VERSION 5.8 ;
BUSBITCHARS "[]" ;
DIVIDERCHAR "/" ;
UNITS
    DATABASE MICRONS 1000 ;
END UNITS

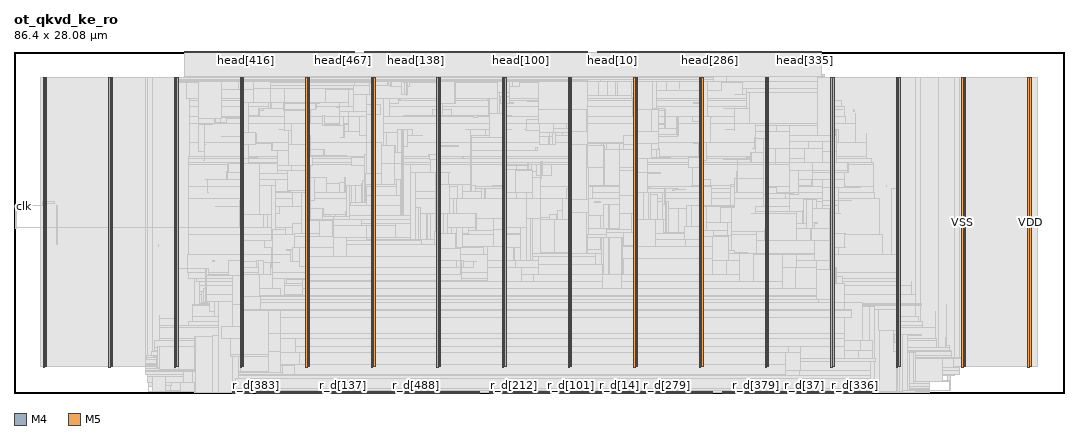
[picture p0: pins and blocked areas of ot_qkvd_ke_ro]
MACRO ot_qkvd_ke_ro
  FOREIGN ot_qkvd_ke_ro 0 0 ;
  CLASS BLOCK ;
  SIZE 86.4 BY 28.08 ;
  PIN clk
    DIRECTION INPUT ;
    USE SIGNAL ;
    PORT
      LAYER M4 ;
        RECT  0 15.312 0.084 15.336 ;
    END
  END clk
  PIN crq
    DIRECTION OUTPUT ;
    USE SIGNAL ;
    PORT
      LAYER M5 ;
        RECT  48.048 27.996 48.072 28.08 ;
    END
  END crq
  PIN en_i
    DIRECTION INPUT ;
    USE SIGNAL ;
    PORT
      LAYER M5 ;
        RECT  48.144 27.996 48.168 28.08 ;
    END
  END en_i
  PIN head[0]
    DIRECTION INPUT ;
    USE SIGNAL ;
    PORT
      LAYER M5 ;
        RECT  48.24 27.996 48.264 28.08 ;
    END
  END head[0]
  PIN head[100]
    DIRECTION INPUT ;
    USE SIGNAL ;
    PORT
      LAYER M5 ;
        RECT  41.712 27.996 41.736 28.08 ;
    END
  END head[100]
  PIN head[101]
    DIRECTION INPUT ;
    USE SIGNAL ;
    PORT
      LAYER M5 ;
        RECT  41.808 27.996 41.832 28.08 ;
    END
  END head[101]
  PIN head[102]
    DIRECTION INPUT ;
    USE SIGNAL ;
    PORT
      LAYER M5 ;
        RECT  41.904 27.996 41.928 28.08 ;
    END
  END head[102]
  PIN head[103]
    DIRECTION INPUT ;
    USE SIGNAL ;
    PORT
      LAYER M5 ;
        RECT  42 27.996 42.024 28.08 ;
    END
  END head[103]
  PIN head[104]
    DIRECTION INPUT ;
    USE SIGNAL ;
    PORT
      LAYER M5 ;
        RECT  42.096 27.996 42.12 28.08 ;
    END
  END head[104]
  PIN head[105]
    DIRECTION INPUT ;
    USE SIGNAL ;
    PORT
      LAYER M5 ;
        RECT  42.192 27.996 42.216 28.08 ;
    END
  END head[105]
  PIN head[106]
    DIRECTION INPUT ;
    USE SIGNAL ;
    PORT
      LAYER M5 ;
        RECT  42.288 27.996 42.312 28.08 ;
    END
  END head[106]
  PIN head[107]
    DIRECTION INPUT ;
    USE SIGNAL ;
    PORT
      LAYER M5 ;
        RECT  42.384 27.996 42.408 28.08 ;
    END
  END head[107]
  PIN head[108]
    DIRECTION INPUT ;
    USE SIGNAL ;
    PORT
      LAYER M5 ;
        RECT  42.48 27.996 42.504 28.08 ;
    END
  END head[108]
  PIN head[109]
    DIRECTION INPUT ;
    USE SIGNAL ;
    PORT
      LAYER M5 ;
        RECT  42.576 27.996 42.6 28.08 ;
    END
  END head[109]
  PIN head[10]
    DIRECTION INPUT ;
    USE SIGNAL ;
    PORT
      LAYER M5 ;
        RECT  49.2 27.996 49.224 28.08 ;
    END
  END head[10]
  PIN head[110]
    DIRECTION INPUT ;
    USE SIGNAL ;
    PORT
      LAYER M5 ;
        RECT  42.672 27.996 42.696 28.08 ;
    END
  END head[110]
  PIN head[111]
    DIRECTION INPUT ;
    USE SIGNAL ;
    PORT
      LAYER M5 ;
        RECT  42.768 27.996 42.792 28.08 ;
    END
  END head[111]
  PIN head[112]
    DIRECTION INPUT ;
    USE SIGNAL ;
    PORT
      LAYER M5 ;
        RECT  42.864 27.996 42.888 28.08 ;
    END
  END head[112]
  PIN head[113]
    DIRECTION INPUT ;
    USE SIGNAL ;
    PORT
      LAYER M5 ;
        RECT  42.96 27.996 42.984 28.08 ;
    END
  END head[113]
  PIN head[114]
    DIRECTION INPUT ;
    USE SIGNAL ;
    PORT
      LAYER M5 ;
        RECT  43.056 27.996 43.08 28.08 ;
    END
  END head[114]
  PIN head[115]
    DIRECTION INPUT ;
    USE SIGNAL ;
    PORT
      LAYER M5 ;
        RECT  43.152 27.996 43.176 28.08 ;
    END
  END head[115]
  PIN head[116]
    DIRECTION INPUT ;
    USE SIGNAL ;
    PORT
      LAYER M5 ;
        RECT  43.248 27.996 43.272 28.08 ;
    END
  END head[116]
  PIN head[117]
    DIRECTION INPUT ;
    USE SIGNAL ;
    PORT
      LAYER M5 ;
        RECT  43.344 27.996 43.368 28.08 ;
    END
  END head[117]
  PIN head[118]
    DIRECTION INPUT ;
    USE SIGNAL ;
    PORT
      LAYER M5 ;
        RECT  43.44 27.996 43.464 28.08 ;
    END
  END head[118]
  PIN head[119]
    DIRECTION INPUT ;
    USE SIGNAL ;
    PORT
      LAYER M5 ;
        RECT  43.536 27.996 43.56 28.08 ;
    END
  END head[119]
  PIN head[11]
    DIRECTION INPUT ;
    USE SIGNAL ;
    PORT
      LAYER M5 ;
        RECT  49.296 27.996 49.32 28.08 ;
    END
  END head[11]
  PIN head[120]
    DIRECTION INPUT ;
    USE SIGNAL ;
    PORT
      LAYER M5 ;
        RECT  43.632 27.996 43.656 28.08 ;
    END
  END head[120]
  PIN head[121]
    DIRECTION INPUT ;
    USE SIGNAL ;
    PORT
      LAYER M5 ;
        RECT  43.728 27.996 43.752 28.08 ;
    END
  END head[121]
  PIN head[122]
    DIRECTION INPUT ;
    USE SIGNAL ;
    PORT
      LAYER M5 ;
        RECT  43.824 27.996 43.848 28.08 ;
    END
  END head[122]
  PIN head[123]
    DIRECTION INPUT ;
    USE SIGNAL ;
    PORT
      LAYER M5 ;
        RECT  43.92 27.996 43.944 28.08 ;
    END
  END head[123]
  PIN head[124]
    DIRECTION INPUT ;
    USE SIGNAL ;
    PORT
      LAYER M5 ;
        RECT  44.016 27.996 44.04 28.08 ;
    END
  END head[124]
  PIN head[125]
    DIRECTION INPUT ;
    USE SIGNAL ;
    PORT
      LAYER M5 ;
        RECT  44.112 27.996 44.136 28.08 ;
    END
  END head[125]
  PIN head[126]
    DIRECTION INPUT ;
    USE SIGNAL ;
    PORT
      LAYER M5 ;
        RECT  31.92 27.996 31.944 28.08 ;
    END
  END head[126]
  PIN head[127]
    DIRECTION INPUT ;
    USE SIGNAL ;
    PORT
      LAYER M5 ;
        RECT  32.016 27.996 32.04 28.08 ;
    END
  END head[127]
  PIN head[128]
    DIRECTION INPUT ;
    USE SIGNAL ;
    PORT
      LAYER M5 ;
        RECT  32.112 27.996 32.136 28.08 ;
    END
  END head[128]
  PIN head[129]
    DIRECTION INPUT ;
    USE SIGNAL ;
    PORT
      LAYER M5 ;
        RECT  32.208 27.996 32.232 28.08 ;
    END
  END head[129]
  PIN head[12]
    DIRECTION INPUT ;
    USE SIGNAL ;
    PORT
      LAYER M5 ;
        RECT  49.392 27.996 49.416 28.08 ;
    END
  END head[12]
  PIN head[130]
    DIRECTION INPUT ;
    USE SIGNAL ;
    PORT
      LAYER M5 ;
        RECT  32.304 27.996 32.328 28.08 ;
    END
  END head[130]
  PIN head[131]
    DIRECTION INPUT ;
    USE SIGNAL ;
    PORT
      LAYER M5 ;
        RECT  32.4 27.996 32.424 28.08 ;
    END
  END head[131]
  PIN head[132]
    DIRECTION INPUT ;
    USE SIGNAL ;
    PORT
      LAYER M5 ;
        RECT  32.496 27.996 32.52 28.08 ;
    END
  END head[132]
  PIN head[133]
    DIRECTION INPUT ;
    USE SIGNAL ;
    PORT
      LAYER M5 ;
        RECT  32.592 27.996 32.616 28.08 ;
    END
  END head[133]
  PIN head[134]
    DIRECTION INPUT ;
    USE SIGNAL ;
    PORT
      LAYER M5 ;
        RECT  32.688 27.996 32.712 28.08 ;
    END
  END head[134]
  PIN head[135]
    DIRECTION INPUT ;
    USE SIGNAL ;
    PORT
      LAYER M5 ;
        RECT  32.784 27.996 32.808 28.08 ;
    END
  END head[135]
  PIN head[136]
    DIRECTION INPUT ;
    USE SIGNAL ;
    PORT
      LAYER M5 ;
        RECT  32.88 27.996 32.904 28.08 ;
    END
  END head[136]
  PIN head[137]
    DIRECTION INPUT ;
    USE SIGNAL ;
    PORT
      LAYER M5 ;
        RECT  32.976 27.996 33 28.08 ;
    END
  END head[137]
  PIN head[138]
    DIRECTION INPUT ;
    USE SIGNAL ;
    PORT
      LAYER M5 ;
        RECT  33.072 27.996 33.096 28.08 ;
    END
  END head[138]
  PIN head[139]
    DIRECTION INPUT ;
    USE SIGNAL ;
    PORT
      LAYER M5 ;
        RECT  33.168 27.996 33.192 28.08 ;
    END
  END head[139]
  PIN head[13]
    DIRECTION INPUT ;
    USE SIGNAL ;
    PORT
      LAYER M5 ;
        RECT  49.488 27.996 49.512 28.08 ;
    END
  END head[13]
  PIN head[140]
    DIRECTION INPUT ;
    USE SIGNAL ;
    PORT
      LAYER M5 ;
        RECT  33.264 27.996 33.288 28.08 ;
    END
  END head[140]
  PIN head[141]
    DIRECTION INPUT ;
    USE SIGNAL ;
    PORT
      LAYER M5 ;
        RECT  33.36 27.996 33.384 28.08 ;
    END
  END head[141]
  PIN head[142]
    DIRECTION INPUT ;
    USE SIGNAL ;
    PORT
      LAYER M5 ;
        RECT  33.456 27.996 33.48 28.08 ;
    END
  END head[142]
  PIN head[143]
    DIRECTION INPUT ;
    USE SIGNAL ;
    PORT
      LAYER M5 ;
        RECT  33.552 27.996 33.576 28.08 ;
    END
  END head[143]
  PIN head[144]
    DIRECTION INPUT ;
    USE SIGNAL ;
    PORT
      LAYER M5 ;
        RECT  33.648 27.996 33.672 28.08 ;
    END
  END head[144]
  PIN head[145]
    DIRECTION INPUT ;
    USE SIGNAL ;
    PORT
      LAYER M5 ;
        RECT  33.744 27.996 33.768 28.08 ;
    END
  END head[145]
  PIN head[146]
    DIRECTION INPUT ;
    USE SIGNAL ;
    PORT
      LAYER M5 ;
        RECT  33.84 27.996 33.864 28.08 ;
    END
  END head[146]
  PIN head[147]
    DIRECTION INPUT ;
    USE SIGNAL ;
    PORT
      LAYER M5 ;
        RECT  33.936 27.996 33.96 28.08 ;
    END
  END head[147]
  PIN head[148]
    DIRECTION INPUT ;
    USE SIGNAL ;
    PORT
      LAYER M5 ;
        RECT  34.032 27.996 34.056 28.08 ;
    END
  END head[148]
  PIN head[149]
    DIRECTION INPUT ;
    USE SIGNAL ;
    PORT
      LAYER M5 ;
        RECT  34.128 27.996 34.152 28.08 ;
    END
  END head[149]
  PIN head[14]
    DIRECTION INPUT ;
    USE SIGNAL ;
    PORT
      LAYER M5 ;
        RECT  49.584 27.996 49.608 28.08 ;
    END
  END head[14]
  PIN head[150]
    DIRECTION INPUT ;
    USE SIGNAL ;
    PORT
      LAYER M5 ;
        RECT  34.224 27.996 34.248 28.08 ;
    END
  END head[150]
  PIN head[151]
    DIRECTION INPUT ;
    USE SIGNAL ;
    PORT
      LAYER M5 ;
        RECT  34.32 27.996 34.344 28.08 ;
    END
  END head[151]
  PIN head[152]
    DIRECTION INPUT ;
    USE SIGNAL ;
    PORT
      LAYER M5 ;
        RECT  34.416 27.996 34.44 28.08 ;
    END
  END head[152]
  PIN head[153]
    DIRECTION INPUT ;
    USE SIGNAL ;
    PORT
      LAYER M5 ;
        RECT  34.512 27.996 34.536 28.08 ;
    END
  END head[153]
  PIN head[154]
    DIRECTION INPUT ;
    USE SIGNAL ;
    PORT
      LAYER M5 ;
        RECT  34.608 27.996 34.632 28.08 ;
    END
  END head[154]
  PIN head[155]
    DIRECTION INPUT ;
    USE SIGNAL ;
    PORT
      LAYER M5 ;
        RECT  34.704 27.996 34.728 28.08 ;
    END
  END head[155]
  PIN head[156]
    DIRECTION INPUT ;
    USE SIGNAL ;
    PORT
      LAYER M5 ;
        RECT  34.8 27.996 34.824 28.08 ;
    END
  END head[156]
  PIN head[157]
    DIRECTION INPUT ;
    USE SIGNAL ;
    PORT
      LAYER M5 ;
        RECT  34.896 27.996 34.92 28.08 ;
    END
  END head[157]
  PIN head[158]
    DIRECTION INPUT ;
    USE SIGNAL ;
    PORT
      LAYER M5 ;
        RECT  38.064 27.996 38.088 28.08 ;
    END
  END head[158]
  PIN head[159]
    DIRECTION INPUT ;
    USE SIGNAL ;
    PORT
      LAYER M5 ;
        RECT  38.16 27.996 38.184 28.08 ;
    END
  END head[159]
  PIN head[15]
    DIRECTION INPUT ;
    USE SIGNAL ;
    PORT
      LAYER M5 ;
        RECT  49.68 27.996 49.704 28.08 ;
    END
  END head[15]
  PIN head[160]
    DIRECTION INPUT ;
    USE SIGNAL ;
    PORT
      LAYER M5 ;
        RECT  38.256 27.996 38.28 28.08 ;
    END
  END head[160]
  PIN head[161]
    DIRECTION INPUT ;
    USE SIGNAL ;
    PORT
      LAYER M5 ;
        RECT  38.352 27.996 38.376 28.08 ;
    END
  END head[161]
  PIN head[162]
    DIRECTION INPUT ;
    USE SIGNAL ;
    PORT
      LAYER M5 ;
        RECT  38.448 27.996 38.472 28.08 ;
    END
  END head[162]
  PIN head[163]
    DIRECTION INPUT ;
    USE SIGNAL ;
    PORT
      LAYER M5 ;
        RECT  38.544 27.996 38.568 28.08 ;
    END
  END head[163]
  PIN head[164]
    DIRECTION INPUT ;
    USE SIGNAL ;
    PORT
      LAYER M5 ;
        RECT  38.64 27.996 38.664 28.08 ;
    END
  END head[164]
  PIN head[165]
    DIRECTION INPUT ;
    USE SIGNAL ;
    PORT
      LAYER M5 ;
        RECT  38.736 27.996 38.76 28.08 ;
    END
  END head[165]
  PIN head[166]
    DIRECTION INPUT ;
    USE SIGNAL ;
    PORT
      LAYER M5 ;
        RECT  38.832 27.996 38.856 28.08 ;
    END
  END head[166]
  PIN head[167]
    DIRECTION INPUT ;
    USE SIGNAL ;
    PORT
      LAYER M5 ;
        RECT  38.928 27.996 38.952 28.08 ;
    END
  END head[167]
  PIN head[168]
    DIRECTION INPUT ;
    USE SIGNAL ;
    PORT
      LAYER M5 ;
        RECT  39.024 27.996 39.048 28.08 ;
    END
  END head[168]
  PIN head[169]
    DIRECTION INPUT ;
    USE SIGNAL ;
    PORT
      LAYER M5 ;
        RECT  39.12 27.996 39.144 28.08 ;
    END
  END head[169]
  PIN head[16]
    DIRECTION INPUT ;
    USE SIGNAL ;
    PORT
      LAYER M5 ;
        RECT  49.776 27.996 49.8 28.08 ;
    END
  END head[16]
  PIN head[170]
    DIRECTION INPUT ;
    USE SIGNAL ;
    PORT
      LAYER M5 ;
        RECT  39.216 27.996 39.24 28.08 ;
    END
  END head[170]
  PIN head[171]
    DIRECTION INPUT ;
    USE SIGNAL ;
    PORT
      LAYER M5 ;
        RECT  39.312 27.996 39.336 28.08 ;
    END
  END head[171]
  PIN head[172]
    DIRECTION INPUT ;
    USE SIGNAL ;
    PORT
      LAYER M5 ;
        RECT  39.408 27.996 39.432 28.08 ;
    END
  END head[172]
  PIN head[173]
    DIRECTION INPUT ;
    USE SIGNAL ;
    PORT
      LAYER M5 ;
        RECT  39.504 27.996 39.528 28.08 ;
    END
  END head[173]
  PIN head[174]
    DIRECTION INPUT ;
    USE SIGNAL ;
    PORT
      LAYER M5 ;
        RECT  39.6 27.996 39.624 28.08 ;
    END
  END head[174]
  PIN head[175]
    DIRECTION INPUT ;
    USE SIGNAL ;
    PORT
      LAYER M5 ;
        RECT  39.696 27.996 39.72 28.08 ;
    END
  END head[175]
  PIN head[176]
    DIRECTION INPUT ;
    USE SIGNAL ;
    PORT
      LAYER M5 ;
        RECT  39.792 27.996 39.816 28.08 ;
    END
  END head[176]
  PIN head[177]
    DIRECTION INPUT ;
    USE SIGNAL ;
    PORT
      LAYER M5 ;
        RECT  39.888 27.996 39.912 28.08 ;
    END
  END head[177]
  PIN head[178]
    DIRECTION INPUT ;
    USE SIGNAL ;
    PORT
      LAYER M5 ;
        RECT  39.984 27.996 40.008 28.08 ;
    END
  END head[178]
  PIN head[179]
    DIRECTION INPUT ;
    USE SIGNAL ;
    PORT
      LAYER M5 ;
        RECT  40.08 27.996 40.104 28.08 ;
    END
  END head[179]
  PIN head[17]
    DIRECTION INPUT ;
    USE SIGNAL ;
    PORT
      LAYER M5 ;
        RECT  49.872 27.996 49.896 28.08 ;
    END
  END head[17]
  PIN head[180]
    DIRECTION INPUT ;
    USE SIGNAL ;
    PORT
      LAYER M5 ;
        RECT  40.176 27.996 40.2 28.08 ;
    END
  END head[180]
  PIN head[181]
    DIRECTION INPUT ;
    USE SIGNAL ;
    PORT
      LAYER M5 ;
        RECT  40.272 27.996 40.296 28.08 ;
    END
  END head[181]
  PIN head[182]
    DIRECTION INPUT ;
    USE SIGNAL ;
    PORT
      LAYER M5 ;
        RECT  40.368 27.996 40.392 28.08 ;
    END
  END head[182]
  PIN head[183]
    DIRECTION INPUT ;
    USE SIGNAL ;
    PORT
      LAYER M5 ;
        RECT  40.464 27.996 40.488 28.08 ;
    END
  END head[183]
  PIN head[184]
    DIRECTION INPUT ;
    USE SIGNAL ;
    PORT
      LAYER M5 ;
        RECT  40.56 27.996 40.584 28.08 ;
    END
  END head[184]
  PIN head[185]
    DIRECTION INPUT ;
    USE SIGNAL ;
    PORT
      LAYER M5 ;
        RECT  40.656 27.996 40.68 28.08 ;
    END
  END head[185]
  PIN head[186]
    DIRECTION INPUT ;
    USE SIGNAL ;
    PORT
      LAYER M5 ;
        RECT  40.752 27.996 40.776 28.08 ;
    END
  END head[186]
  PIN head[187]
    DIRECTION INPUT ;
    USE SIGNAL ;
    PORT
      LAYER M5 ;
        RECT  40.848 27.996 40.872 28.08 ;
    END
  END head[187]
  PIN head[188]
    DIRECTION INPUT ;
    USE SIGNAL ;
    PORT
      LAYER M5 ;
        RECT  40.944 27.996 40.968 28.08 ;
    END
  END head[188]
  PIN head[189]
    DIRECTION INPUT ;
    USE SIGNAL ;
    PORT
      LAYER M5 ;
        RECT  41.04 27.996 41.064 28.08 ;
    END
  END head[189]
  PIN head[18]
    DIRECTION INPUT ;
    USE SIGNAL ;
    PORT
      LAYER M5 ;
        RECT  49.968 27.996 49.992 28.08 ;
    END
  END head[18]
  PIN head[190]
    DIRECTION INPUT ;
    USE SIGNAL ;
    PORT
      LAYER M5 ;
        RECT  34.992 27.996 35.016 28.08 ;
    END
  END head[190]
  PIN head[191]
    DIRECTION INPUT ;
    USE SIGNAL ;
    PORT
      LAYER M5 ;
        RECT  35.088 27.996 35.112 28.08 ;
    END
  END head[191]
  PIN head[192]
    DIRECTION INPUT ;
    USE SIGNAL ;
    PORT
      LAYER M5 ;
        RECT  35.184 27.996 35.208 28.08 ;
    END
  END head[192]
  PIN head[193]
    DIRECTION INPUT ;
    USE SIGNAL ;
    PORT
      LAYER M5 ;
        RECT  35.28 27.996 35.304 28.08 ;
    END
  END head[193]
  PIN head[194]
    DIRECTION INPUT ;
    USE SIGNAL ;
    PORT
      LAYER M5 ;
        RECT  35.376 27.996 35.4 28.08 ;
    END
  END head[194]
  PIN head[195]
    DIRECTION INPUT ;
    USE SIGNAL ;
    PORT
      LAYER M5 ;
        RECT  35.472 27.996 35.496 28.08 ;
    END
  END head[195]
  PIN head[196]
    DIRECTION INPUT ;
    USE SIGNAL ;
    PORT
      LAYER M5 ;
        RECT  35.568 27.996 35.592 28.08 ;
    END
  END head[196]
  PIN head[197]
    DIRECTION INPUT ;
    USE SIGNAL ;
    PORT
      LAYER M5 ;
        RECT  35.664 27.996 35.688 28.08 ;
    END
  END head[197]
  PIN head[198]
    DIRECTION INPUT ;
    USE SIGNAL ;
    PORT
      LAYER M5 ;
        RECT  35.76 27.996 35.784 28.08 ;
    END
  END head[198]
  PIN head[199]
    DIRECTION INPUT ;
    USE SIGNAL ;
    PORT
      LAYER M5 ;
        RECT  35.856 27.996 35.88 28.08 ;
    END
  END head[199]
  PIN head[19]
    DIRECTION INPUT ;
    USE SIGNAL ;
    PORT
      LAYER M5 ;
        RECT  50.064 27.996 50.088 28.08 ;
    END
  END head[19]
  PIN head[1]
    DIRECTION INPUT ;
    USE SIGNAL ;
    PORT
      LAYER M5 ;
        RECT  48.336 27.996 48.36 28.08 ;
    END
  END head[1]
  PIN head[200]
    DIRECTION INPUT ;
    USE SIGNAL ;
    PORT
      LAYER M5 ;
        RECT  35.952 27.996 35.976 28.08 ;
    END
  END head[200]
  PIN head[201]
    DIRECTION INPUT ;
    USE SIGNAL ;
    PORT
      LAYER M5 ;
        RECT  36.048 27.996 36.072 28.08 ;
    END
  END head[201]
  PIN head[202]
    DIRECTION INPUT ;
    USE SIGNAL ;
    PORT
      LAYER M5 ;
        RECT  36.144 27.996 36.168 28.08 ;
    END
  END head[202]
  PIN head[203]
    DIRECTION INPUT ;
    USE SIGNAL ;
    PORT
      LAYER M5 ;
        RECT  36.24 27.996 36.264 28.08 ;
    END
  END head[203]
  PIN head[204]
    DIRECTION INPUT ;
    USE SIGNAL ;
    PORT
      LAYER M5 ;
        RECT  36.336 27.996 36.36 28.08 ;
    END
  END head[204]
  PIN head[205]
    DIRECTION INPUT ;
    USE SIGNAL ;
    PORT
      LAYER M5 ;
        RECT  36.432 27.996 36.456 28.08 ;
    END
  END head[205]
  PIN head[206]
    DIRECTION INPUT ;
    USE SIGNAL ;
    PORT
      LAYER M5 ;
        RECT  36.528 27.996 36.552 28.08 ;
    END
  END head[206]
  PIN head[207]
    DIRECTION INPUT ;
    USE SIGNAL ;
    PORT
      LAYER M5 ;
        RECT  36.624 27.996 36.648 28.08 ;
    END
  END head[207]
  PIN head[208]
    DIRECTION INPUT ;
    USE SIGNAL ;
    PORT
      LAYER M5 ;
        RECT  36.72 27.996 36.744 28.08 ;
    END
  END head[208]
  PIN head[209]
    DIRECTION INPUT ;
    USE SIGNAL ;
    PORT
      LAYER M5 ;
        RECT  36.816 27.996 36.84 28.08 ;
    END
  END head[209]
  PIN head[20]
    DIRECTION INPUT ;
    USE SIGNAL ;
    PORT
      LAYER M5 ;
        RECT  50.16 27.996 50.184 28.08 ;
    END
  END head[20]
  PIN head[210]
    DIRECTION INPUT ;
    USE SIGNAL ;
    PORT
      LAYER M5 ;
        RECT  36.912 27.996 36.936 28.08 ;
    END
  END head[210]
  PIN head[211]
    DIRECTION INPUT ;
    USE SIGNAL ;
    PORT
      LAYER M5 ;
        RECT  37.008 27.996 37.032 28.08 ;
    END
  END head[211]
  PIN head[212]
    DIRECTION INPUT ;
    USE SIGNAL ;
    PORT
      LAYER M5 ;
        RECT  37.104 27.996 37.128 28.08 ;
    END
  END head[212]
  PIN head[213]
    DIRECTION INPUT ;
    USE SIGNAL ;
    PORT
      LAYER M5 ;
        RECT  37.2 27.996 37.224 28.08 ;
    END
  END head[213]
  PIN head[214]
    DIRECTION INPUT ;
    USE SIGNAL ;
    PORT
      LAYER M5 ;
        RECT  37.296 27.996 37.32 28.08 ;
    END
  END head[214]
  PIN head[215]
    DIRECTION INPUT ;
    USE SIGNAL ;
    PORT
      LAYER M5 ;
        RECT  37.392 27.996 37.416 28.08 ;
    END
  END head[215]
  PIN head[216]
    DIRECTION INPUT ;
    USE SIGNAL ;
    PORT
      LAYER M5 ;
        RECT  37.488 27.996 37.512 28.08 ;
    END
  END head[216]
  PIN head[217]
    DIRECTION INPUT ;
    USE SIGNAL ;
    PORT
      LAYER M5 ;
        RECT  37.584 27.996 37.608 28.08 ;
    END
  END head[217]
  PIN head[218]
    DIRECTION INPUT ;
    USE SIGNAL ;
    PORT
      LAYER M5 ;
        RECT  37.68 27.996 37.704 28.08 ;
    END
  END head[218]
  PIN head[219]
    DIRECTION INPUT ;
    USE SIGNAL ;
    PORT
      LAYER M5 ;
        RECT  37.776 27.996 37.8 28.08 ;
    END
  END head[219]
  PIN head[21]
    DIRECTION INPUT ;
    USE SIGNAL ;
    PORT
      LAYER M5 ;
        RECT  50.256 27.996 50.28 28.08 ;
    END
  END head[21]
  PIN head[220]
    DIRECTION INPUT ;
    USE SIGNAL ;
    PORT
      LAYER M5 ;
        RECT  37.872 27.996 37.896 28.08 ;
    END
  END head[220]
  PIN head[221]
    DIRECTION INPUT ;
    USE SIGNAL ;
    PORT
      LAYER M5 ;
        RECT  37.968 27.996 37.992 28.08 ;
    END
  END head[221]
  PIN head[222]
    DIRECTION INPUT ;
    USE SIGNAL ;
    PORT
      LAYER M5 ;
        RECT  28.848 27.996 28.872 28.08 ;
    END
  END head[222]
  PIN head[223]
    DIRECTION INPUT ;
    USE SIGNAL ;
    PORT
      LAYER M5 ;
        RECT  28.944 27.996 28.968 28.08 ;
    END
  END head[223]
  PIN head[224]
    DIRECTION INPUT ;
    USE SIGNAL ;
    PORT
      LAYER M5 ;
        RECT  29.04 27.996 29.064 28.08 ;
    END
  END head[224]
  PIN head[225]
    DIRECTION INPUT ;
    USE SIGNAL ;
    PORT
      LAYER M5 ;
        RECT  29.136 27.996 29.16 28.08 ;
    END
  END head[225]
  PIN head[226]
    DIRECTION INPUT ;
    USE SIGNAL ;
    PORT
      LAYER M5 ;
        RECT  29.232 27.996 29.256 28.08 ;
    END
  END head[226]
  PIN head[227]
    DIRECTION INPUT ;
    USE SIGNAL ;
    PORT
      LAYER M5 ;
        RECT  29.328 27.996 29.352 28.08 ;
    END
  END head[227]
  PIN head[228]
    DIRECTION INPUT ;
    USE SIGNAL ;
    PORT
      LAYER M5 ;
        RECT  29.424 27.996 29.448 28.08 ;
    END
  END head[228]
  PIN head[229]
    DIRECTION INPUT ;
    USE SIGNAL ;
    PORT
      LAYER M5 ;
        RECT  29.52 27.996 29.544 28.08 ;
    END
  END head[229]
  PIN head[22]
    DIRECTION INPUT ;
    USE SIGNAL ;
    PORT
      LAYER M5 ;
        RECT  50.352 27.996 50.376 28.08 ;
    END
  END head[22]
  PIN head[230]
    DIRECTION INPUT ;
    USE SIGNAL ;
    PORT
      LAYER M5 ;
        RECT  29.616 27.996 29.64 28.08 ;
    END
  END head[230]
  PIN head[231]
    DIRECTION INPUT ;
    USE SIGNAL ;
    PORT
      LAYER M5 ;
        RECT  29.712 27.996 29.736 28.08 ;
    END
  END head[231]
  PIN head[232]
    DIRECTION INPUT ;
    USE SIGNAL ;
    PORT
      LAYER M5 ;
        RECT  29.808 27.996 29.832 28.08 ;
    END
  END head[232]
  PIN head[233]
    DIRECTION INPUT ;
    USE SIGNAL ;
    PORT
      LAYER M5 ;
        RECT  29.904 27.996 29.928 28.08 ;
    END
  END head[233]
  PIN head[234]
    DIRECTION INPUT ;
    USE SIGNAL ;
    PORT
      LAYER M5 ;
        RECT  30 27.996 30.024 28.08 ;
    END
  END head[234]
  PIN head[235]
    DIRECTION INPUT ;
    USE SIGNAL ;
    PORT
      LAYER M5 ;
        RECT  30.096 27.996 30.12 28.08 ;
    END
  END head[235]
  PIN head[236]
    DIRECTION INPUT ;
    USE SIGNAL ;
    PORT
      LAYER M5 ;
        RECT  30.192 27.996 30.216 28.08 ;
    END
  END head[236]
  PIN head[237]
    DIRECTION INPUT ;
    USE SIGNAL ;
    PORT
      LAYER M5 ;
        RECT  30.288 27.996 30.312 28.08 ;
    END
  END head[237]
  PIN head[238]
    DIRECTION INPUT ;
    USE SIGNAL ;
    PORT
      LAYER M5 ;
        RECT  30.384 27.996 30.408 28.08 ;
    END
  END head[238]
  PIN head[239]
    DIRECTION INPUT ;
    USE SIGNAL ;
    PORT
      LAYER M5 ;
        RECT  30.48 27.996 30.504 28.08 ;
    END
  END head[239]
  PIN head[23]
    DIRECTION INPUT ;
    USE SIGNAL ;
    PORT
      LAYER M5 ;
        RECT  50.448 27.996 50.472 28.08 ;
    END
  END head[23]
  PIN head[240]
    DIRECTION INPUT ;
    USE SIGNAL ;
    PORT
      LAYER M5 ;
        RECT  30.576 27.996 30.6 28.08 ;
    END
  END head[240]
  PIN head[241]
    DIRECTION INPUT ;
    USE SIGNAL ;
    PORT
      LAYER M5 ;
        RECT  30.672 27.996 30.696 28.08 ;
    END
  END head[241]
  PIN head[242]
    DIRECTION INPUT ;
    USE SIGNAL ;
    PORT
      LAYER M5 ;
        RECT  30.768 27.996 30.792 28.08 ;
    END
  END head[242]
  PIN head[243]
    DIRECTION INPUT ;
    USE SIGNAL ;
    PORT
      LAYER M5 ;
        RECT  30.864 27.996 30.888 28.08 ;
    END
  END head[243]
  PIN head[244]
    DIRECTION INPUT ;
    USE SIGNAL ;
    PORT
      LAYER M5 ;
        RECT  30.96 27.996 30.984 28.08 ;
    END
  END head[244]
  PIN head[245]
    DIRECTION INPUT ;
    USE SIGNAL ;
    PORT
      LAYER M5 ;
        RECT  31.056 27.996 31.08 28.08 ;
    END
  END head[245]
  PIN head[246]
    DIRECTION INPUT ;
    USE SIGNAL ;
    PORT
      LAYER M5 ;
        RECT  31.152 27.996 31.176 28.08 ;
    END
  END head[246]
  PIN head[247]
    DIRECTION INPUT ;
    USE SIGNAL ;
    PORT
      LAYER M5 ;
        RECT  31.248 27.996 31.272 28.08 ;
    END
  END head[247]
  PIN head[248]
    DIRECTION INPUT ;
    USE SIGNAL ;
    PORT
      LAYER M5 ;
        RECT  31.344 27.996 31.368 28.08 ;
    END
  END head[248]
  PIN head[249]
    DIRECTION INPUT ;
    USE SIGNAL ;
    PORT
      LAYER M5 ;
        RECT  31.44 27.996 31.464 28.08 ;
    END
  END head[249]
  PIN head[24]
    DIRECTION INPUT ;
    USE SIGNAL ;
    PORT
      LAYER M5 ;
        RECT  50.544 27.996 50.568 28.08 ;
    END
  END head[24]
  PIN head[250]
    DIRECTION INPUT ;
    USE SIGNAL ;
    PORT
      LAYER M5 ;
        RECT  31.536 27.996 31.56 28.08 ;
    END
  END head[250]
  PIN head[251]
    DIRECTION INPUT ;
    USE SIGNAL ;
    PORT
      LAYER M5 ;
        RECT  31.632 27.996 31.656 28.08 ;
    END
  END head[251]
  PIN head[252]
    DIRECTION INPUT ;
    USE SIGNAL ;
    PORT
      LAYER M5 ;
        RECT  31.728 27.996 31.752 28.08 ;
    END
  END head[252]
  PIN head[253]
    DIRECTION INPUT ;
    USE SIGNAL ;
    PORT
      LAYER M5 ;
        RECT  31.824 27.996 31.848 28.08 ;
    END
  END head[253]
  PIN head[254]
    DIRECTION INPUT ;
    USE SIGNAL ;
    PORT
      LAYER M5 ;
        RECT  51.12 27.996 51.144 28.08 ;
    END
  END head[254]
  PIN head[255]
    DIRECTION INPUT ;
    USE SIGNAL ;
    PORT
      LAYER M5 ;
        RECT  51.216 27.996 51.24 28.08 ;
    END
  END head[255]
  PIN head[256]
    DIRECTION INPUT ;
    USE SIGNAL ;
    PORT
      LAYER M5 ;
        RECT  51.312 27.996 51.336 28.08 ;
    END
  END head[256]
  PIN head[257]
    DIRECTION INPUT ;
    USE SIGNAL ;
    PORT
      LAYER M5 ;
        RECT  51.408 27.996 51.432 28.08 ;
    END
  END head[257]
  PIN head[258]
    DIRECTION INPUT ;
    USE SIGNAL ;
    PORT
      LAYER M5 ;
        RECT  51.504 27.996 51.528 28.08 ;
    END
  END head[258]
  PIN head[259]
    DIRECTION INPUT ;
    USE SIGNAL ;
    PORT
      LAYER M5 ;
        RECT  51.6 27.996 51.624 28.08 ;
    END
  END head[259]
  PIN head[25]
    DIRECTION INPUT ;
    USE SIGNAL ;
    PORT
      LAYER M5 ;
        RECT  50.64 27.996 50.664 28.08 ;
    END
  END head[25]
  PIN head[260]
    DIRECTION INPUT ;
    USE SIGNAL ;
    PORT
      LAYER M5 ;
        RECT  51.696 27.996 51.72 28.08 ;
    END
  END head[260]
  PIN head[261]
    DIRECTION INPUT ;
    USE SIGNAL ;
    PORT
      LAYER M5 ;
        RECT  51.792 27.996 51.816 28.08 ;
    END
  END head[261]
  PIN head[262]
    DIRECTION INPUT ;
    USE SIGNAL ;
    PORT
      LAYER M5 ;
        RECT  51.888 27.996 51.912 28.08 ;
    END
  END head[262]
  PIN head[263]
    DIRECTION INPUT ;
    USE SIGNAL ;
    PORT
      LAYER M5 ;
        RECT  51.984 27.996 52.008 28.08 ;
    END
  END head[263]
  PIN head[264]
    DIRECTION INPUT ;
    USE SIGNAL ;
    PORT
      LAYER M5 ;
        RECT  52.08 27.996 52.104 28.08 ;
    END
  END head[264]
  PIN head[265]
    DIRECTION INPUT ;
    USE SIGNAL ;
    PORT
      LAYER M5 ;
        RECT  52.176 27.996 52.2 28.08 ;
    END
  END head[265]
  PIN head[266]
    DIRECTION INPUT ;
    USE SIGNAL ;
    PORT
      LAYER M5 ;
        RECT  52.272 27.996 52.296 28.08 ;
    END
  END head[266]
  PIN head[267]
    DIRECTION INPUT ;
    USE SIGNAL ;
    PORT
      LAYER M5 ;
        RECT  52.368 27.996 52.392 28.08 ;
    END
  END head[267]
  PIN head[268]
    DIRECTION INPUT ;
    USE SIGNAL ;
    PORT
      LAYER M5 ;
        RECT  52.464 27.996 52.488 28.08 ;
    END
  END head[268]
  PIN head[269]
    DIRECTION INPUT ;
    USE SIGNAL ;
    PORT
      LAYER M5 ;
        RECT  52.56 27.996 52.584 28.08 ;
    END
  END head[269]
  PIN head[26]
    DIRECTION INPUT ;
    USE SIGNAL ;
    PORT
      LAYER M5 ;
        RECT  50.736 27.996 50.76 28.08 ;
    END
  END head[26]
  PIN head[270]
    DIRECTION INPUT ;
    USE SIGNAL ;
    PORT
      LAYER M5 ;
        RECT  52.656 27.996 52.68 28.08 ;
    END
  END head[270]
  PIN head[271]
    DIRECTION INPUT ;
    USE SIGNAL ;
    PORT
      LAYER M5 ;
        RECT  52.752 27.996 52.776 28.08 ;
    END
  END head[271]
  PIN head[272]
    DIRECTION INPUT ;
    USE SIGNAL ;
    PORT
      LAYER M5 ;
        RECT  52.848 27.996 52.872 28.08 ;
    END
  END head[272]
  PIN head[273]
    DIRECTION INPUT ;
    USE SIGNAL ;
    PORT
      LAYER M5 ;
        RECT  52.944 27.996 52.968 28.08 ;
    END
  END head[273]
  PIN head[274]
    DIRECTION INPUT ;
    USE SIGNAL ;
    PORT
      LAYER M5 ;
        RECT  53.04 27.996 53.064 28.08 ;
    END
  END head[274]
  PIN head[275]
    DIRECTION INPUT ;
    USE SIGNAL ;
    PORT
      LAYER M5 ;
        RECT  53.136 27.996 53.16 28.08 ;
    END
  END head[275]
  PIN head[276]
    DIRECTION INPUT ;
    USE SIGNAL ;
    PORT
      LAYER M5 ;
        RECT  53.232 27.996 53.256 28.08 ;
    END
  END head[276]
  PIN head[277]
    DIRECTION INPUT ;
    USE SIGNAL ;
    PORT
      LAYER M5 ;
        RECT  53.328 27.996 53.352 28.08 ;
    END
  END head[277]
  PIN head[278]
    DIRECTION INPUT ;
    USE SIGNAL ;
    PORT
      LAYER M5 ;
        RECT  53.424 27.996 53.448 28.08 ;
    END
  END head[278]
  PIN head[279]
    DIRECTION INPUT ;
    USE SIGNAL ;
    PORT
      LAYER M5 ;
        RECT  53.52 27.996 53.544 28.08 ;
    END
  END head[279]
  PIN head[27]
    DIRECTION INPUT ;
    USE SIGNAL ;
    PORT
      LAYER M5 ;
        RECT  50.832 27.996 50.856 28.08 ;
    END
  END head[27]
  PIN head[280]
    DIRECTION INPUT ;
    USE SIGNAL ;
    PORT
      LAYER M5 ;
        RECT  53.616 27.996 53.64 28.08 ;
    END
  END head[280]
  PIN head[281]
    DIRECTION INPUT ;
    USE SIGNAL ;
    PORT
      LAYER M5 ;
        RECT  53.712 27.996 53.736 28.08 ;
    END
  END head[281]
  PIN head[282]
    DIRECTION INPUT ;
    USE SIGNAL ;
    PORT
      LAYER M5 ;
        RECT  53.808 27.996 53.832 28.08 ;
    END
  END head[282]
  PIN head[283]
    DIRECTION INPUT ;
    USE SIGNAL ;
    PORT
      LAYER M5 ;
        RECT  53.904 27.996 53.928 28.08 ;
    END
  END head[283]
  PIN head[284]
    DIRECTION INPUT ;
    USE SIGNAL ;
    PORT
      LAYER M5 ;
        RECT  54 27.996 54.024 28.08 ;
    END
  END head[284]
  PIN head[285]
    DIRECTION INPUT ;
    USE SIGNAL ;
    PORT
      LAYER M5 ;
        RECT  54.096 27.996 54.12 28.08 ;
    END
  END head[285]
  PIN head[286]
    DIRECTION INPUT ;
    USE SIGNAL ;
    PORT
      LAYER M5 ;
        RECT  57.264 27.996 57.288 28.08 ;
    END
  END head[286]
  PIN head[287]
    DIRECTION INPUT ;
    USE SIGNAL ;
    PORT
      LAYER M5 ;
        RECT  57.36 27.996 57.384 28.08 ;
    END
  END head[287]
  PIN head[288]
    DIRECTION INPUT ;
    USE SIGNAL ;
    PORT
      LAYER M5 ;
        RECT  57.456 27.996 57.48 28.08 ;
    END
  END head[288]
  PIN head[289]
    DIRECTION INPUT ;
    USE SIGNAL ;
    PORT
      LAYER M5 ;
        RECT  57.552 27.996 57.576 28.08 ;
    END
  END head[289]
  PIN head[28]
    DIRECTION INPUT ;
    USE SIGNAL ;
    PORT
      LAYER M5 ;
        RECT  50.928 27.996 50.952 28.08 ;
    END
  END head[28]
  PIN head[290]
    DIRECTION INPUT ;
    USE SIGNAL ;
    PORT
      LAYER M5 ;
        RECT  57.648 27.996 57.672 28.08 ;
    END
  END head[290]
  PIN head[291]
    DIRECTION INPUT ;
    USE SIGNAL ;
    PORT
      LAYER M5 ;
        RECT  57.744 27.996 57.768 28.08 ;
    END
  END head[291]
  PIN head[292]
    DIRECTION INPUT ;
    USE SIGNAL ;
    PORT
      LAYER M5 ;
        RECT  57.84 27.996 57.864 28.08 ;
    END
  END head[292]
  PIN head[293]
    DIRECTION INPUT ;
    USE SIGNAL ;
    PORT
      LAYER M5 ;
        RECT  57.936 27.996 57.96 28.08 ;
    END
  END head[293]
  PIN head[294]
    DIRECTION INPUT ;
    USE SIGNAL ;
    PORT
      LAYER M5 ;
        RECT  58.032 27.996 58.056 28.08 ;
    END
  END head[294]
  PIN head[295]
    DIRECTION INPUT ;
    USE SIGNAL ;
    PORT
      LAYER M5 ;
        RECT  58.128 27.996 58.152 28.08 ;
    END
  END head[295]
  PIN head[296]
    DIRECTION INPUT ;
    USE SIGNAL ;
    PORT
      LAYER M5 ;
        RECT  58.224 27.996 58.248 28.08 ;
    END
  END head[296]
  PIN head[297]
    DIRECTION INPUT ;
    USE SIGNAL ;
    PORT
      LAYER M5 ;
        RECT  58.32 27.996 58.344 28.08 ;
    END
  END head[297]
  PIN head[298]
    DIRECTION INPUT ;
    USE SIGNAL ;
    PORT
      LAYER M5 ;
        RECT  58.416 27.996 58.44 28.08 ;
    END
  END head[298]
  PIN head[299]
    DIRECTION INPUT ;
    USE SIGNAL ;
    PORT
      LAYER M5 ;
        RECT  58.512 27.996 58.536 28.08 ;
    END
  END head[299]
  PIN head[29]
    DIRECTION INPUT ;
    USE SIGNAL ;
    PORT
      LAYER M5 ;
        RECT  51.024 27.996 51.048 28.08 ;
    END
  END head[29]
  PIN head[2]
    DIRECTION INPUT ;
    USE SIGNAL ;
    PORT
      LAYER M5 ;
        RECT  48.432 27.996 48.456 28.08 ;
    END
  END head[2]
  PIN head[300]
    DIRECTION INPUT ;
    USE SIGNAL ;
    PORT
      LAYER M5 ;
        RECT  58.608 27.996 58.632 28.08 ;
    END
  END head[300]
  PIN head[301]
    DIRECTION INPUT ;
    USE SIGNAL ;
    PORT
      LAYER M5 ;
        RECT  58.704 27.996 58.728 28.08 ;
    END
  END head[301]
  PIN head[302]
    DIRECTION INPUT ;
    USE SIGNAL ;
    PORT
      LAYER M5 ;
        RECT  58.8 27.996 58.824 28.08 ;
    END
  END head[302]
  PIN head[303]
    DIRECTION INPUT ;
    USE SIGNAL ;
    PORT
      LAYER M5 ;
        RECT  58.896 27.996 58.92 28.08 ;
    END
  END head[303]
  PIN head[304]
    DIRECTION INPUT ;
    USE SIGNAL ;
    PORT
      LAYER M5 ;
        RECT  58.992 27.996 59.016 28.08 ;
    END
  END head[304]
  PIN head[305]
    DIRECTION INPUT ;
    USE SIGNAL ;
    PORT
      LAYER M5 ;
        RECT  59.088 27.996 59.112 28.08 ;
    END
  END head[305]
  PIN head[306]
    DIRECTION INPUT ;
    USE SIGNAL ;
    PORT
      LAYER M5 ;
        RECT  59.184 27.996 59.208 28.08 ;
    END
  END head[306]
  PIN head[307]
    DIRECTION INPUT ;
    USE SIGNAL ;
    PORT
      LAYER M5 ;
        RECT  59.28 27.996 59.304 28.08 ;
    END
  END head[307]
  PIN head[308]
    DIRECTION INPUT ;
    USE SIGNAL ;
    PORT
      LAYER M5 ;
        RECT  59.376 27.996 59.4 28.08 ;
    END
  END head[308]
  PIN head[309]
    DIRECTION INPUT ;
    USE SIGNAL ;
    PORT
      LAYER M5 ;
        RECT  59.472 27.996 59.496 28.08 ;
    END
  END head[309]
  PIN head[30]
    DIRECTION INPUT ;
    USE SIGNAL ;
    PORT
      LAYER M5 ;
        RECT  60.336 27.996 60.36 28.08 ;
    END
  END head[30]
  PIN head[310]
    DIRECTION INPUT ;
    USE SIGNAL ;
    PORT
      LAYER M5 ;
        RECT  59.568 27.996 59.592 28.08 ;
    END
  END head[310]
  PIN head[311]
    DIRECTION INPUT ;
    USE SIGNAL ;
    PORT
      LAYER M5 ;
        RECT  59.664 27.996 59.688 28.08 ;
    END
  END head[311]
  PIN head[312]
    DIRECTION INPUT ;
    USE SIGNAL ;
    PORT
      LAYER M5 ;
        RECT  59.76 27.996 59.784 28.08 ;
    END
  END head[312]
  PIN head[313]
    DIRECTION INPUT ;
    USE SIGNAL ;
    PORT
      LAYER M5 ;
        RECT  59.856 27.996 59.88 28.08 ;
    END
  END head[313]
  PIN head[314]
    DIRECTION INPUT ;
    USE SIGNAL ;
    PORT
      LAYER M5 ;
        RECT  59.952 27.996 59.976 28.08 ;
    END
  END head[314]
  PIN head[315]
    DIRECTION INPUT ;
    USE SIGNAL ;
    PORT
      LAYER M5 ;
        RECT  60.048 27.996 60.072 28.08 ;
    END
  END head[315]
  PIN head[316]
    DIRECTION INPUT ;
    USE SIGNAL ;
    PORT
      LAYER M5 ;
        RECT  60.144 27.996 60.168 28.08 ;
    END
  END head[316]
  PIN head[317]
    DIRECTION INPUT ;
    USE SIGNAL ;
    PORT
      LAYER M5 ;
        RECT  60.24 27.996 60.264 28.08 ;
    END
  END head[317]
  PIN head[318]
    DIRECTION INPUT ;
    USE SIGNAL ;
    PORT
      LAYER M5 ;
        RECT  63.408 27.996 63.432 28.08 ;
    END
  END head[318]
  PIN head[319]
    DIRECTION INPUT ;
    USE SIGNAL ;
    PORT
      LAYER M5 ;
        RECT  63.504 27.996 63.528 28.08 ;
    END
  END head[319]
  PIN head[31]
    DIRECTION INPUT ;
    USE SIGNAL ;
    PORT
      LAYER M5 ;
        RECT  60.432 27.996 60.456 28.08 ;
    END
  END head[31]
  PIN head[320]
    DIRECTION INPUT ;
    USE SIGNAL ;
    PORT
      LAYER M5 ;
        RECT  63.6 27.996 63.624 28.08 ;
    END
  END head[320]
  PIN head[321]
    DIRECTION INPUT ;
    USE SIGNAL ;
    PORT
      LAYER M5 ;
        RECT  63.696 27.996 63.72 28.08 ;
    END
  END head[321]
  PIN head[322]
    DIRECTION INPUT ;
    USE SIGNAL ;
    PORT
      LAYER M5 ;
        RECT  63.792 27.996 63.816 28.08 ;
    END
  END head[322]
  PIN head[323]
    DIRECTION INPUT ;
    USE SIGNAL ;
    PORT
      LAYER M5 ;
        RECT  63.888 27.996 63.912 28.08 ;
    END
  END head[323]
  PIN head[324]
    DIRECTION INPUT ;
    USE SIGNAL ;
    PORT
      LAYER M5 ;
        RECT  63.984 27.996 64.008 28.08 ;
    END
  END head[324]
  PIN head[325]
    DIRECTION INPUT ;
    USE SIGNAL ;
    PORT
      LAYER M5 ;
        RECT  64.08 27.996 64.104 28.08 ;
    END
  END head[325]
  PIN head[326]
    DIRECTION INPUT ;
    USE SIGNAL ;
    PORT
      LAYER M5 ;
        RECT  64.176 27.996 64.2 28.08 ;
    END
  END head[326]
  PIN head[327]
    DIRECTION INPUT ;
    USE SIGNAL ;
    PORT
      LAYER M5 ;
        RECT  64.272 27.996 64.296 28.08 ;
    END
  END head[327]
  PIN head[328]
    DIRECTION INPUT ;
    USE SIGNAL ;
    PORT
      LAYER M5 ;
        RECT  64.368 27.996 64.392 28.08 ;
    END
  END head[328]
  PIN head[329]
    DIRECTION INPUT ;
    USE SIGNAL ;
    PORT
      LAYER M5 ;
        RECT  64.464 27.996 64.488 28.08 ;
    END
  END head[329]
  PIN head[32]
    DIRECTION INPUT ;
    USE SIGNAL ;
    PORT
      LAYER M5 ;
        RECT  60.528 27.996 60.552 28.08 ;
    END
  END head[32]
  PIN head[330]
    DIRECTION INPUT ;
    USE SIGNAL ;
    PORT
      LAYER M5 ;
        RECT  64.56 27.996 64.584 28.08 ;
    END
  END head[330]
  PIN head[331]
    DIRECTION INPUT ;
    USE SIGNAL ;
    PORT
      LAYER M5 ;
        RECT  64.656 27.996 64.68 28.08 ;
    END
  END head[331]
  PIN head[332]
    DIRECTION INPUT ;
    USE SIGNAL ;
    PORT
      LAYER M5 ;
        RECT  64.752 27.996 64.776 28.08 ;
    END
  END head[332]
  PIN head[333]
    DIRECTION INPUT ;
    USE SIGNAL ;
    PORT
      LAYER M5 ;
        RECT  64.848 27.996 64.872 28.08 ;
    END
  END head[333]
  PIN head[334]
    DIRECTION INPUT ;
    USE SIGNAL ;
    PORT
      LAYER M5 ;
        RECT  64.944 27.996 64.968 28.08 ;
    END
  END head[334]
  PIN head[335]
    DIRECTION INPUT ;
    USE SIGNAL ;
    PORT
      LAYER M5 ;
        RECT  65.04 27.996 65.064 28.08 ;
    END
  END head[335]
  PIN head[336]
    DIRECTION INPUT ;
    USE SIGNAL ;
    PORT
      LAYER M5 ;
        RECT  65.136 27.996 65.16 28.08 ;
    END
  END head[336]
  PIN head[337]
    DIRECTION INPUT ;
    USE SIGNAL ;
    PORT
      LAYER M5 ;
        RECT  65.232 27.996 65.256 28.08 ;
    END
  END head[337]
  PIN head[338]
    DIRECTION INPUT ;
    USE SIGNAL ;
    PORT
      LAYER M5 ;
        RECT  65.328 27.996 65.352 28.08 ;
    END
  END head[338]
  PIN head[339]
    DIRECTION INPUT ;
    USE SIGNAL ;
    PORT
      LAYER M5 ;
        RECT  65.424 27.996 65.448 28.08 ;
    END
  END head[339]
  PIN head[33]
    DIRECTION INPUT ;
    USE SIGNAL ;
    PORT
      LAYER M5 ;
        RECT  60.624 27.996 60.648 28.08 ;
    END
  END head[33]
  PIN head[340]
    DIRECTION INPUT ;
    USE SIGNAL ;
    PORT
      LAYER M5 ;
        RECT  65.52 27.996 65.544 28.08 ;
    END
  END head[340]
  PIN head[341]
    DIRECTION INPUT ;
    USE SIGNAL ;
    PORT
      LAYER M5 ;
        RECT  65.616 27.996 65.64 28.08 ;
    END
  END head[341]
  PIN head[342]
    DIRECTION INPUT ;
    USE SIGNAL ;
    PORT
      LAYER M5 ;
        RECT  65.712 27.996 65.736 28.08 ;
    END
  END head[342]
  PIN head[343]
    DIRECTION INPUT ;
    USE SIGNAL ;
    PORT
      LAYER M5 ;
        RECT  65.808 27.996 65.832 28.08 ;
    END
  END head[343]
  PIN head[344]
    DIRECTION INPUT ;
    USE SIGNAL ;
    PORT
      LAYER M5 ;
        RECT  65.904 27.996 65.928 28.08 ;
    END
  END head[344]
  PIN head[345]
    DIRECTION INPUT ;
    USE SIGNAL ;
    PORT
      LAYER M5 ;
        RECT  66 27.996 66.024 28.08 ;
    END
  END head[345]
  PIN head[346]
    DIRECTION INPUT ;
    USE SIGNAL ;
    PORT
      LAYER M5 ;
        RECT  66.096 27.996 66.12 28.08 ;
    END
  END head[346]
  PIN head[347]
    DIRECTION INPUT ;
    USE SIGNAL ;
    PORT
      LAYER M5 ;
        RECT  66.192 27.996 66.216 28.08 ;
    END
  END head[347]
  PIN head[348]
    DIRECTION INPUT ;
    USE SIGNAL ;
    PORT
      LAYER M5 ;
        RECT  66.288 27.996 66.312 28.08 ;
    END
  END head[348]
  PIN head[349]
    DIRECTION INPUT ;
    USE SIGNAL ;
    PORT
      LAYER M5 ;
        RECT  66.384 27.996 66.408 28.08 ;
    END
  END head[349]
  PIN head[34]
    DIRECTION INPUT ;
    USE SIGNAL ;
    PORT
      LAYER M5 ;
        RECT  60.72 27.996 60.744 28.08 ;
    END
  END head[34]
  PIN head[350]
    DIRECTION INPUT ;
    USE SIGNAL ;
    PORT
      LAYER M5 ;
        RECT  44.208 27.996 44.232 28.08 ;
    END
  END head[350]
  PIN head[351]
    DIRECTION INPUT ;
    USE SIGNAL ;
    PORT
      LAYER M5 ;
        RECT  44.304 27.996 44.328 28.08 ;
    END
  END head[351]
  PIN head[352]
    DIRECTION INPUT ;
    USE SIGNAL ;
    PORT
      LAYER M5 ;
        RECT  44.4 27.996 44.424 28.08 ;
    END
  END head[352]
  PIN head[353]
    DIRECTION INPUT ;
    USE SIGNAL ;
    PORT
      LAYER M5 ;
        RECT  44.496 27.996 44.52 28.08 ;
    END
  END head[353]
  PIN head[354]
    DIRECTION INPUT ;
    USE SIGNAL ;
    PORT
      LAYER M5 ;
        RECT  44.592 27.996 44.616 28.08 ;
    END
  END head[354]
  PIN head[355]
    DIRECTION INPUT ;
    USE SIGNAL ;
    PORT
      LAYER M5 ;
        RECT  44.688 27.996 44.712 28.08 ;
    END
  END head[355]
  PIN head[356]
    DIRECTION INPUT ;
    USE SIGNAL ;
    PORT
      LAYER M5 ;
        RECT  44.784 27.996 44.808 28.08 ;
    END
  END head[356]
  PIN head[357]
    DIRECTION INPUT ;
    USE SIGNAL ;
    PORT
      LAYER M5 ;
        RECT  44.88 27.996 44.904 28.08 ;
    END
  END head[357]
  PIN head[358]
    DIRECTION INPUT ;
    USE SIGNAL ;
    PORT
      LAYER M5 ;
        RECT  44.976 27.996 45 28.08 ;
    END
  END head[358]
  PIN head[359]
    DIRECTION INPUT ;
    USE SIGNAL ;
    PORT
      LAYER M5 ;
        RECT  45.072 27.996 45.096 28.08 ;
    END
  END head[359]
  PIN head[35]
    DIRECTION INPUT ;
    USE SIGNAL ;
    PORT
      LAYER M5 ;
        RECT  60.816 27.996 60.84 28.08 ;
    END
  END head[35]
  PIN head[360]
    DIRECTION INPUT ;
    USE SIGNAL ;
    PORT
      LAYER M5 ;
        RECT  45.168 27.996 45.192 28.08 ;
    END
  END head[360]
  PIN head[361]
    DIRECTION INPUT ;
    USE SIGNAL ;
    PORT
      LAYER M5 ;
        RECT  45.264 27.996 45.288 28.08 ;
    END
  END head[361]
  PIN head[362]
    DIRECTION INPUT ;
    USE SIGNAL ;
    PORT
      LAYER M5 ;
        RECT  45.36 27.996 45.384 28.08 ;
    END
  END head[362]
  PIN head[363]
    DIRECTION INPUT ;
    USE SIGNAL ;
    PORT
      LAYER M5 ;
        RECT  45.456 27.996 45.48 28.08 ;
    END
  END head[363]
  PIN head[364]
    DIRECTION INPUT ;
    USE SIGNAL ;
    PORT
      LAYER M5 ;
        RECT  45.552 27.996 45.576 28.08 ;
    END
  END head[364]
  PIN head[365]
    DIRECTION INPUT ;
    USE SIGNAL ;
    PORT
      LAYER M5 ;
        RECT  45.648 27.996 45.672 28.08 ;
    END
  END head[365]
  PIN head[366]
    DIRECTION INPUT ;
    USE SIGNAL ;
    PORT
      LAYER M5 ;
        RECT  45.744 27.996 45.768 28.08 ;
    END
  END head[366]
  PIN head[367]
    DIRECTION INPUT ;
    USE SIGNAL ;
    PORT
      LAYER M5 ;
        RECT  45.84 27.996 45.864 28.08 ;
    END
  END head[367]
  PIN head[368]
    DIRECTION INPUT ;
    USE SIGNAL ;
    PORT
      LAYER M5 ;
        RECT  45.936 27.996 45.96 28.08 ;
    END
  END head[368]
  PIN head[369]
    DIRECTION INPUT ;
    USE SIGNAL ;
    PORT
      LAYER M5 ;
        RECT  46.032 27.996 46.056 28.08 ;
    END
  END head[369]
  PIN head[36]
    DIRECTION INPUT ;
    USE SIGNAL ;
    PORT
      LAYER M5 ;
        RECT  60.912 27.996 60.936 28.08 ;
    END
  END head[36]
  PIN head[370]
    DIRECTION INPUT ;
    USE SIGNAL ;
    PORT
      LAYER M5 ;
        RECT  46.128 27.996 46.152 28.08 ;
    END
  END head[370]
  PIN head[371]
    DIRECTION INPUT ;
    USE SIGNAL ;
    PORT
      LAYER M5 ;
        RECT  46.224 27.996 46.248 28.08 ;
    END
  END head[371]
  PIN head[372]
    DIRECTION INPUT ;
    USE SIGNAL ;
    PORT
      LAYER M5 ;
        RECT  46.32 27.996 46.344 28.08 ;
    END
  END head[372]
  PIN head[373]
    DIRECTION INPUT ;
    USE SIGNAL ;
    PORT
      LAYER M5 ;
        RECT  46.416 27.996 46.44 28.08 ;
    END
  END head[373]
  PIN head[374]
    DIRECTION INPUT ;
    USE SIGNAL ;
    PORT
      LAYER M5 ;
        RECT  46.512 27.996 46.536 28.08 ;
    END
  END head[374]
  PIN head[375]
    DIRECTION INPUT ;
    USE SIGNAL ;
    PORT
      LAYER M5 ;
        RECT  46.608 27.996 46.632 28.08 ;
    END
  END head[375]
  PIN head[376]
    DIRECTION INPUT ;
    USE SIGNAL ;
    PORT
      LAYER M5 ;
        RECT  46.704 27.996 46.728 28.08 ;
    END
  END head[376]
  PIN head[377]
    DIRECTION INPUT ;
    USE SIGNAL ;
    PORT
      LAYER M5 ;
        RECT  46.8 27.996 46.824 28.08 ;
    END
  END head[377]
  PIN head[378]
    DIRECTION INPUT ;
    USE SIGNAL ;
    PORT
      LAYER M5 ;
        RECT  46.896 27.996 46.92 28.08 ;
    END
  END head[378]
  PIN head[379]
    DIRECTION INPUT ;
    USE SIGNAL ;
    PORT
      LAYER M5 ;
        RECT  46.992 27.996 47.016 28.08 ;
    END
  END head[379]
  PIN head[37]
    DIRECTION INPUT ;
    USE SIGNAL ;
    PORT
      LAYER M5 ;
        RECT  61.008 27.996 61.032 28.08 ;
    END
  END head[37]
  PIN head[380]
    DIRECTION INPUT ;
    USE SIGNAL ;
    PORT
      LAYER M5 ;
        RECT  47.088 27.996 47.112 28.08 ;
    END
  END head[380]
  PIN head[381]
    DIRECTION INPUT ;
    USE SIGNAL ;
    PORT
      LAYER M5 ;
        RECT  47.184 27.996 47.208 28.08 ;
    END
  END head[381]
  PIN head[382]
    DIRECTION INPUT ;
    USE SIGNAL ;
    PORT
      LAYER M5 ;
        RECT  15.792 27.996 15.816 28.08 ;
    END
  END head[382]
  PIN head[383]
    DIRECTION INPUT ;
    USE SIGNAL ;
    PORT
      LAYER M5 ;
        RECT  15.888 27.996 15.912 28.08 ;
    END
  END head[383]
  PIN head[384]
    DIRECTION INPUT ;
    USE SIGNAL ;
    PORT
      LAYER M5 ;
        RECT  15.984 27.996 16.008 28.08 ;
    END
  END head[384]
  PIN head[385]
    DIRECTION INPUT ;
    USE SIGNAL ;
    PORT
      LAYER M5 ;
        RECT  16.08 27.996 16.104 28.08 ;
    END
  END head[385]
  PIN head[386]
    DIRECTION INPUT ;
    USE SIGNAL ;
    PORT
      LAYER M5 ;
        RECT  16.176 27.996 16.2 28.08 ;
    END
  END head[386]
  PIN head[387]
    DIRECTION INPUT ;
    USE SIGNAL ;
    PORT
      LAYER M5 ;
        RECT  16.272 27.996 16.296 28.08 ;
    END
  END head[387]
  PIN head[388]
    DIRECTION INPUT ;
    USE SIGNAL ;
    PORT
      LAYER M5 ;
        RECT  16.368 27.996 16.392 28.08 ;
    END
  END head[388]
  PIN head[389]
    DIRECTION INPUT ;
    USE SIGNAL ;
    PORT
      LAYER M5 ;
        RECT  16.464 27.996 16.488 28.08 ;
    END
  END head[389]
  PIN head[38]
    DIRECTION INPUT ;
    USE SIGNAL ;
    PORT
      LAYER M5 ;
        RECT  61.104 27.996 61.128 28.08 ;
    END
  END head[38]
  PIN head[390]
    DIRECTION INPUT ;
    USE SIGNAL ;
    PORT
      LAYER M5 ;
        RECT  16.56 27.996 16.584 28.08 ;
    END
  END head[390]
  PIN head[391]
    DIRECTION INPUT ;
    USE SIGNAL ;
    PORT
      LAYER M5 ;
        RECT  16.656 27.996 16.68 28.08 ;
    END
  END head[391]
  PIN head[392]
    DIRECTION INPUT ;
    USE SIGNAL ;
    PORT
      LAYER M5 ;
        RECT  16.752 27.996 16.776 28.08 ;
    END
  END head[392]
  PIN head[393]
    DIRECTION INPUT ;
    USE SIGNAL ;
    PORT
      LAYER M5 ;
        RECT  16.848 27.996 16.872 28.08 ;
    END
  END head[393]
  PIN head[394]
    DIRECTION INPUT ;
    USE SIGNAL ;
    PORT
      LAYER M5 ;
        RECT  16.944 27.996 16.968 28.08 ;
    END
  END head[394]
  PIN head[395]
    DIRECTION INPUT ;
    USE SIGNAL ;
    PORT
      LAYER M5 ;
        RECT  17.04 27.996 17.064 28.08 ;
    END
  END head[395]
  PIN head[396]
    DIRECTION INPUT ;
    USE SIGNAL ;
    PORT
      LAYER M5 ;
        RECT  17.136 27.996 17.16 28.08 ;
    END
  END head[396]
  PIN head[397]
    DIRECTION INPUT ;
    USE SIGNAL ;
    PORT
      LAYER M5 ;
        RECT  17.232 27.996 17.256 28.08 ;
    END
  END head[397]
  PIN head[398]
    DIRECTION INPUT ;
    USE SIGNAL ;
    PORT
      LAYER M5 ;
        RECT  17.328 27.996 17.352 28.08 ;
    END
  END head[398]
  PIN head[399]
    DIRECTION INPUT ;
    USE SIGNAL ;
    PORT
      LAYER M5 ;
        RECT  17.424 27.996 17.448 28.08 ;
    END
  END head[399]
  PIN head[39]
    DIRECTION INPUT ;
    USE SIGNAL ;
    PORT
      LAYER M5 ;
        RECT  61.2 27.996 61.224 28.08 ;
    END
  END head[39]
  PIN head[3]
    DIRECTION INPUT ;
    USE SIGNAL ;
    PORT
      LAYER M5 ;
        RECT  48.528 27.996 48.552 28.08 ;
    END
  END head[3]
  PIN head[400]
    DIRECTION INPUT ;
    USE SIGNAL ;
    PORT
      LAYER M5 ;
        RECT  17.52 27.996 17.544 28.08 ;
    END
  END head[400]
  PIN head[401]
    DIRECTION INPUT ;
    USE SIGNAL ;
    PORT
      LAYER M5 ;
        RECT  17.616 27.996 17.64 28.08 ;
    END
  END head[401]
  PIN head[402]
    DIRECTION INPUT ;
    USE SIGNAL ;
    PORT
      LAYER M5 ;
        RECT  17.712 27.996 17.736 28.08 ;
    END
  END head[402]
  PIN head[403]
    DIRECTION INPUT ;
    USE SIGNAL ;
    PORT
      LAYER M5 ;
        RECT  17.808 27.996 17.832 28.08 ;
    END
  END head[403]
  PIN head[404]
    DIRECTION INPUT ;
    USE SIGNAL ;
    PORT
      LAYER M5 ;
        RECT  17.904 27.996 17.928 28.08 ;
    END
  END head[404]
  PIN head[405]
    DIRECTION INPUT ;
    USE SIGNAL ;
    PORT
      LAYER M5 ;
        RECT  18 27.996 18.024 28.08 ;
    END
  END head[405]
  PIN head[406]
    DIRECTION INPUT ;
    USE SIGNAL ;
    PORT
      LAYER M5 ;
        RECT  18.096 27.996 18.12 28.08 ;
    END
  END head[406]
  PIN head[407]
    DIRECTION INPUT ;
    USE SIGNAL ;
    PORT
      LAYER M5 ;
        RECT  18.192 27.996 18.216 28.08 ;
    END
  END head[407]
  PIN head[408]
    DIRECTION INPUT ;
    USE SIGNAL ;
    PORT
      LAYER M5 ;
        RECT  18.288 27.996 18.312 28.08 ;
    END
  END head[408]
  PIN head[409]
    DIRECTION INPUT ;
    USE SIGNAL ;
    PORT
      LAYER M5 ;
        RECT  18.384 27.996 18.408 28.08 ;
    END
  END head[409]
  PIN head[40]
    DIRECTION INPUT ;
    USE SIGNAL ;
    PORT
      LAYER M5 ;
        RECT  61.296 27.996 61.32 28.08 ;
    END
  END head[40]
  PIN head[410]
    DIRECTION INPUT ;
    USE SIGNAL ;
    PORT
      LAYER M5 ;
        RECT  18.48 27.996 18.504 28.08 ;
    END
  END head[410]
  PIN head[411]
    DIRECTION INPUT ;
    USE SIGNAL ;
    PORT
      LAYER M5 ;
        RECT  18.576 27.996 18.6 28.08 ;
    END
  END head[411]
  PIN head[412]
    DIRECTION INPUT ;
    USE SIGNAL ;
    PORT
      LAYER M5 ;
        RECT  18.672 27.996 18.696 28.08 ;
    END
  END head[412]
  PIN head[413]
    DIRECTION INPUT ;
    USE SIGNAL ;
    PORT
      LAYER M5 ;
        RECT  18.768 27.996 18.792 28.08 ;
    END
  END head[413]
  PIN head[414]
    DIRECTION INPUT ;
    USE SIGNAL ;
    PORT
      LAYER M5 ;
        RECT  18.864 27.996 18.888 28.08 ;
    END
  END head[414]
  PIN head[415]
    DIRECTION INPUT ;
    USE SIGNAL ;
    PORT
      LAYER M5 ;
        RECT  18.96 27.996 18.984 28.08 ;
    END
  END head[415]
  PIN head[416]
    DIRECTION INPUT ;
    USE SIGNAL ;
    PORT
      LAYER M5 ;
        RECT  19.056 27.996 19.08 28.08 ;
    END
  END head[416]
  PIN head[417]
    DIRECTION INPUT ;
    USE SIGNAL ;
    PORT
      LAYER M5 ;
        RECT  19.152 27.996 19.176 28.08 ;
    END
  END head[417]
  PIN head[418]
    DIRECTION INPUT ;
    USE SIGNAL ;
    PORT
      LAYER M5 ;
        RECT  19.248 27.996 19.272 28.08 ;
    END
  END head[418]
  PIN head[419]
    DIRECTION INPUT ;
    USE SIGNAL ;
    PORT
      LAYER M5 ;
        RECT  19.344 27.996 19.368 28.08 ;
    END
  END head[419]
  PIN head[41]
    DIRECTION INPUT ;
    USE SIGNAL ;
    PORT
      LAYER M5 ;
        RECT  61.392 27.996 61.416 28.08 ;
    END
  END head[41]
  PIN head[420]
    DIRECTION INPUT ;
    USE SIGNAL ;
    PORT
      LAYER M5 ;
        RECT  19.44 27.996 19.464 28.08 ;
    END
  END head[420]
  PIN head[421]
    DIRECTION INPUT ;
    USE SIGNAL ;
    PORT
      LAYER M5 ;
        RECT  19.536 27.996 19.56 28.08 ;
    END
  END head[421]
  PIN head[422]
    DIRECTION INPUT ;
    USE SIGNAL ;
    PORT
      LAYER M5 ;
        RECT  19.632 27.996 19.656 28.08 ;
    END
  END head[422]
  PIN head[423]
    DIRECTION INPUT ;
    USE SIGNAL ;
    PORT
      LAYER M5 ;
        RECT  19.728 27.996 19.752 28.08 ;
    END
  END head[423]
  PIN head[424]
    DIRECTION INPUT ;
    USE SIGNAL ;
    PORT
      LAYER M5 ;
        RECT  19.824 27.996 19.848 28.08 ;
    END
  END head[424]
  PIN head[425]
    DIRECTION INPUT ;
    USE SIGNAL ;
    PORT
      LAYER M5 ;
        RECT  19.92 27.996 19.944 28.08 ;
    END
  END head[425]
  PIN head[426]
    DIRECTION INPUT ;
    USE SIGNAL ;
    PORT
      LAYER M5 ;
        RECT  20.016 27.996 20.04 28.08 ;
    END
  END head[426]
  PIN head[427]
    DIRECTION INPUT ;
    USE SIGNAL ;
    PORT
      LAYER M5 ;
        RECT  20.112 27.996 20.136 28.08 ;
    END
  END head[427]
  PIN head[428]
    DIRECTION INPUT ;
    USE SIGNAL ;
    PORT
      LAYER M5 ;
        RECT  20.208 27.996 20.232 28.08 ;
    END
  END head[428]
  PIN head[429]
    DIRECTION INPUT ;
    USE SIGNAL ;
    PORT
      LAYER M5 ;
        RECT  20.304 27.996 20.328 28.08 ;
    END
  END head[429]
  PIN head[42]
    DIRECTION INPUT ;
    USE SIGNAL ;
    PORT
      LAYER M5 ;
        RECT  61.488 27.996 61.512 28.08 ;
    END
  END head[42]
  PIN head[430]
    DIRECTION INPUT ;
    USE SIGNAL ;
    PORT
      LAYER M5 ;
        RECT  20.4 27.996 20.424 28.08 ;
    END
  END head[430]
  PIN head[431]
    DIRECTION INPUT ;
    USE SIGNAL ;
    PORT
      LAYER M5 ;
        RECT  20.496 27.996 20.52 28.08 ;
    END
  END head[431]
  PIN head[432]
    DIRECTION INPUT ;
    USE SIGNAL ;
    PORT
      LAYER M5 ;
        RECT  20.592 27.996 20.616 28.08 ;
    END
  END head[432]
  PIN head[433]
    DIRECTION INPUT ;
    USE SIGNAL ;
    PORT
      LAYER M5 ;
        RECT  20.688 27.996 20.712 28.08 ;
    END
  END head[433]
  PIN head[434]
    DIRECTION INPUT ;
    USE SIGNAL ;
    PORT
      LAYER M5 ;
        RECT  20.784 27.996 20.808 28.08 ;
    END
  END head[434]
  PIN head[435]
    DIRECTION INPUT ;
    USE SIGNAL ;
    PORT
      LAYER M5 ;
        RECT  20.88 27.996 20.904 28.08 ;
    END
  END head[435]
  PIN head[436]
    DIRECTION INPUT ;
    USE SIGNAL ;
    PORT
      LAYER M5 ;
        RECT  20.976 27.996 21 28.08 ;
    END
  END head[436]
  PIN head[437]
    DIRECTION INPUT ;
    USE SIGNAL ;
    PORT
      LAYER M5 ;
        RECT  21.072 27.996 21.096 28.08 ;
    END
  END head[437]
  PIN head[438]
    DIRECTION INPUT ;
    USE SIGNAL ;
    PORT
      LAYER M5 ;
        RECT  21.168 27.996 21.192 28.08 ;
    END
  END head[438]
  PIN head[439]
    DIRECTION INPUT ;
    USE SIGNAL ;
    PORT
      LAYER M5 ;
        RECT  21.264 27.996 21.288 28.08 ;
    END
  END head[439]
  PIN head[43]
    DIRECTION INPUT ;
    USE SIGNAL ;
    PORT
      LAYER M5 ;
        RECT  61.584 27.996 61.608 28.08 ;
    END
  END head[43]
  PIN head[440]
    DIRECTION INPUT ;
    USE SIGNAL ;
    PORT
      LAYER M5 ;
        RECT  21.36 27.996 21.384 28.08 ;
    END
  END head[440]
  PIN head[441]
    DIRECTION INPUT ;
    USE SIGNAL ;
    PORT
      LAYER M5 ;
        RECT  21.456 27.996 21.48 28.08 ;
    END
  END head[441]
  PIN head[442]
    DIRECTION INPUT ;
    USE SIGNAL ;
    PORT
      LAYER M5 ;
        RECT  21.552 27.996 21.576 28.08 ;
    END
  END head[442]
  PIN head[443]
    DIRECTION INPUT ;
    USE SIGNAL ;
    PORT
      LAYER M5 ;
        RECT  21.648 27.996 21.672 28.08 ;
    END
  END head[443]
  PIN head[444]
    DIRECTION INPUT ;
    USE SIGNAL ;
    PORT
      LAYER M5 ;
        RECT  21.744 27.996 21.768 28.08 ;
    END
  END head[444]
  PIN head[445]
    DIRECTION INPUT ;
    USE SIGNAL ;
    PORT
      LAYER M5 ;
        RECT  21.84 27.996 21.864 28.08 ;
    END
  END head[445]
  PIN head[446]
    DIRECTION INPUT ;
    USE SIGNAL ;
    PORT
      LAYER M5 ;
        RECT  25.008 27.996 25.032 28.08 ;
    END
  END head[446]
  PIN head[447]
    DIRECTION INPUT ;
    USE SIGNAL ;
    PORT
      LAYER M5 ;
        RECT  25.104 27.996 25.128 28.08 ;
    END
  END head[447]
  PIN head[448]
    DIRECTION INPUT ;
    USE SIGNAL ;
    PORT
      LAYER M5 ;
        RECT  25.2 27.996 25.224 28.08 ;
    END
  END head[448]
  PIN head[449]
    DIRECTION INPUT ;
    USE SIGNAL ;
    PORT
      LAYER M5 ;
        RECT  25.296 27.996 25.32 28.08 ;
    END
  END head[449]
  PIN head[44]
    DIRECTION INPUT ;
    USE SIGNAL ;
    PORT
      LAYER M5 ;
        RECT  61.68 27.996 61.704 28.08 ;
    END
  END head[44]
  PIN head[450]
    DIRECTION INPUT ;
    USE SIGNAL ;
    PORT
      LAYER M5 ;
        RECT  25.392 27.996 25.416 28.08 ;
    END
  END head[450]
  PIN head[451]
    DIRECTION INPUT ;
    USE SIGNAL ;
    PORT
      LAYER M5 ;
        RECT  25.488 27.996 25.512 28.08 ;
    END
  END head[451]
  PIN head[452]
    DIRECTION INPUT ;
    USE SIGNAL ;
    PORT
      LAYER M5 ;
        RECT  25.584 27.996 25.608 28.08 ;
    END
  END head[452]
  PIN head[453]
    DIRECTION INPUT ;
    USE SIGNAL ;
    PORT
      LAYER M5 ;
        RECT  25.68 27.996 25.704 28.08 ;
    END
  END head[453]
  PIN head[454]
    DIRECTION INPUT ;
    USE SIGNAL ;
    PORT
      LAYER M5 ;
        RECT  25.776 27.996 25.8 28.08 ;
    END
  END head[454]
  PIN head[455]
    DIRECTION INPUT ;
    USE SIGNAL ;
    PORT
      LAYER M5 ;
        RECT  25.872 27.996 25.896 28.08 ;
    END
  END head[455]
  PIN head[456]
    DIRECTION INPUT ;
    USE SIGNAL ;
    PORT
      LAYER M5 ;
        RECT  25.968 27.996 25.992 28.08 ;
    END
  END head[456]
  PIN head[457]
    DIRECTION INPUT ;
    USE SIGNAL ;
    PORT
      LAYER M5 ;
        RECT  26.064 27.996 26.088 28.08 ;
    END
  END head[457]
  PIN head[458]
    DIRECTION INPUT ;
    USE SIGNAL ;
    PORT
      LAYER M5 ;
        RECT  26.16 27.996 26.184 28.08 ;
    END
  END head[458]
  PIN head[459]
    DIRECTION INPUT ;
    USE SIGNAL ;
    PORT
      LAYER M5 ;
        RECT  26.256 27.996 26.28 28.08 ;
    END
  END head[459]
  PIN head[45]
    DIRECTION INPUT ;
    USE SIGNAL ;
    PORT
      LAYER M5 ;
        RECT  61.776 27.996 61.8 28.08 ;
    END
  END head[45]
  PIN head[460]
    DIRECTION INPUT ;
    USE SIGNAL ;
    PORT
      LAYER M5 ;
        RECT  26.352 27.996 26.376 28.08 ;
    END
  END head[460]
  PIN head[461]
    DIRECTION INPUT ;
    USE SIGNAL ;
    PORT
      LAYER M5 ;
        RECT  26.448 27.996 26.472 28.08 ;
    END
  END head[461]
  PIN head[462]
    DIRECTION INPUT ;
    USE SIGNAL ;
    PORT
      LAYER M5 ;
        RECT  26.544 27.996 26.568 28.08 ;
    END
  END head[462]
  PIN head[463]
    DIRECTION INPUT ;
    USE SIGNAL ;
    PORT
      LAYER M5 ;
        RECT  26.64 27.996 26.664 28.08 ;
    END
  END head[463]
  PIN head[464]
    DIRECTION INPUT ;
    USE SIGNAL ;
    PORT
      LAYER M5 ;
        RECT  26.736 27.996 26.76 28.08 ;
    END
  END head[464]
  PIN head[465]
    DIRECTION INPUT ;
    USE SIGNAL ;
    PORT
      LAYER M5 ;
        RECT  26.832 27.996 26.856 28.08 ;
    END
  END head[465]
  PIN head[466]
    DIRECTION INPUT ;
    USE SIGNAL ;
    PORT
      LAYER M5 ;
        RECT  26.928 27.996 26.952 28.08 ;
    END
  END head[466]
  PIN head[467]
    DIRECTION INPUT ;
    USE SIGNAL ;
    PORT
      LAYER M5 ;
        RECT  27.024 27.996 27.048 28.08 ;
    END
  END head[467]
  PIN head[468]
    DIRECTION INPUT ;
    USE SIGNAL ;
    PORT
      LAYER M5 ;
        RECT  27.12 27.996 27.144 28.08 ;
    END
  END head[468]
  PIN head[469]
    DIRECTION INPUT ;
    USE SIGNAL ;
    PORT
      LAYER M5 ;
        RECT  27.216 27.996 27.24 28.08 ;
    END
  END head[469]
  PIN head[46]
    DIRECTION INPUT ;
    USE SIGNAL ;
    PORT
      LAYER M5 ;
        RECT  61.872 27.996 61.896 28.08 ;
    END
  END head[46]
  PIN head[470]
    DIRECTION INPUT ;
    USE SIGNAL ;
    PORT
      LAYER M5 ;
        RECT  27.312 27.996 27.336 28.08 ;
    END
  END head[470]
  PIN head[471]
    DIRECTION INPUT ;
    USE SIGNAL ;
    PORT
      LAYER M5 ;
        RECT  27.408 27.996 27.432 28.08 ;
    END
  END head[471]
  PIN head[472]
    DIRECTION INPUT ;
    USE SIGNAL ;
    PORT
      LAYER M5 ;
        RECT  27.504 27.996 27.528 28.08 ;
    END
  END head[472]
  PIN head[473]
    DIRECTION INPUT ;
    USE SIGNAL ;
    PORT
      LAYER M5 ;
        RECT  27.6 27.996 27.624 28.08 ;
    END
  END head[473]
  PIN head[474]
    DIRECTION INPUT ;
    USE SIGNAL ;
    PORT
      LAYER M5 ;
        RECT  27.696 27.996 27.72 28.08 ;
    END
  END head[474]
  PIN head[475]
    DIRECTION INPUT ;
    USE SIGNAL ;
    PORT
      LAYER M5 ;
        RECT  27.792 27.996 27.816 28.08 ;
    END
  END head[475]
  PIN head[476]
    DIRECTION INPUT ;
    USE SIGNAL ;
    PORT
      LAYER M5 ;
        RECT  27.888 27.996 27.912 28.08 ;
    END
  END head[476]
  PIN head[477]
    DIRECTION INPUT ;
    USE SIGNAL ;
    PORT
      LAYER M5 ;
        RECT  27.984 27.996 28.008 28.08 ;
    END
  END head[477]
  PIN head[478]
    DIRECTION INPUT ;
    USE SIGNAL ;
    PORT
      LAYER M5 ;
        RECT  21.936 27.996 21.96 28.08 ;
    END
  END head[478]
  PIN head[479]
    DIRECTION INPUT ;
    USE SIGNAL ;
    PORT
      LAYER M5 ;
        RECT  22.032 27.996 22.056 28.08 ;
    END
  END head[479]
  PIN head[47]
    DIRECTION INPUT ;
    USE SIGNAL ;
    PORT
      LAYER M5 ;
        RECT  61.968 27.996 61.992 28.08 ;
    END
  END head[47]
  PIN head[480]
    DIRECTION INPUT ;
    USE SIGNAL ;
    PORT
      LAYER M5 ;
        RECT  22.128 27.996 22.152 28.08 ;
    END
  END head[480]
  PIN head[481]
    DIRECTION INPUT ;
    USE SIGNAL ;
    PORT
      LAYER M5 ;
        RECT  22.224 27.996 22.248 28.08 ;
    END
  END head[481]
  PIN head[482]
    DIRECTION INPUT ;
    USE SIGNAL ;
    PORT
      LAYER M5 ;
        RECT  22.32 27.996 22.344 28.08 ;
    END
  END head[482]
  PIN head[483]
    DIRECTION INPUT ;
    USE SIGNAL ;
    PORT
      LAYER M5 ;
        RECT  22.416 27.996 22.44 28.08 ;
    END
  END head[483]
  PIN head[484]
    DIRECTION INPUT ;
    USE SIGNAL ;
    PORT
      LAYER M5 ;
        RECT  22.512 27.996 22.536 28.08 ;
    END
  END head[484]
  PIN head[485]
    DIRECTION INPUT ;
    USE SIGNAL ;
    PORT
      LAYER M5 ;
        RECT  22.608 27.996 22.632 28.08 ;
    END
  END head[485]
  PIN head[486]
    DIRECTION INPUT ;
    USE SIGNAL ;
    PORT
      LAYER M5 ;
        RECT  22.704 27.996 22.728 28.08 ;
    END
  END head[486]
  PIN head[487]
    DIRECTION INPUT ;
    USE SIGNAL ;
    PORT
      LAYER M5 ;
        RECT  22.8 27.996 22.824 28.08 ;
    END
  END head[487]
  PIN head[488]
    DIRECTION INPUT ;
    USE SIGNAL ;
    PORT
      LAYER M5 ;
        RECT  22.896 27.996 22.92 28.08 ;
    END
  END head[488]
  PIN head[489]
    DIRECTION INPUT ;
    USE SIGNAL ;
    PORT
      LAYER M5 ;
        RECT  22.992 27.996 23.016 28.08 ;
    END
  END head[489]
  PIN head[48]
    DIRECTION INPUT ;
    USE SIGNAL ;
    PORT
      LAYER M5 ;
        RECT  62.064 27.996 62.088 28.08 ;
    END
  END head[48]
  PIN head[490]
    DIRECTION INPUT ;
    USE SIGNAL ;
    PORT
      LAYER M5 ;
        RECT  23.088 27.996 23.112 28.08 ;
    END
  END head[490]
  PIN head[491]
    DIRECTION INPUT ;
    USE SIGNAL ;
    PORT
      LAYER M5 ;
        RECT  23.184 27.996 23.208 28.08 ;
    END
  END head[491]
  PIN head[492]
    DIRECTION INPUT ;
    USE SIGNAL ;
    PORT
      LAYER M5 ;
        RECT  23.28 27.996 23.304 28.08 ;
    END
  END head[492]
  PIN head[493]
    DIRECTION INPUT ;
    USE SIGNAL ;
    PORT
      LAYER M5 ;
        RECT  23.376 27.996 23.4 28.08 ;
    END
  END head[493]
  PIN head[494]
    DIRECTION INPUT ;
    USE SIGNAL ;
    PORT
      LAYER M5 ;
        RECT  23.472 27.996 23.496 28.08 ;
    END
  END head[494]
  PIN head[495]
    DIRECTION INPUT ;
    USE SIGNAL ;
    PORT
      LAYER M5 ;
        RECT  23.568 27.996 23.592 28.08 ;
    END
  END head[495]
  PIN head[496]
    DIRECTION INPUT ;
    USE SIGNAL ;
    PORT
      LAYER M5 ;
        RECT  23.664 27.996 23.688 28.08 ;
    END
  END head[496]
  PIN head[497]
    DIRECTION INPUT ;
    USE SIGNAL ;
    PORT
      LAYER M5 ;
        RECT  23.76 27.996 23.784 28.08 ;
    END
  END head[497]
  PIN head[498]
    DIRECTION INPUT ;
    USE SIGNAL ;
    PORT
      LAYER M5 ;
        RECT  23.856 27.996 23.88 28.08 ;
    END
  END head[498]
  PIN head[499]
    DIRECTION INPUT ;
    USE SIGNAL ;
    PORT
      LAYER M5 ;
        RECT  23.952 27.996 23.976 28.08 ;
    END
  END head[499]
  PIN head[49]
    DIRECTION INPUT ;
    USE SIGNAL ;
    PORT
      LAYER M5 ;
        RECT  62.16 27.996 62.184 28.08 ;
    END
  END head[49]
  PIN head[4]
    DIRECTION INPUT ;
    USE SIGNAL ;
    PORT
      LAYER M5 ;
        RECT  48.624 27.996 48.648 28.08 ;
    END
  END head[4]
  PIN head[500]
    DIRECTION INPUT ;
    USE SIGNAL ;
    PORT
      LAYER M5 ;
        RECT  24.048 27.996 24.072 28.08 ;
    END
  END head[500]
  PIN head[501]
    DIRECTION INPUT ;
    USE SIGNAL ;
    PORT
      LAYER M5 ;
        RECT  24.144 27.996 24.168 28.08 ;
    END
  END head[501]
  PIN head[502]
    DIRECTION INPUT ;
    USE SIGNAL ;
    PORT
      LAYER M5 ;
        RECT  24.24 27.996 24.264 28.08 ;
    END
  END head[502]
  PIN head[503]
    DIRECTION INPUT ;
    USE SIGNAL ;
    PORT
      LAYER M5 ;
        RECT  24.336 27.996 24.36 28.08 ;
    END
  END head[503]
  PIN head[504]
    DIRECTION INPUT ;
    USE SIGNAL ;
    PORT
      LAYER M5 ;
        RECT  24.432 27.996 24.456 28.08 ;
    END
  END head[504]
  PIN head[505]
    DIRECTION INPUT ;
    USE SIGNAL ;
    PORT
      LAYER M5 ;
        RECT  24.528 27.996 24.552 28.08 ;
    END
  END head[505]
  PIN head[506]
    DIRECTION INPUT ;
    USE SIGNAL ;
    PORT
      LAYER M5 ;
        RECT  24.624 27.996 24.648 28.08 ;
    END
  END head[506]
  PIN head[507]
    DIRECTION INPUT ;
    USE SIGNAL ;
    PORT
      LAYER M5 ;
        RECT  24.72 27.996 24.744 28.08 ;
    END
  END head[507]
  PIN head[508]
    DIRECTION INPUT ;
    USE SIGNAL ;
    PORT
      LAYER M5 ;
        RECT  24.816 27.996 24.84 28.08 ;
    END
  END head[508]
  PIN head[509]
    DIRECTION INPUT ;
    USE SIGNAL ;
    PORT
      LAYER M5 ;
        RECT  24.912 27.996 24.936 28.08 ;
    END
  END head[509]
  PIN head[50]
    DIRECTION INPUT ;
    USE SIGNAL ;
    PORT
      LAYER M5 ;
        RECT  62.256 27.996 62.28 28.08 ;
    END
  END head[50]
  PIN head[510]
    DIRECTION INPUT ;
    USE SIGNAL ;
    PORT
      LAYER M5 ;
        RECT  14.064 27.996 14.088 28.08 ;
    END
  END head[510]
  PIN head[511]
    DIRECTION INPUT ;
    USE SIGNAL ;
    PORT
      LAYER M5 ;
        RECT  14.16 27.996 14.184 28.08 ;
    END
  END head[511]
  PIN head[512]
    DIRECTION INPUT ;
    USE SIGNAL ;
    PORT
      LAYER M5 ;
        RECT  14.256 27.996 14.28 28.08 ;
    END
  END head[512]
  PIN head[513]
    DIRECTION INPUT ;
    USE SIGNAL ;
    PORT
      LAYER M5 ;
        RECT  14.352 27.996 14.376 28.08 ;
    END
  END head[513]
  PIN head[514]
    DIRECTION INPUT ;
    USE SIGNAL ;
    PORT
      LAYER M5 ;
        RECT  14.448 27.996 14.472 28.08 ;
    END
  END head[514]
  PIN head[515]
    DIRECTION INPUT ;
    USE SIGNAL ;
    PORT
      LAYER M5 ;
        RECT  14.544 27.996 14.568 28.08 ;
    END
  END head[515]
  PIN head[516]
    DIRECTION INPUT ;
    USE SIGNAL ;
    PORT
      LAYER M5 ;
        RECT  14.64 27.996 14.664 28.08 ;
    END
  END head[516]
  PIN head[517]
    DIRECTION INPUT ;
    USE SIGNAL ;
    PORT
      LAYER M5 ;
        RECT  14.736 27.996 14.76 28.08 ;
    END
  END head[517]
  PIN head[518]
    DIRECTION INPUT ;
    USE SIGNAL ;
    PORT
      LAYER M5 ;
        RECT  14.832 27.996 14.856 28.08 ;
    END
  END head[518]
  PIN head[519]
    DIRECTION INPUT ;
    USE SIGNAL ;
    PORT
      LAYER M5 ;
        RECT  14.928 27.996 14.952 28.08 ;
    END
  END head[519]
  PIN head[51]
    DIRECTION INPUT ;
    USE SIGNAL ;
    PORT
      LAYER M5 ;
        RECT  62.352 27.996 62.376 28.08 ;
    END
  END head[51]
  PIN head[520]
    DIRECTION INPUT ;
    USE SIGNAL ;
    PORT
      LAYER M5 ;
        RECT  15.024 27.996 15.048 28.08 ;
    END
  END head[520]
  PIN head[521]
    DIRECTION INPUT ;
    USE SIGNAL ;
    PORT
      LAYER M5 ;
        RECT  15.12 27.996 15.144 28.08 ;
    END
  END head[521]
  PIN head[522]
    DIRECTION INPUT ;
    USE SIGNAL ;
    PORT
      LAYER M5 ;
        RECT  15.216 27.996 15.24 28.08 ;
    END
  END head[522]
  PIN head[523]
    DIRECTION INPUT ;
    USE SIGNAL ;
    PORT
      LAYER M5 ;
        RECT  15.312 27.996 15.336 28.08 ;
    END
  END head[523]
  PIN head[524]
    DIRECTION INPUT ;
    USE SIGNAL ;
    PORT
      LAYER M5 ;
        RECT  15.408 27.996 15.432 28.08 ;
    END
  END head[524]
  PIN head[525]
    DIRECTION INPUT ;
    USE SIGNAL ;
    PORT
      LAYER M5 ;
        RECT  15.504 27.996 15.528 28.08 ;
    END
  END head[525]
  PIN head[526]
    DIRECTION INPUT ;
    USE SIGNAL ;
    PORT
      LAYER M5 ;
        RECT  15.6 27.996 15.624 28.08 ;
    END
  END head[526]
  PIN head[527]
    DIRECTION INPUT ;
    USE SIGNAL ;
    PORT
      LAYER M5 ;
        RECT  15.696 27.996 15.72 28.08 ;
    END
  END head[527]
  PIN head[52]
    DIRECTION INPUT ;
    USE SIGNAL ;
    PORT
      LAYER M5 ;
        RECT  62.448 27.996 62.472 28.08 ;
    END
  END head[52]
  PIN head[53]
    DIRECTION INPUT ;
    USE SIGNAL ;
    PORT
      LAYER M5 ;
        RECT  62.544 27.996 62.568 28.08 ;
    END
  END head[53]
  PIN head[54]
    DIRECTION INPUT ;
    USE SIGNAL ;
    PORT
      LAYER M5 ;
        RECT  62.64 27.996 62.664 28.08 ;
    END
  END head[54]
  PIN head[55]
    DIRECTION INPUT ;
    USE SIGNAL ;
    PORT
      LAYER M5 ;
        RECT  62.736 27.996 62.76 28.08 ;
    END
  END head[55]
  PIN head[56]
    DIRECTION INPUT ;
    USE SIGNAL ;
    PORT
      LAYER M5 ;
        RECT  62.832 27.996 62.856 28.08 ;
    END
  END head[56]
  PIN head[57]
    DIRECTION INPUT ;
    USE SIGNAL ;
    PORT
      LAYER M5 ;
        RECT  62.928 27.996 62.952 28.08 ;
    END
  END head[57]
  PIN head[58]
    DIRECTION INPUT ;
    USE SIGNAL ;
    PORT
      LAYER M5 ;
        RECT  63.024 27.996 63.048 28.08 ;
    END
  END head[58]
  PIN head[59]
    DIRECTION INPUT ;
    USE SIGNAL ;
    PORT
      LAYER M5 ;
        RECT  63.12 27.996 63.144 28.08 ;
    END
  END head[59]
  PIN head[5]
    DIRECTION INPUT ;
    USE SIGNAL ;
    PORT
      LAYER M5 ;
        RECT  48.72 27.996 48.744 28.08 ;
    END
  END head[5]
  PIN head[60]
    DIRECTION INPUT ;
    USE SIGNAL ;
    PORT
      LAYER M5 ;
        RECT  63.216 27.996 63.24 28.08 ;
    END
  END head[60]
  PIN head[61]
    DIRECTION INPUT ;
    USE SIGNAL ;
    PORT
      LAYER M5 ;
        RECT  63.312 27.996 63.336 28.08 ;
    END
  END head[61]
  PIN head[62]
    DIRECTION INPUT ;
    USE SIGNAL ;
    PORT
      LAYER M5 ;
        RECT  54.192 27.996 54.216 28.08 ;
    END
  END head[62]
  PIN head[63]
    DIRECTION INPUT ;
    USE SIGNAL ;
    PORT
      LAYER M5 ;
        RECT  54.288 27.996 54.312 28.08 ;
    END
  END head[63]
  PIN head[64]
    DIRECTION INPUT ;
    USE SIGNAL ;
    PORT
      LAYER M5 ;
        RECT  54.384 27.996 54.408 28.08 ;
    END
  END head[64]
  PIN head[65]
    DIRECTION INPUT ;
    USE SIGNAL ;
    PORT
      LAYER M5 ;
        RECT  54.48 27.996 54.504 28.08 ;
    END
  END head[65]
  PIN head[66]
    DIRECTION INPUT ;
    USE SIGNAL ;
    PORT
      LAYER M5 ;
        RECT  54.576 27.996 54.6 28.08 ;
    END
  END head[66]
  PIN head[67]
    DIRECTION INPUT ;
    USE SIGNAL ;
    PORT
      LAYER M5 ;
        RECT  54.672 27.996 54.696 28.08 ;
    END
  END head[67]
  PIN head[68]
    DIRECTION INPUT ;
    USE SIGNAL ;
    PORT
      LAYER M5 ;
        RECT  54.768 27.996 54.792 28.08 ;
    END
  END head[68]
  PIN head[69]
    DIRECTION INPUT ;
    USE SIGNAL ;
    PORT
      LAYER M5 ;
        RECT  54.864 27.996 54.888 28.08 ;
    END
  END head[69]
  PIN head[6]
    DIRECTION INPUT ;
    USE SIGNAL ;
    PORT
      LAYER M5 ;
        RECT  48.816 27.996 48.84 28.08 ;
    END
  END head[6]
  PIN head[70]
    DIRECTION INPUT ;
    USE SIGNAL ;
    PORT
      LAYER M5 ;
        RECT  54.96 27.996 54.984 28.08 ;
    END
  END head[70]
  PIN head[71]
    DIRECTION INPUT ;
    USE SIGNAL ;
    PORT
      LAYER M5 ;
        RECT  55.056 27.996 55.08 28.08 ;
    END
  END head[71]
  PIN head[72]
    DIRECTION INPUT ;
    USE SIGNAL ;
    PORT
      LAYER M5 ;
        RECT  55.152 27.996 55.176 28.08 ;
    END
  END head[72]
  PIN head[73]
    DIRECTION INPUT ;
    USE SIGNAL ;
    PORT
      LAYER M5 ;
        RECT  55.248 27.996 55.272 28.08 ;
    END
  END head[73]
  PIN head[74]
    DIRECTION INPUT ;
    USE SIGNAL ;
    PORT
      LAYER M5 ;
        RECT  55.344 27.996 55.368 28.08 ;
    END
  END head[74]
  PIN head[75]
    DIRECTION INPUT ;
    USE SIGNAL ;
    PORT
      LAYER M5 ;
        RECT  55.44 27.996 55.464 28.08 ;
    END
  END head[75]
  PIN head[76]
    DIRECTION INPUT ;
    USE SIGNAL ;
    PORT
      LAYER M5 ;
        RECT  55.536 27.996 55.56 28.08 ;
    END
  END head[76]
  PIN head[77]
    DIRECTION INPUT ;
    USE SIGNAL ;
    PORT
      LAYER M5 ;
        RECT  55.632 27.996 55.656 28.08 ;
    END
  END head[77]
  PIN head[78]
    DIRECTION INPUT ;
    USE SIGNAL ;
    PORT
      LAYER M5 ;
        RECT  55.728 27.996 55.752 28.08 ;
    END
  END head[78]
  PIN head[79]
    DIRECTION INPUT ;
    USE SIGNAL ;
    PORT
      LAYER M5 ;
        RECT  55.824 27.996 55.848 28.08 ;
    END
  END head[79]
  PIN head[7]
    DIRECTION INPUT ;
    USE SIGNAL ;
    PORT
      LAYER M5 ;
        RECT  48.912 27.996 48.936 28.08 ;
    END
  END head[7]
  PIN head[80]
    DIRECTION INPUT ;
    USE SIGNAL ;
    PORT
      LAYER M5 ;
        RECT  55.92 27.996 55.944 28.08 ;
    END
  END head[80]
  PIN head[81]
    DIRECTION INPUT ;
    USE SIGNAL ;
    PORT
      LAYER M5 ;
        RECT  56.016 27.996 56.04 28.08 ;
    END
  END head[81]
  PIN head[82]
    DIRECTION INPUT ;
    USE SIGNAL ;
    PORT
      LAYER M5 ;
        RECT  56.112 27.996 56.136 28.08 ;
    END
  END head[82]
  PIN head[83]
    DIRECTION INPUT ;
    USE SIGNAL ;
    PORT
      LAYER M5 ;
        RECT  56.208 27.996 56.232 28.08 ;
    END
  END head[83]
  PIN head[84]
    DIRECTION INPUT ;
    USE SIGNAL ;
    PORT
      LAYER M5 ;
        RECT  56.304 27.996 56.328 28.08 ;
    END
  END head[84]
  PIN head[85]
    DIRECTION INPUT ;
    USE SIGNAL ;
    PORT
      LAYER M5 ;
        RECT  56.4 27.996 56.424 28.08 ;
    END
  END head[85]
  PIN head[86]
    DIRECTION INPUT ;
    USE SIGNAL ;
    PORT
      LAYER M5 ;
        RECT  56.496 27.996 56.52 28.08 ;
    END
  END head[86]
  PIN head[87]
    DIRECTION INPUT ;
    USE SIGNAL ;
    PORT
      LAYER M5 ;
        RECT  56.592 27.996 56.616 28.08 ;
    END
  END head[87]
  PIN head[88]
    DIRECTION INPUT ;
    USE SIGNAL ;
    PORT
      LAYER M5 ;
        RECT  56.688 27.996 56.712 28.08 ;
    END
  END head[88]
  PIN head[89]
    DIRECTION INPUT ;
    USE SIGNAL ;
    PORT
      LAYER M5 ;
        RECT  56.784 27.996 56.808 28.08 ;
    END
  END head[89]
  PIN head[8]
    DIRECTION INPUT ;
    USE SIGNAL ;
    PORT
      LAYER M5 ;
        RECT  49.008 27.996 49.032 28.08 ;
    END
  END head[8]
  PIN head[90]
    DIRECTION INPUT ;
    USE SIGNAL ;
    PORT
      LAYER M5 ;
        RECT  56.88 27.996 56.904 28.08 ;
    END
  END head[90]
  PIN head[91]
    DIRECTION INPUT ;
    USE SIGNAL ;
    PORT
      LAYER M5 ;
        RECT  56.976 27.996 57 28.08 ;
    END
  END head[91]
  PIN head[92]
    DIRECTION INPUT ;
    USE SIGNAL ;
    PORT
      LAYER M5 ;
        RECT  57.072 27.996 57.096 28.08 ;
    END
  END head[92]
  PIN head[93]
    DIRECTION INPUT ;
    USE SIGNAL ;
    PORT
      LAYER M5 ;
        RECT  57.168 27.996 57.192 28.08 ;
    END
  END head[93]
  PIN head[94]
    DIRECTION INPUT ;
    USE SIGNAL ;
    PORT
      LAYER M5 ;
        RECT  41.136 27.996 41.16 28.08 ;
    END
  END head[94]
  PIN head[95]
    DIRECTION INPUT ;
    USE SIGNAL ;
    PORT
      LAYER M5 ;
        RECT  41.232 27.996 41.256 28.08 ;
    END
  END head[95]
  PIN head[96]
    DIRECTION INPUT ;
    USE SIGNAL ;
    PORT
      LAYER M5 ;
        RECT  41.328 27.996 41.352 28.08 ;
    END
  END head[96]
  PIN head[97]
    DIRECTION INPUT ;
    USE SIGNAL ;
    PORT
      LAYER M5 ;
        RECT  41.424 27.996 41.448 28.08 ;
    END
  END head[97]
  PIN head[98]
    DIRECTION INPUT ;
    USE SIGNAL ;
    PORT
      LAYER M5 ;
        RECT  41.52 27.996 41.544 28.08 ;
    END
  END head[98]
  PIN head[99]
    DIRECTION INPUT ;
    USE SIGNAL ;
    PORT
      LAYER M5 ;
        RECT  41.616 27.996 41.64 28.08 ;
    END
  END head[99]
  PIN head[9]
    DIRECTION INPUT ;
    USE SIGNAL ;
    PORT
      LAYER M5 ;
        RECT  49.104 27.996 49.128 28.08 ;
    END
  END head[9]
  PIN r_cr
    DIRECTION INPUT ;
    USE SIGNAL ;
    PORT
      LAYER M5 ;
        RECT  48.336 0 48.36 0.084 ;
    END
  END r_cr
  PIN r_d[0]
    DIRECTION OUTPUT ;
    USE SIGNAL ;
    PORT
      LAYER M5 ;
        RECT  48.432 0 48.456 0.084 ;
    END
  END r_d[0]
  PIN r_d[100]
    DIRECTION OUTPUT ;
    USE SIGNAL ;
    PORT
      LAYER M5 ;
        RECT  45.744 0 45.768 0.084 ;
    END
  END r_d[100]
  PIN r_d[101]
    DIRECTION OUTPUT ;
    USE SIGNAL ;
    PORT
      LAYER M5 ;
        RECT  45.84 0 45.864 0.084 ;
    END
  END r_d[101]
  PIN r_d[102]
    DIRECTION OUTPUT ;
    USE SIGNAL ;
    PORT
      LAYER M5 ;
        RECT  45.936 0 45.96 0.084 ;
    END
  END r_d[102]
  PIN r_d[103]
    DIRECTION OUTPUT ;
    USE SIGNAL ;
    PORT
      LAYER M5 ;
        RECT  46.032 0 46.056 0.084 ;
    END
  END r_d[103]
  PIN r_d[104]
    DIRECTION OUTPUT ;
    USE SIGNAL ;
    PORT
      LAYER M5 ;
        RECT  46.128 0 46.152 0.084 ;
    END
  END r_d[104]
  PIN r_d[105]
    DIRECTION OUTPUT ;
    USE SIGNAL ;
    PORT
      LAYER M5 ;
        RECT  46.224 0 46.248 0.084 ;
    END
  END r_d[105]
  PIN r_d[106]
    DIRECTION OUTPUT ;
    USE SIGNAL ;
    PORT
      LAYER M5 ;
        RECT  46.32 0 46.344 0.084 ;
    END
  END r_d[106]
  PIN r_d[107]
    DIRECTION OUTPUT ;
    USE SIGNAL ;
    PORT
      LAYER M5 ;
        RECT  46.416 0 46.44 0.084 ;
    END
  END r_d[107]
  PIN r_d[108]
    DIRECTION OUTPUT ;
    USE SIGNAL ;
    PORT
      LAYER M5 ;
        RECT  46.512 0 46.536 0.084 ;
    END
  END r_d[108]
  PIN r_d[109]
    DIRECTION OUTPUT ;
    USE SIGNAL ;
    PORT
      LAYER M5 ;
        RECT  46.608 0 46.632 0.084 ;
    END
  END r_d[109]
  PIN r_d[10]
    DIRECTION OUTPUT ;
    USE SIGNAL ;
    PORT
      LAYER M5 ;
        RECT  49.392 0 49.416 0.084 ;
    END
  END r_d[10]
  PIN r_d[110]
    DIRECTION OUTPUT ;
    USE SIGNAL ;
    PORT
      LAYER M5 ;
        RECT  46.704 0 46.728 0.084 ;
    END
  END r_d[110]
  PIN r_d[111]
    DIRECTION OUTPUT ;
    USE SIGNAL ;
    PORT
      LAYER M5 ;
        RECT  46.8 0 46.824 0.084 ;
    END
  END r_d[111]
  PIN r_d[112]
    DIRECTION OUTPUT ;
    USE SIGNAL ;
    PORT
      LAYER M5 ;
        RECT  46.896 0 46.92 0.084 ;
    END
  END r_d[112]
  PIN r_d[113]
    DIRECTION OUTPUT ;
    USE SIGNAL ;
    PORT
      LAYER M5 ;
        RECT  46.992 0 47.016 0.084 ;
    END
  END r_d[113]
  PIN r_d[114]
    DIRECTION OUTPUT ;
    USE SIGNAL ;
    PORT
      LAYER M5 ;
        RECT  47.088 0 47.112 0.084 ;
    END
  END r_d[114]
  PIN r_d[115]
    DIRECTION OUTPUT ;
    USE SIGNAL ;
    PORT
      LAYER M5 ;
        RECT  47.184 0 47.208 0.084 ;
    END
  END r_d[115]
  PIN r_d[116]
    DIRECTION OUTPUT ;
    USE SIGNAL ;
    PORT
      LAYER M5 ;
        RECT  47.28 0 47.304 0.084 ;
    END
  END r_d[116]
  PIN r_d[117]
    DIRECTION OUTPUT ;
    USE SIGNAL ;
    PORT
      LAYER M5 ;
        RECT  47.376 0 47.4 0.084 ;
    END
  END r_d[117]
  PIN r_d[118]
    DIRECTION OUTPUT ;
    USE SIGNAL ;
    PORT
      LAYER M5 ;
        RECT  47.472 0 47.496 0.084 ;
    END
  END r_d[118]
  PIN r_d[119]
    DIRECTION OUTPUT ;
    USE SIGNAL ;
    PORT
      LAYER M5 ;
        RECT  47.568 0 47.592 0.084 ;
    END
  END r_d[119]
  PIN r_d[11]
    DIRECTION OUTPUT ;
    USE SIGNAL ;
    PORT
      LAYER M5 ;
        RECT  49.488 0 49.512 0.084 ;
    END
  END r_d[11]
  PIN r_d[120]
    DIRECTION OUTPUT ;
    USE SIGNAL ;
    PORT
      LAYER M5 ;
        RECT  47.664 0 47.688 0.084 ;
    END
  END r_d[120]
  PIN r_d[121]
    DIRECTION OUTPUT ;
    USE SIGNAL ;
    PORT
      LAYER M5 ;
        RECT  47.76 0 47.784 0.084 ;
    END
  END r_d[121]
  PIN r_d[122]
    DIRECTION OUTPUT ;
    USE SIGNAL ;
    PORT
      LAYER M5 ;
        RECT  47.856 0 47.88 0.084 ;
    END
  END r_d[122]
  PIN r_d[123]
    DIRECTION OUTPUT ;
    USE SIGNAL ;
    PORT
      LAYER M5 ;
        RECT  47.952 0 47.976 0.084 ;
    END
  END r_d[123]
  PIN r_d[124]
    DIRECTION OUTPUT ;
    USE SIGNAL ;
    PORT
      LAYER M5 ;
        RECT  48.048 0 48.072 0.084 ;
    END
  END r_d[124]
  PIN r_d[125]
    DIRECTION OUTPUT ;
    USE SIGNAL ;
    PORT
      LAYER M5 ;
        RECT  48.144 0 48.168 0.084 ;
    END
  END r_d[125]
  PIN r_d[126]
    DIRECTION OUTPUT ;
    USE SIGNAL ;
    PORT
      LAYER M5 ;
        RECT  48.24 0 48.264 0.084 ;
    END
  END r_d[126]
  PIN r_d[127]
    DIRECTION OUTPUT ;
    USE SIGNAL ;
    PORT
      LAYER M5 ;
        RECT  26.064 0 26.088 0.084 ;
    END
  END r_d[127]
  PIN r_d[128]
    DIRECTION OUTPUT ;
    USE SIGNAL ;
    PORT
      LAYER M5 ;
        RECT  26.16 0 26.184 0.084 ;
    END
  END r_d[128]
  PIN r_d[129]
    DIRECTION OUTPUT ;
    USE SIGNAL ;
    PORT
      LAYER M5 ;
        RECT  26.256 0 26.28 0.084 ;
    END
  END r_d[129]
  PIN r_d[12]
    DIRECTION OUTPUT ;
    USE SIGNAL ;
    PORT
      LAYER M5 ;
        RECT  49.584 0 49.608 0.084 ;
    END
  END r_d[12]
  PIN r_d[130]
    DIRECTION OUTPUT ;
    USE SIGNAL ;
    PORT
      LAYER M5 ;
        RECT  26.352 0 26.376 0.084 ;
    END
  END r_d[130]
  PIN r_d[131]
    DIRECTION OUTPUT ;
    USE SIGNAL ;
    PORT
      LAYER M5 ;
        RECT  26.448 0 26.472 0.084 ;
    END
  END r_d[131]
  PIN r_d[132]
    DIRECTION OUTPUT ;
    USE SIGNAL ;
    PORT
      LAYER M5 ;
        RECT  26.544 0 26.568 0.084 ;
    END
  END r_d[132]
  PIN r_d[133]
    DIRECTION OUTPUT ;
    USE SIGNAL ;
    PORT
      LAYER M5 ;
        RECT  26.64 0 26.664 0.084 ;
    END
  END r_d[133]
  PIN r_d[134]
    DIRECTION OUTPUT ;
    USE SIGNAL ;
    PORT
      LAYER M5 ;
        RECT  26.736 0 26.76 0.084 ;
    END
  END r_d[134]
  PIN r_d[135]
    DIRECTION OUTPUT ;
    USE SIGNAL ;
    PORT
      LAYER M5 ;
        RECT  26.832 0 26.856 0.084 ;
    END
  END r_d[135]
  PIN r_d[136]
    DIRECTION OUTPUT ;
    USE SIGNAL ;
    PORT
      LAYER M5 ;
        RECT  26.928 0 26.952 0.084 ;
    END
  END r_d[136]
  PIN r_d[137]
    DIRECTION OUTPUT ;
    USE SIGNAL ;
    PORT
      LAYER M5 ;
        RECT  27.024 0 27.048 0.084 ;
    END
  END r_d[137]
  PIN r_d[138]
    DIRECTION OUTPUT ;
    USE SIGNAL ;
    PORT
      LAYER M5 ;
        RECT  27.12 0 27.144 0.084 ;
    END
  END r_d[138]
  PIN r_d[139]
    DIRECTION OUTPUT ;
    USE SIGNAL ;
    PORT
      LAYER M5 ;
        RECT  27.216 0 27.24 0.084 ;
    END
  END r_d[139]
  PIN r_d[13]
    DIRECTION OUTPUT ;
    USE SIGNAL ;
    PORT
      LAYER M5 ;
        RECT  49.68 0 49.704 0.084 ;
    END
  END r_d[13]
  PIN r_d[140]
    DIRECTION OUTPUT ;
    USE SIGNAL ;
    PORT
      LAYER M5 ;
        RECT  27.312 0 27.336 0.084 ;
    END
  END r_d[140]
  PIN r_d[141]
    DIRECTION OUTPUT ;
    USE SIGNAL ;
    PORT
      LAYER M5 ;
        RECT  27.408 0 27.432 0.084 ;
    END
  END r_d[141]
  PIN r_d[142]
    DIRECTION OUTPUT ;
    USE SIGNAL ;
    PORT
      LAYER M5 ;
        RECT  27.504 0 27.528 0.084 ;
    END
  END r_d[142]
  PIN r_d[143]
    DIRECTION OUTPUT ;
    USE SIGNAL ;
    PORT
      LAYER M5 ;
        RECT  27.6 0 27.624 0.084 ;
    END
  END r_d[143]
  PIN r_d[144]
    DIRECTION OUTPUT ;
    USE SIGNAL ;
    PORT
      LAYER M5 ;
        RECT  27.696 0 27.72 0.084 ;
    END
  END r_d[144]
  PIN r_d[145]
    DIRECTION OUTPUT ;
    USE SIGNAL ;
    PORT
      LAYER M5 ;
        RECT  27.792 0 27.816 0.084 ;
    END
  END r_d[145]
  PIN r_d[146]
    DIRECTION OUTPUT ;
    USE SIGNAL ;
    PORT
      LAYER M5 ;
        RECT  27.888 0 27.912 0.084 ;
    END
  END r_d[146]
  PIN r_d[147]
    DIRECTION OUTPUT ;
    USE SIGNAL ;
    PORT
      LAYER M5 ;
        RECT  27.984 0 28.008 0.084 ;
    END
  END r_d[147]
  PIN r_d[148]
    DIRECTION OUTPUT ;
    USE SIGNAL ;
    PORT
      LAYER M5 ;
        RECT  28.08 0 28.104 0.084 ;
    END
  END r_d[148]
  PIN r_d[149]
    DIRECTION OUTPUT ;
    USE SIGNAL ;
    PORT
      LAYER M5 ;
        RECT  28.176 0 28.2 0.084 ;
    END
  END r_d[149]
  PIN r_d[14]
    DIRECTION OUTPUT ;
    USE SIGNAL ;
    PORT
      LAYER M5 ;
        RECT  49.776 0 49.8 0.084 ;
    END
  END r_d[14]
  PIN r_d[150]
    DIRECTION OUTPUT ;
    USE SIGNAL ;
    PORT
      LAYER M5 ;
        RECT  28.272 0 28.296 0.084 ;
    END
  END r_d[150]
  PIN r_d[151]
    DIRECTION OUTPUT ;
    USE SIGNAL ;
    PORT
      LAYER M5 ;
        RECT  28.368 0 28.392 0.084 ;
    END
  END r_d[151]
  PIN r_d[152]
    DIRECTION OUTPUT ;
    USE SIGNAL ;
    PORT
      LAYER M5 ;
        RECT  28.464 0 28.488 0.084 ;
    END
  END r_d[152]
  PIN r_d[153]
    DIRECTION OUTPUT ;
    USE SIGNAL ;
    PORT
      LAYER M5 ;
        RECT  28.56 0 28.584 0.084 ;
    END
  END r_d[153]
  PIN r_d[154]
    DIRECTION OUTPUT ;
    USE SIGNAL ;
    PORT
      LAYER M5 ;
        RECT  28.656 0 28.68 0.084 ;
    END
  END r_d[154]
  PIN r_d[155]
    DIRECTION OUTPUT ;
    USE SIGNAL ;
    PORT
      LAYER M5 ;
        RECT  28.752 0 28.776 0.084 ;
    END
  END r_d[155]
  PIN r_d[156]
    DIRECTION OUTPUT ;
    USE SIGNAL ;
    PORT
      LAYER M5 ;
        RECT  28.848 0 28.872 0.084 ;
    END
  END r_d[156]
  PIN r_d[157]
    DIRECTION OUTPUT ;
    USE SIGNAL ;
    PORT
      LAYER M5 ;
        RECT  28.944 0 28.968 0.084 ;
    END
  END r_d[157]
  PIN r_d[158]
    DIRECTION OUTPUT ;
    USE SIGNAL ;
    PORT
      LAYER M5 ;
        RECT  29.04 0 29.064 0.084 ;
    END
  END r_d[158]
  PIN r_d[159]
    DIRECTION OUTPUT ;
    USE SIGNAL ;
    PORT
      LAYER M5 ;
        RECT  42.192 0 42.216 0.084 ;
    END
  END r_d[159]
  PIN r_d[15]
    DIRECTION OUTPUT ;
    USE SIGNAL ;
    PORT
      LAYER M5 ;
        RECT  49.872 0 49.896 0.084 ;
    END
  END r_d[15]
  PIN r_d[160]
    DIRECTION OUTPUT ;
    USE SIGNAL ;
    PORT
      LAYER M5 ;
        RECT  42.288 0 42.312 0.084 ;
    END
  END r_d[160]
  PIN r_d[161]
    DIRECTION OUTPUT ;
    USE SIGNAL ;
    PORT
      LAYER M5 ;
        RECT  42.384 0 42.408 0.084 ;
    END
  END r_d[161]
  PIN r_d[162]
    DIRECTION OUTPUT ;
    USE SIGNAL ;
    PORT
      LAYER M5 ;
        RECT  42.48 0 42.504 0.084 ;
    END
  END r_d[162]
  PIN r_d[163]
    DIRECTION OUTPUT ;
    USE SIGNAL ;
    PORT
      LAYER M5 ;
        RECT  42.576 0 42.6 0.084 ;
    END
  END r_d[163]
  PIN r_d[164]
    DIRECTION OUTPUT ;
    USE SIGNAL ;
    PORT
      LAYER M5 ;
        RECT  42.672 0 42.696 0.084 ;
    END
  END r_d[164]
  PIN r_d[165]
    DIRECTION OUTPUT ;
    USE SIGNAL ;
    PORT
      LAYER M5 ;
        RECT  42.768 0 42.792 0.084 ;
    END
  END r_d[165]
  PIN r_d[166]
    DIRECTION OUTPUT ;
    USE SIGNAL ;
    PORT
      LAYER M5 ;
        RECT  42.864 0 42.888 0.084 ;
    END
  END r_d[166]
  PIN r_d[167]
    DIRECTION OUTPUT ;
    USE SIGNAL ;
    PORT
      LAYER M5 ;
        RECT  42.96 0 42.984 0.084 ;
    END
  END r_d[167]
  PIN r_d[168]
    DIRECTION OUTPUT ;
    USE SIGNAL ;
    PORT
      LAYER M5 ;
        RECT  43.056 0 43.08 0.084 ;
    END
  END r_d[168]
  PIN r_d[169]
    DIRECTION OUTPUT ;
    USE SIGNAL ;
    PORT
      LAYER M5 ;
        RECT  43.152 0 43.176 0.084 ;
    END
  END r_d[169]
  PIN r_d[16]
    DIRECTION OUTPUT ;
    USE SIGNAL ;
    PORT
      LAYER M5 ;
        RECT  49.968 0 49.992 0.084 ;
    END
  END r_d[16]
  PIN r_d[170]
    DIRECTION OUTPUT ;
    USE SIGNAL ;
    PORT
      LAYER M5 ;
        RECT  43.248 0 43.272 0.084 ;
    END
  END r_d[170]
  PIN r_d[171]
    DIRECTION OUTPUT ;
    USE SIGNAL ;
    PORT
      LAYER M5 ;
        RECT  43.344 0 43.368 0.084 ;
    END
  END r_d[171]
  PIN r_d[172]
    DIRECTION OUTPUT ;
    USE SIGNAL ;
    PORT
      LAYER M5 ;
        RECT  43.44 0 43.464 0.084 ;
    END
  END r_d[172]
  PIN r_d[173]
    DIRECTION OUTPUT ;
    USE SIGNAL ;
    PORT
      LAYER M5 ;
        RECT  43.536 0 43.56 0.084 ;
    END
  END r_d[173]
  PIN r_d[174]
    DIRECTION OUTPUT ;
    USE SIGNAL ;
    PORT
      LAYER M5 ;
        RECT  43.632 0 43.656 0.084 ;
    END
  END r_d[174]
  PIN r_d[175]
    DIRECTION OUTPUT ;
    USE SIGNAL ;
    PORT
      LAYER M5 ;
        RECT  43.728 0 43.752 0.084 ;
    END
  END r_d[175]
  PIN r_d[176]
    DIRECTION OUTPUT ;
    USE SIGNAL ;
    PORT
      LAYER M5 ;
        RECT  43.824 0 43.848 0.084 ;
    END
  END r_d[176]
  PIN r_d[177]
    DIRECTION OUTPUT ;
    USE SIGNAL ;
    PORT
      LAYER M5 ;
        RECT  43.92 0 43.944 0.084 ;
    END
  END r_d[177]
  PIN r_d[178]
    DIRECTION OUTPUT ;
    USE SIGNAL ;
    PORT
      LAYER M5 ;
        RECT  44.016 0 44.04 0.084 ;
    END
  END r_d[178]
  PIN r_d[179]
    DIRECTION OUTPUT ;
    USE SIGNAL ;
    PORT
      LAYER M5 ;
        RECT  44.112 0 44.136 0.084 ;
    END
  END r_d[179]
  PIN r_d[17]
    DIRECTION OUTPUT ;
    USE SIGNAL ;
    PORT
      LAYER M5 ;
        RECT  50.064 0 50.088 0.084 ;
    END
  END r_d[17]
  PIN r_d[180]
    DIRECTION OUTPUT ;
    USE SIGNAL ;
    PORT
      LAYER M5 ;
        RECT  44.208 0 44.232 0.084 ;
    END
  END r_d[180]
  PIN r_d[181]
    DIRECTION OUTPUT ;
    USE SIGNAL ;
    PORT
      LAYER M5 ;
        RECT  44.304 0 44.328 0.084 ;
    END
  END r_d[181]
  PIN r_d[182]
    DIRECTION OUTPUT ;
    USE SIGNAL ;
    PORT
      LAYER M5 ;
        RECT  44.4 0 44.424 0.084 ;
    END
  END r_d[182]
  PIN r_d[183]
    DIRECTION OUTPUT ;
    USE SIGNAL ;
    PORT
      LAYER M5 ;
        RECT  44.496 0 44.52 0.084 ;
    END
  END r_d[183]
  PIN r_d[184]
    DIRECTION OUTPUT ;
    USE SIGNAL ;
    PORT
      LAYER M5 ;
        RECT  44.592 0 44.616 0.084 ;
    END
  END r_d[184]
  PIN r_d[185]
    DIRECTION OUTPUT ;
    USE SIGNAL ;
    PORT
      LAYER M5 ;
        RECT  44.688 0 44.712 0.084 ;
    END
  END r_d[185]
  PIN r_d[186]
    DIRECTION OUTPUT ;
    USE SIGNAL ;
    PORT
      LAYER M5 ;
        RECT  44.784 0 44.808 0.084 ;
    END
  END r_d[186]
  PIN r_d[187]
    DIRECTION OUTPUT ;
    USE SIGNAL ;
    PORT
      LAYER M5 ;
        RECT  44.88 0 44.904 0.084 ;
    END
  END r_d[187]
  PIN r_d[188]
    DIRECTION OUTPUT ;
    USE SIGNAL ;
    PORT
      LAYER M5 ;
        RECT  44.976 0 45 0.084 ;
    END
  END r_d[188]
  PIN r_d[189]
    DIRECTION OUTPUT ;
    USE SIGNAL ;
    PORT
      LAYER M5 ;
        RECT  45.072 0 45.096 0.084 ;
    END
  END r_d[189]
  PIN r_d[18]
    DIRECTION OUTPUT ;
    USE SIGNAL ;
    PORT
      LAYER M5 ;
        RECT  50.16 0 50.184 0.084 ;
    END
  END r_d[18]
  PIN r_d[190]
    DIRECTION OUTPUT ;
    USE SIGNAL ;
    PORT
      LAYER M5 ;
        RECT  45.168 0 45.192 0.084 ;
    END
  END r_d[190]
  PIN r_d[191]
    DIRECTION OUTPUT ;
    USE SIGNAL ;
    PORT
      LAYER M5 ;
        RECT  39.12 0 39.144 0.084 ;
    END
  END r_d[191]
  PIN r_d[192]
    DIRECTION OUTPUT ;
    USE SIGNAL ;
    PORT
      LAYER M5 ;
        RECT  39.216 0 39.24 0.084 ;
    END
  END r_d[192]
  PIN r_d[193]
    DIRECTION OUTPUT ;
    USE SIGNAL ;
    PORT
      LAYER M5 ;
        RECT  39.312 0 39.336 0.084 ;
    END
  END r_d[193]
  PIN r_d[194]
    DIRECTION OUTPUT ;
    USE SIGNAL ;
    PORT
      LAYER M5 ;
        RECT  39.408 0 39.432 0.084 ;
    END
  END r_d[194]
  PIN r_d[195]
    DIRECTION OUTPUT ;
    USE SIGNAL ;
    PORT
      LAYER M5 ;
        RECT  39.504 0 39.528 0.084 ;
    END
  END r_d[195]
  PIN r_d[196]
    DIRECTION OUTPUT ;
    USE SIGNAL ;
    PORT
      LAYER M5 ;
        RECT  39.6 0 39.624 0.084 ;
    END
  END r_d[196]
  PIN r_d[197]
    DIRECTION OUTPUT ;
    USE SIGNAL ;
    PORT
      LAYER M5 ;
        RECT  39.696 0 39.72 0.084 ;
    END
  END r_d[197]
  PIN r_d[198]
    DIRECTION OUTPUT ;
    USE SIGNAL ;
    PORT
      LAYER M5 ;
        RECT  39.792 0 39.816 0.084 ;
    END
  END r_d[198]
  PIN r_d[199]
    DIRECTION OUTPUT ;
    USE SIGNAL ;
    PORT
      LAYER M5 ;
        RECT  39.888 0 39.912 0.084 ;
    END
  END r_d[199]
  PIN r_d[19]
    DIRECTION OUTPUT ;
    USE SIGNAL ;
    PORT
      LAYER M5 ;
        RECT  50.256 0 50.28 0.084 ;
    END
  END r_d[19]
  PIN r_d[1]
    DIRECTION OUTPUT ;
    USE SIGNAL ;
    PORT
      LAYER M5 ;
        RECT  48.528 0 48.552 0.084 ;
    END
  END r_d[1]
  PIN r_d[200]
    DIRECTION OUTPUT ;
    USE SIGNAL ;
    PORT
      LAYER M5 ;
        RECT  39.984 0 40.008 0.084 ;
    END
  END r_d[200]
  PIN r_d[201]
    DIRECTION OUTPUT ;
    USE SIGNAL ;
    PORT
      LAYER M5 ;
        RECT  40.08 0 40.104 0.084 ;
    END
  END r_d[201]
  PIN r_d[202]
    DIRECTION OUTPUT ;
    USE SIGNAL ;
    PORT
      LAYER M5 ;
        RECT  40.176 0 40.2 0.084 ;
    END
  END r_d[202]
  PIN r_d[203]
    DIRECTION OUTPUT ;
    USE SIGNAL ;
    PORT
      LAYER M5 ;
        RECT  40.272 0 40.296 0.084 ;
    END
  END r_d[203]
  PIN r_d[204]
    DIRECTION OUTPUT ;
    USE SIGNAL ;
    PORT
      LAYER M5 ;
        RECT  40.368 0 40.392 0.084 ;
    END
  END r_d[204]
  PIN r_d[205]
    DIRECTION OUTPUT ;
    USE SIGNAL ;
    PORT
      LAYER M5 ;
        RECT  40.464 0 40.488 0.084 ;
    END
  END r_d[205]
  PIN r_d[206]
    DIRECTION OUTPUT ;
    USE SIGNAL ;
    PORT
      LAYER M5 ;
        RECT  40.56 0 40.584 0.084 ;
    END
  END r_d[206]
  PIN r_d[207]
    DIRECTION OUTPUT ;
    USE SIGNAL ;
    PORT
      LAYER M5 ;
        RECT  40.656 0 40.68 0.084 ;
    END
  END r_d[207]
  PIN r_d[208]
    DIRECTION OUTPUT ;
    USE SIGNAL ;
    PORT
      LAYER M5 ;
        RECT  40.752 0 40.776 0.084 ;
    END
  END r_d[208]
  PIN r_d[209]
    DIRECTION OUTPUT ;
    USE SIGNAL ;
    PORT
      LAYER M5 ;
        RECT  40.848 0 40.872 0.084 ;
    END
  END r_d[209]
  PIN r_d[20]
    DIRECTION OUTPUT ;
    USE SIGNAL ;
    PORT
      LAYER M5 ;
        RECT  50.352 0 50.376 0.084 ;
    END
  END r_d[20]
  PIN r_d[210]
    DIRECTION OUTPUT ;
    USE SIGNAL ;
    PORT
      LAYER M5 ;
        RECT  40.944 0 40.968 0.084 ;
    END
  END r_d[210]
  PIN r_d[211]
    DIRECTION OUTPUT ;
    USE SIGNAL ;
    PORT
      LAYER M5 ;
        RECT  41.04 0 41.064 0.084 ;
    END
  END r_d[211]
  PIN r_d[212]
    DIRECTION OUTPUT ;
    USE SIGNAL ;
    PORT
      LAYER M5 ;
        RECT  41.136 0 41.16 0.084 ;
    END
  END r_d[212]
  PIN r_d[213]
    DIRECTION OUTPUT ;
    USE SIGNAL ;
    PORT
      LAYER M5 ;
        RECT  41.232 0 41.256 0.084 ;
    END
  END r_d[213]
  PIN r_d[214]
    DIRECTION OUTPUT ;
    USE SIGNAL ;
    PORT
      LAYER M5 ;
        RECT  41.328 0 41.352 0.084 ;
    END
  END r_d[214]
  PIN r_d[215]
    DIRECTION OUTPUT ;
    USE SIGNAL ;
    PORT
      LAYER M5 ;
        RECT  41.424 0 41.448 0.084 ;
    END
  END r_d[215]
  PIN r_d[216]
    DIRECTION OUTPUT ;
    USE SIGNAL ;
    PORT
      LAYER M5 ;
        RECT  41.52 0 41.544 0.084 ;
    END
  END r_d[216]
  PIN r_d[217]
    DIRECTION OUTPUT ;
    USE SIGNAL ;
    PORT
      LAYER M5 ;
        RECT  41.616 0 41.64 0.084 ;
    END
  END r_d[217]
  PIN r_d[218]
    DIRECTION OUTPUT ;
    USE SIGNAL ;
    PORT
      LAYER M5 ;
        RECT  41.712 0 41.736 0.084 ;
    END
  END r_d[218]
  PIN r_d[219]
    DIRECTION OUTPUT ;
    USE SIGNAL ;
    PORT
      LAYER M5 ;
        RECT  41.808 0 41.832 0.084 ;
    END
  END r_d[219]
  PIN r_d[21]
    DIRECTION OUTPUT ;
    USE SIGNAL ;
    PORT
      LAYER M5 ;
        RECT  50.448 0 50.472 0.084 ;
    END
  END r_d[21]
  PIN r_d[220]
    DIRECTION OUTPUT ;
    USE SIGNAL ;
    PORT
      LAYER M5 ;
        RECT  41.904 0 41.928 0.084 ;
    END
  END r_d[220]
  PIN r_d[221]
    DIRECTION OUTPUT ;
    USE SIGNAL ;
    PORT
      LAYER M5 ;
        RECT  42 0 42.024 0.084 ;
    END
  END r_d[221]
  PIN r_d[222]
    DIRECTION OUTPUT ;
    USE SIGNAL ;
    PORT
      LAYER M5 ;
        RECT  42.096 0 42.12 0.084 ;
    END
  END r_d[222]
  PIN r_d[223]
    DIRECTION OUTPUT ;
    USE SIGNAL ;
    PORT
      LAYER M5 ;
        RECT  29.136 0 29.16 0.084 ;
    END
  END r_d[223]
  PIN r_d[224]
    DIRECTION OUTPUT ;
    USE SIGNAL ;
    PORT
      LAYER M5 ;
        RECT  29.232 0 29.256 0.084 ;
    END
  END r_d[224]
  PIN r_d[225]
    DIRECTION OUTPUT ;
    USE SIGNAL ;
    PORT
      LAYER M5 ;
        RECT  29.328 0 29.352 0.084 ;
    END
  END r_d[225]
  PIN r_d[226]
    DIRECTION OUTPUT ;
    USE SIGNAL ;
    PORT
      LAYER M5 ;
        RECT  29.424 0 29.448 0.084 ;
    END
  END r_d[226]
  PIN r_d[227]
    DIRECTION OUTPUT ;
    USE SIGNAL ;
    PORT
      LAYER M5 ;
        RECT  29.52 0 29.544 0.084 ;
    END
  END r_d[227]
  PIN r_d[228]
    DIRECTION OUTPUT ;
    USE SIGNAL ;
    PORT
      LAYER M5 ;
        RECT  29.616 0 29.64 0.084 ;
    END
  END r_d[228]
  PIN r_d[229]
    DIRECTION OUTPUT ;
    USE SIGNAL ;
    PORT
      LAYER M5 ;
        RECT  29.712 0 29.736 0.084 ;
    END
  END r_d[229]
  PIN r_d[22]
    DIRECTION OUTPUT ;
    USE SIGNAL ;
    PORT
      LAYER M5 ;
        RECT  50.544 0 50.568 0.084 ;
    END
  END r_d[22]
  PIN r_d[230]
    DIRECTION OUTPUT ;
    USE SIGNAL ;
    PORT
      LAYER M5 ;
        RECT  29.808 0 29.832 0.084 ;
    END
  END r_d[230]
  PIN r_d[231]
    DIRECTION OUTPUT ;
    USE SIGNAL ;
    PORT
      LAYER M5 ;
        RECT  29.904 0 29.928 0.084 ;
    END
  END r_d[231]
  PIN r_d[232]
    DIRECTION OUTPUT ;
    USE SIGNAL ;
    PORT
      LAYER M5 ;
        RECT  30 0 30.024 0.084 ;
    END
  END r_d[232]
  PIN r_d[233]
    DIRECTION OUTPUT ;
    USE SIGNAL ;
    PORT
      LAYER M5 ;
        RECT  30.096 0 30.12 0.084 ;
    END
  END r_d[233]
  PIN r_d[234]
    DIRECTION OUTPUT ;
    USE SIGNAL ;
    PORT
      LAYER M5 ;
        RECT  30.192 0 30.216 0.084 ;
    END
  END r_d[234]
  PIN r_d[235]
    DIRECTION OUTPUT ;
    USE SIGNAL ;
    PORT
      LAYER M5 ;
        RECT  30.288 0 30.312 0.084 ;
    END
  END r_d[235]
  PIN r_d[236]
    DIRECTION OUTPUT ;
    USE SIGNAL ;
    PORT
      LAYER M5 ;
        RECT  30.384 0 30.408 0.084 ;
    END
  END r_d[236]
  PIN r_d[237]
    DIRECTION OUTPUT ;
    USE SIGNAL ;
    PORT
      LAYER M5 ;
        RECT  30.48 0 30.504 0.084 ;
    END
  END r_d[237]
  PIN r_d[238]
    DIRECTION OUTPUT ;
    USE SIGNAL ;
    PORT
      LAYER M5 ;
        RECT  30.576 0 30.6 0.084 ;
    END
  END r_d[238]
  PIN r_d[239]
    DIRECTION OUTPUT ;
    USE SIGNAL ;
    PORT
      LAYER M5 ;
        RECT  30.672 0 30.696 0.084 ;
    END
  END r_d[239]
  PIN r_d[23]
    DIRECTION OUTPUT ;
    USE SIGNAL ;
    PORT
      LAYER M5 ;
        RECT  50.64 0 50.664 0.084 ;
    END
  END r_d[23]
  PIN r_d[240]
    DIRECTION OUTPUT ;
    USE SIGNAL ;
    PORT
      LAYER M5 ;
        RECT  30.768 0 30.792 0.084 ;
    END
  END r_d[240]
  PIN r_d[241]
    DIRECTION OUTPUT ;
    USE SIGNAL ;
    PORT
      LAYER M5 ;
        RECT  30.864 0 30.888 0.084 ;
    END
  END r_d[241]
  PIN r_d[242]
    DIRECTION OUTPUT ;
    USE SIGNAL ;
    PORT
      LAYER M5 ;
        RECT  30.96 0 30.984 0.084 ;
    END
  END r_d[242]
  PIN r_d[243]
    DIRECTION OUTPUT ;
    USE SIGNAL ;
    PORT
      LAYER M5 ;
        RECT  31.056 0 31.08 0.084 ;
    END
  END r_d[243]
  PIN r_d[244]
    DIRECTION OUTPUT ;
    USE SIGNAL ;
    PORT
      LAYER M5 ;
        RECT  31.152 0 31.176 0.084 ;
    END
  END r_d[244]
  PIN r_d[245]
    DIRECTION OUTPUT ;
    USE SIGNAL ;
    PORT
      LAYER M5 ;
        RECT  31.248 0 31.272 0.084 ;
    END
  END r_d[245]
  PIN r_d[246]
    DIRECTION OUTPUT ;
    USE SIGNAL ;
    PORT
      LAYER M5 ;
        RECT  31.344 0 31.368 0.084 ;
    END
  END r_d[246]
  PIN r_d[247]
    DIRECTION OUTPUT ;
    USE SIGNAL ;
    PORT
      LAYER M5 ;
        RECT  31.44 0 31.464 0.084 ;
    END
  END r_d[247]
  PIN r_d[248]
    DIRECTION OUTPUT ;
    USE SIGNAL ;
    PORT
      LAYER M5 ;
        RECT  31.536 0 31.56 0.084 ;
    END
  END r_d[248]
  PIN r_d[249]
    DIRECTION OUTPUT ;
    USE SIGNAL ;
    PORT
      LAYER M5 ;
        RECT  31.632 0 31.656 0.084 ;
    END
  END r_d[249]
  PIN r_d[24]
    DIRECTION OUTPUT ;
    USE SIGNAL ;
    PORT
      LAYER M5 ;
        RECT  50.736 0 50.76 0.084 ;
    END
  END r_d[24]
  PIN r_d[250]
    DIRECTION OUTPUT ;
    USE SIGNAL ;
    PORT
      LAYER M5 ;
        RECT  31.728 0 31.752 0.084 ;
    END
  END r_d[250]
  PIN r_d[251]
    DIRECTION OUTPUT ;
    USE SIGNAL ;
    PORT
      LAYER M5 ;
        RECT  31.824 0 31.848 0.084 ;
    END
  END r_d[251]
  PIN r_d[252]
    DIRECTION OUTPUT ;
    USE SIGNAL ;
    PORT
      LAYER M5 ;
        RECT  31.92 0 31.944 0.084 ;
    END
  END r_d[252]
  PIN r_d[253]
    DIRECTION OUTPUT ;
    USE SIGNAL ;
    PORT
      LAYER M5 ;
        RECT  32.016 0 32.04 0.084 ;
    END
  END r_d[253]
  PIN r_d[254]
    DIRECTION OUTPUT ;
    USE SIGNAL ;
    PORT
      LAYER M5 ;
        RECT  32.112 0 32.136 0.084 ;
    END
  END r_d[254]
  PIN r_d[255]
    DIRECTION OUTPUT ;
    USE SIGNAL ;
    PORT
      LAYER M5 ;
        RECT  51.408 0 51.432 0.084 ;
    END
  END r_d[255]
  PIN r_d[256]
    DIRECTION OUTPUT ;
    USE SIGNAL ;
    PORT
      LAYER M5 ;
        RECT  51.504 0 51.528 0.084 ;
    END
  END r_d[256]
  PIN r_d[257]
    DIRECTION OUTPUT ;
    USE SIGNAL ;
    PORT
      LAYER M5 ;
        RECT  51.6 0 51.624 0.084 ;
    END
  END r_d[257]
  PIN r_d[258]
    DIRECTION OUTPUT ;
    USE SIGNAL ;
    PORT
      LAYER M5 ;
        RECT  51.696 0 51.72 0.084 ;
    END
  END r_d[258]
  PIN r_d[259]
    DIRECTION OUTPUT ;
    USE SIGNAL ;
    PORT
      LAYER M5 ;
        RECT  51.792 0 51.816 0.084 ;
    END
  END r_d[259]
  PIN r_d[25]
    DIRECTION OUTPUT ;
    USE SIGNAL ;
    PORT
      LAYER M5 ;
        RECT  50.832 0 50.856 0.084 ;
    END
  END r_d[25]
  PIN r_d[260]
    DIRECTION OUTPUT ;
    USE SIGNAL ;
    PORT
      LAYER M5 ;
        RECT  51.888 0 51.912 0.084 ;
    END
  END r_d[260]
  PIN r_d[261]
    DIRECTION OUTPUT ;
    USE SIGNAL ;
    PORT
      LAYER M5 ;
        RECT  51.984 0 52.008 0.084 ;
    END
  END r_d[261]
  PIN r_d[262]
    DIRECTION OUTPUT ;
    USE SIGNAL ;
    PORT
      LAYER M5 ;
        RECT  52.08 0 52.104 0.084 ;
    END
  END r_d[262]
  PIN r_d[263]
    DIRECTION OUTPUT ;
    USE SIGNAL ;
    PORT
      LAYER M5 ;
        RECT  52.176 0 52.2 0.084 ;
    END
  END r_d[263]
  PIN r_d[264]
    DIRECTION OUTPUT ;
    USE SIGNAL ;
    PORT
      LAYER M5 ;
        RECT  52.272 0 52.296 0.084 ;
    END
  END r_d[264]
  PIN r_d[265]
    DIRECTION OUTPUT ;
    USE SIGNAL ;
    PORT
      LAYER M5 ;
        RECT  52.368 0 52.392 0.084 ;
    END
  END r_d[265]
  PIN r_d[266]
    DIRECTION OUTPUT ;
    USE SIGNAL ;
    PORT
      LAYER M5 ;
        RECT  52.464 0 52.488 0.084 ;
    END
  END r_d[266]
  PIN r_d[267]
    DIRECTION OUTPUT ;
    USE SIGNAL ;
    PORT
      LAYER M5 ;
        RECT  52.56 0 52.584 0.084 ;
    END
  END r_d[267]
  PIN r_d[268]
    DIRECTION OUTPUT ;
    USE SIGNAL ;
    PORT
      LAYER M5 ;
        RECT  52.656 0 52.68 0.084 ;
    END
  END r_d[268]
  PIN r_d[269]
    DIRECTION OUTPUT ;
    USE SIGNAL ;
    PORT
      LAYER M5 ;
        RECT  52.752 0 52.776 0.084 ;
    END
  END r_d[269]
  PIN r_d[26]
    DIRECTION OUTPUT ;
    USE SIGNAL ;
    PORT
      LAYER M5 ;
        RECT  50.928 0 50.952 0.084 ;
    END
  END r_d[26]
  PIN r_d[270]
    DIRECTION OUTPUT ;
    USE SIGNAL ;
    PORT
      LAYER M5 ;
        RECT  52.848 0 52.872 0.084 ;
    END
  END r_d[270]
  PIN r_d[271]
    DIRECTION OUTPUT ;
    USE SIGNAL ;
    PORT
      LAYER M5 ;
        RECT  52.944 0 52.968 0.084 ;
    END
  END r_d[271]
  PIN r_d[272]
    DIRECTION OUTPUT ;
    USE SIGNAL ;
    PORT
      LAYER M5 ;
        RECT  53.04 0 53.064 0.084 ;
    END
  END r_d[272]
  PIN r_d[273]
    DIRECTION OUTPUT ;
    USE SIGNAL ;
    PORT
      LAYER M5 ;
        RECT  53.136 0 53.16 0.084 ;
    END
  END r_d[273]
  PIN r_d[274]
    DIRECTION OUTPUT ;
    USE SIGNAL ;
    PORT
      LAYER M5 ;
        RECT  53.232 0 53.256 0.084 ;
    END
  END r_d[274]
  PIN r_d[275]
    DIRECTION OUTPUT ;
    USE SIGNAL ;
    PORT
      LAYER M5 ;
        RECT  53.328 0 53.352 0.084 ;
    END
  END r_d[275]
  PIN r_d[276]
    DIRECTION OUTPUT ;
    USE SIGNAL ;
    PORT
      LAYER M5 ;
        RECT  53.424 0 53.448 0.084 ;
    END
  END r_d[276]
  PIN r_d[277]
    DIRECTION OUTPUT ;
    USE SIGNAL ;
    PORT
      LAYER M5 ;
        RECT  53.52 0 53.544 0.084 ;
    END
  END r_d[277]
  PIN r_d[278]
    DIRECTION OUTPUT ;
    USE SIGNAL ;
    PORT
      LAYER M5 ;
        RECT  53.616 0 53.64 0.084 ;
    END
  END r_d[278]
  PIN r_d[279]
    DIRECTION OUTPUT ;
    USE SIGNAL ;
    PORT
      LAYER M5 ;
        RECT  53.712 0 53.736 0.084 ;
    END
  END r_d[279]
  PIN r_d[27]
    DIRECTION OUTPUT ;
    USE SIGNAL ;
    PORT
      LAYER M5 ;
        RECT  51.024 0 51.048 0.084 ;
    END
  END r_d[27]
  PIN r_d[280]
    DIRECTION OUTPUT ;
    USE SIGNAL ;
    PORT
      LAYER M5 ;
        RECT  53.808 0 53.832 0.084 ;
    END
  END r_d[280]
  PIN r_d[281]
    DIRECTION OUTPUT ;
    USE SIGNAL ;
    PORT
      LAYER M5 ;
        RECT  53.904 0 53.928 0.084 ;
    END
  END r_d[281]
  PIN r_d[282]
    DIRECTION OUTPUT ;
    USE SIGNAL ;
    PORT
      LAYER M5 ;
        RECT  54 0 54.024 0.084 ;
    END
  END r_d[282]
  PIN r_d[283]
    DIRECTION OUTPUT ;
    USE SIGNAL ;
    PORT
      LAYER M5 ;
        RECT  54.096 0 54.12 0.084 ;
    END
  END r_d[283]
  PIN r_d[284]
    DIRECTION OUTPUT ;
    USE SIGNAL ;
    PORT
      LAYER M5 ;
        RECT  54.192 0 54.216 0.084 ;
    END
  END r_d[284]
  PIN r_d[285]
    DIRECTION OUTPUT ;
    USE SIGNAL ;
    PORT
      LAYER M5 ;
        RECT  54.288 0 54.312 0.084 ;
    END
  END r_d[285]
  PIN r_d[286]
    DIRECTION OUTPUT ;
    USE SIGNAL ;
    PORT
      LAYER M5 ;
        RECT  54.384 0 54.408 0.084 ;
    END
  END r_d[286]
  PIN r_d[287]
    DIRECTION OUTPUT ;
    USE SIGNAL ;
    PORT
      LAYER M5 ;
        RECT  61.392 0 61.416 0.084 ;
    END
  END r_d[287]
  PIN r_d[288]
    DIRECTION OUTPUT ;
    USE SIGNAL ;
    PORT
      LAYER M5 ;
        RECT  61.488 0 61.512 0.084 ;
    END
  END r_d[288]
  PIN r_d[289]
    DIRECTION OUTPUT ;
    USE SIGNAL ;
    PORT
      LAYER M5 ;
        RECT  61.584 0 61.608 0.084 ;
    END
  END r_d[289]
  PIN r_d[28]
    DIRECTION OUTPUT ;
    USE SIGNAL ;
    PORT
      LAYER M5 ;
        RECT  51.12 0 51.144 0.084 ;
    END
  END r_d[28]
  PIN r_d[290]
    DIRECTION OUTPUT ;
    USE SIGNAL ;
    PORT
      LAYER M5 ;
        RECT  61.68 0 61.704 0.084 ;
    END
  END r_d[290]
  PIN r_d[291]
    DIRECTION OUTPUT ;
    USE SIGNAL ;
    PORT
      LAYER M5 ;
        RECT  61.776 0 61.8 0.084 ;
    END
  END r_d[291]
  PIN r_d[292]
    DIRECTION OUTPUT ;
    USE SIGNAL ;
    PORT
      LAYER M5 ;
        RECT  61.872 0 61.896 0.084 ;
    END
  END r_d[292]
  PIN r_d[293]
    DIRECTION OUTPUT ;
    USE SIGNAL ;
    PORT
      LAYER M5 ;
        RECT  61.968 0 61.992 0.084 ;
    END
  END r_d[293]
  PIN r_d[294]
    DIRECTION OUTPUT ;
    USE SIGNAL ;
    PORT
      LAYER M5 ;
        RECT  62.064 0 62.088 0.084 ;
    END
  END r_d[294]
  PIN r_d[295]
    DIRECTION OUTPUT ;
    USE SIGNAL ;
    PORT
      LAYER M5 ;
        RECT  62.16 0 62.184 0.084 ;
    END
  END r_d[295]
  PIN r_d[296]
    DIRECTION OUTPUT ;
    USE SIGNAL ;
    PORT
      LAYER M5 ;
        RECT  62.256 0 62.28 0.084 ;
    END
  END r_d[296]
  PIN r_d[297]
    DIRECTION OUTPUT ;
    USE SIGNAL ;
    PORT
      LAYER M5 ;
        RECT  62.352 0 62.376 0.084 ;
    END
  END r_d[297]
  PIN r_d[298]
    DIRECTION OUTPUT ;
    USE SIGNAL ;
    PORT
      LAYER M5 ;
        RECT  62.448 0 62.472 0.084 ;
    END
  END r_d[298]
  PIN r_d[299]
    DIRECTION OUTPUT ;
    USE SIGNAL ;
    PORT
      LAYER M5 ;
        RECT  62.544 0 62.568 0.084 ;
    END
  END r_d[299]
  PIN r_d[29]
    DIRECTION OUTPUT ;
    USE SIGNAL ;
    PORT
      LAYER M5 ;
        RECT  51.216 0 51.24 0.084 ;
    END
  END r_d[29]
  PIN r_d[2]
    DIRECTION OUTPUT ;
    USE SIGNAL ;
    PORT
      LAYER M5 ;
        RECT  48.624 0 48.648 0.084 ;
    END
  END r_d[2]
  PIN r_d[300]
    DIRECTION OUTPUT ;
    USE SIGNAL ;
    PORT
      LAYER M5 ;
        RECT  62.64 0 62.664 0.084 ;
    END
  END r_d[300]
  PIN r_d[301]
    DIRECTION OUTPUT ;
    USE SIGNAL ;
    PORT
      LAYER M5 ;
        RECT  62.736 0 62.76 0.084 ;
    END
  END r_d[301]
  PIN r_d[302]
    DIRECTION OUTPUT ;
    USE SIGNAL ;
    PORT
      LAYER M5 ;
        RECT  62.832 0 62.856 0.084 ;
    END
  END r_d[302]
  PIN r_d[303]
    DIRECTION OUTPUT ;
    USE SIGNAL ;
    PORT
      LAYER M5 ;
        RECT  62.928 0 62.952 0.084 ;
    END
  END r_d[303]
  PIN r_d[304]
    DIRECTION OUTPUT ;
    USE SIGNAL ;
    PORT
      LAYER M5 ;
        RECT  63.024 0 63.048 0.084 ;
    END
  END r_d[304]
  PIN r_d[305]
    DIRECTION OUTPUT ;
    USE SIGNAL ;
    PORT
      LAYER M5 ;
        RECT  63.12 0 63.144 0.084 ;
    END
  END r_d[305]
  PIN r_d[306]
    DIRECTION OUTPUT ;
    USE SIGNAL ;
    PORT
      LAYER M5 ;
        RECT  63.216 0 63.24 0.084 ;
    END
  END r_d[306]
  PIN r_d[307]
    DIRECTION OUTPUT ;
    USE SIGNAL ;
    PORT
      LAYER M5 ;
        RECT  63.312 0 63.336 0.084 ;
    END
  END r_d[307]
  PIN r_d[308]
    DIRECTION OUTPUT ;
    USE SIGNAL ;
    PORT
      LAYER M5 ;
        RECT  63.408 0 63.432 0.084 ;
    END
  END r_d[308]
  PIN r_d[309]
    DIRECTION OUTPUT ;
    USE SIGNAL ;
    PORT
      LAYER M5 ;
        RECT  63.504 0 63.528 0.084 ;
    END
  END r_d[309]
  PIN r_d[30]
    DIRECTION OUTPUT ;
    USE SIGNAL ;
    PORT
      LAYER M5 ;
        RECT  51.312 0 51.336 0.084 ;
    END
  END r_d[30]
  PIN r_d[310]
    DIRECTION OUTPUT ;
    USE SIGNAL ;
    PORT
      LAYER M5 ;
        RECT  63.6 0 63.624 0.084 ;
    END
  END r_d[310]
  PIN r_d[311]
    DIRECTION OUTPUT ;
    USE SIGNAL ;
    PORT
      LAYER M5 ;
        RECT  63.696 0 63.72 0.084 ;
    END
  END r_d[311]
  PIN r_d[312]
    DIRECTION OUTPUT ;
    USE SIGNAL ;
    PORT
      LAYER M5 ;
        RECT  63.792 0 63.816 0.084 ;
    END
  END r_d[312]
  PIN r_d[313]
    DIRECTION OUTPUT ;
    USE SIGNAL ;
    PORT
      LAYER M5 ;
        RECT  63.888 0 63.912 0.084 ;
    END
  END r_d[313]
  PIN r_d[314]
    DIRECTION OUTPUT ;
    USE SIGNAL ;
    PORT
      LAYER M5 ;
        RECT  63.984 0 64.008 0.084 ;
    END
  END r_d[314]
  PIN r_d[315]
    DIRECTION OUTPUT ;
    USE SIGNAL ;
    PORT
      LAYER M5 ;
        RECT  64.08 0 64.104 0.084 ;
    END
  END r_d[315]
  PIN r_d[316]
    DIRECTION OUTPUT ;
    USE SIGNAL ;
    PORT
      LAYER M5 ;
        RECT  64.176 0 64.2 0.084 ;
    END
  END r_d[316]
  PIN r_d[317]
    DIRECTION OUTPUT ;
    USE SIGNAL ;
    PORT
      LAYER M5 ;
        RECT  64.272 0 64.296 0.084 ;
    END
  END r_d[317]
  PIN r_d[318]
    DIRECTION OUTPUT ;
    USE SIGNAL ;
    PORT
      LAYER M5 ;
        RECT  64.368 0 64.392 0.084 ;
    END
  END r_d[318]
  PIN r_d[319]
    DIRECTION OUTPUT ;
    USE SIGNAL ;
    PORT
      LAYER M5 ;
        RECT  67.536 0 67.56 0.084 ;
    END
  END r_d[319]
  PIN r_d[31]
    DIRECTION OUTPUT ;
    USE SIGNAL ;
    PORT
      LAYER M5 ;
        RECT  64.464 0 64.488 0.084 ;
    END
  END r_d[31]
  PIN r_d[320]
    DIRECTION OUTPUT ;
    USE SIGNAL ;
    PORT
      LAYER M5 ;
        RECT  67.632 0 67.656 0.084 ;
    END
  END r_d[320]
  PIN r_d[321]
    DIRECTION OUTPUT ;
    USE SIGNAL ;
    PORT
      LAYER M5 ;
        RECT  67.728 0 67.752 0.084 ;
    END
  END r_d[321]
  PIN r_d[322]
    DIRECTION OUTPUT ;
    USE SIGNAL ;
    PORT
      LAYER M5 ;
        RECT  67.824 0 67.848 0.084 ;
    END
  END r_d[322]
  PIN r_d[323]
    DIRECTION OUTPUT ;
    USE SIGNAL ;
    PORT
      LAYER M5 ;
        RECT  67.92 0 67.944 0.084 ;
    END
  END r_d[323]
  PIN r_d[324]
    DIRECTION OUTPUT ;
    USE SIGNAL ;
    PORT
      LAYER M5 ;
        RECT  68.016 0 68.04 0.084 ;
    END
  END r_d[324]
  PIN r_d[325]
    DIRECTION OUTPUT ;
    USE SIGNAL ;
    PORT
      LAYER M5 ;
        RECT  68.112 0 68.136 0.084 ;
    END
  END r_d[325]
  PIN r_d[326]
    DIRECTION OUTPUT ;
    USE SIGNAL ;
    PORT
      LAYER M5 ;
        RECT  68.208 0 68.232 0.084 ;
    END
  END r_d[326]
  PIN r_d[327]
    DIRECTION OUTPUT ;
    USE SIGNAL ;
    PORT
      LAYER M5 ;
        RECT  68.304 0 68.328 0.084 ;
    END
  END r_d[327]
  PIN r_d[328]
    DIRECTION OUTPUT ;
    USE SIGNAL ;
    PORT
      LAYER M5 ;
        RECT  68.4 0 68.424 0.084 ;
    END
  END r_d[328]
  PIN r_d[329]
    DIRECTION OUTPUT ;
    USE SIGNAL ;
    PORT
      LAYER M5 ;
        RECT  68.496 0 68.52 0.084 ;
    END
  END r_d[329]
  PIN r_d[32]
    DIRECTION OUTPUT ;
    USE SIGNAL ;
    PORT
      LAYER M5 ;
        RECT  64.56 0 64.584 0.084 ;
    END
  END r_d[32]
  PIN r_d[330]
    DIRECTION OUTPUT ;
    USE SIGNAL ;
    PORT
      LAYER M5 ;
        RECT  68.592 0 68.616 0.084 ;
    END
  END r_d[330]
  PIN r_d[331]
    DIRECTION OUTPUT ;
    USE SIGNAL ;
    PORT
      LAYER M5 ;
        RECT  68.688 0 68.712 0.084 ;
    END
  END r_d[331]
  PIN r_d[332]
    DIRECTION OUTPUT ;
    USE SIGNAL ;
    PORT
      LAYER M5 ;
        RECT  68.784 0 68.808 0.084 ;
    END
  END r_d[332]
  PIN r_d[333]
    DIRECTION OUTPUT ;
    USE SIGNAL ;
    PORT
      LAYER M5 ;
        RECT  68.88 0 68.904 0.084 ;
    END
  END r_d[333]
  PIN r_d[334]
    DIRECTION OUTPUT ;
    USE SIGNAL ;
    PORT
      LAYER M5 ;
        RECT  68.976 0 69 0.084 ;
    END
  END r_d[334]
  PIN r_d[335]
    DIRECTION OUTPUT ;
    USE SIGNAL ;
    PORT
      LAYER M5 ;
        RECT  69.072 0 69.096 0.084 ;
    END
  END r_d[335]
  PIN r_d[336]
    DIRECTION OUTPUT ;
    USE SIGNAL ;
    PORT
      LAYER M5 ;
        RECT  69.168 0 69.192 0.084 ;
    END
  END r_d[336]
  PIN r_d[337]
    DIRECTION OUTPUT ;
    USE SIGNAL ;
    PORT
      LAYER M5 ;
        RECT  69.264 0 69.288 0.084 ;
    END
  END r_d[337]
  PIN r_d[338]
    DIRECTION OUTPUT ;
    USE SIGNAL ;
    PORT
      LAYER M5 ;
        RECT  69.36 0 69.384 0.084 ;
    END
  END r_d[338]
  PIN r_d[339]
    DIRECTION OUTPUT ;
    USE SIGNAL ;
    PORT
      LAYER M5 ;
        RECT  69.456 0 69.48 0.084 ;
    END
  END r_d[339]
  PIN r_d[33]
    DIRECTION OUTPUT ;
    USE SIGNAL ;
    PORT
      LAYER M5 ;
        RECT  64.656 0 64.68 0.084 ;
    END
  END r_d[33]
  PIN r_d[340]
    DIRECTION OUTPUT ;
    USE SIGNAL ;
    PORT
      LAYER M5 ;
        RECT  69.552 0 69.576 0.084 ;
    END
  END r_d[340]
  PIN r_d[341]
    DIRECTION OUTPUT ;
    USE SIGNAL ;
    PORT
      LAYER M5 ;
        RECT  69.648 0 69.672 0.084 ;
    END
  END r_d[341]
  PIN r_d[342]
    DIRECTION OUTPUT ;
    USE SIGNAL ;
    PORT
      LAYER M5 ;
        RECT  69.744 0 69.768 0.084 ;
    END
  END r_d[342]
  PIN r_d[343]
    DIRECTION OUTPUT ;
    USE SIGNAL ;
    PORT
      LAYER M5 ;
        RECT  69.84 0 69.864 0.084 ;
    END
  END r_d[343]
  PIN r_d[344]
    DIRECTION OUTPUT ;
    USE SIGNAL ;
    PORT
      LAYER M5 ;
        RECT  69.936 0 69.96 0.084 ;
    END
  END r_d[344]
  PIN r_d[345]
    DIRECTION OUTPUT ;
    USE SIGNAL ;
    PORT
      LAYER M5 ;
        RECT  70.032 0 70.056 0.084 ;
    END
  END r_d[345]
  PIN r_d[346]
    DIRECTION OUTPUT ;
    USE SIGNAL ;
    PORT
      LAYER M5 ;
        RECT  70.128 0 70.152 0.084 ;
    END
  END r_d[346]
  PIN r_d[347]
    DIRECTION OUTPUT ;
    USE SIGNAL ;
    PORT
      LAYER M5 ;
        RECT  70.224 0 70.248 0.084 ;
    END
  END r_d[347]
  PIN r_d[348]
    DIRECTION OUTPUT ;
    USE SIGNAL ;
    PORT
      LAYER M5 ;
        RECT  70.32 0 70.344 0.084 ;
    END
  END r_d[348]
  PIN r_d[349]
    DIRECTION OUTPUT ;
    USE SIGNAL ;
    PORT
      LAYER M5 ;
        RECT  70.416 0 70.44 0.084 ;
    END
  END r_d[349]
  PIN r_d[34]
    DIRECTION OUTPUT ;
    USE SIGNAL ;
    PORT
      LAYER M5 ;
        RECT  64.752 0 64.776 0.084 ;
    END
  END r_d[34]
  PIN r_d[350]
    DIRECTION OUTPUT ;
    USE SIGNAL ;
    PORT
      LAYER M5 ;
        RECT  70.512 0 70.536 0.084 ;
    END
  END r_d[350]
  PIN r_d[351]
    DIRECTION OUTPUT ;
    USE SIGNAL ;
    PORT
      LAYER M5 ;
        RECT  58.32 0 58.344 0.084 ;
    END
  END r_d[351]
  PIN r_d[352]
    DIRECTION OUTPUT ;
    USE SIGNAL ;
    PORT
      LAYER M5 ;
        RECT  58.416 0 58.44 0.084 ;
    END
  END r_d[352]
  PIN r_d[353]
    DIRECTION OUTPUT ;
    USE SIGNAL ;
    PORT
      LAYER M5 ;
        RECT  58.512 0 58.536 0.084 ;
    END
  END r_d[353]
  PIN r_d[354]
    DIRECTION OUTPUT ;
    USE SIGNAL ;
    PORT
      LAYER M5 ;
        RECT  58.608 0 58.632 0.084 ;
    END
  END r_d[354]
  PIN r_d[355]
    DIRECTION OUTPUT ;
    USE SIGNAL ;
    PORT
      LAYER M5 ;
        RECT  58.704 0 58.728 0.084 ;
    END
  END r_d[355]
  PIN r_d[356]
    DIRECTION OUTPUT ;
    USE SIGNAL ;
    PORT
      LAYER M5 ;
        RECT  58.8 0 58.824 0.084 ;
    END
  END r_d[356]
  PIN r_d[357]
    DIRECTION OUTPUT ;
    USE SIGNAL ;
    PORT
      LAYER M5 ;
        RECT  58.896 0 58.92 0.084 ;
    END
  END r_d[357]
  PIN r_d[358]
    DIRECTION OUTPUT ;
    USE SIGNAL ;
    PORT
      LAYER M5 ;
        RECT  58.992 0 59.016 0.084 ;
    END
  END r_d[358]
  PIN r_d[359]
    DIRECTION OUTPUT ;
    USE SIGNAL ;
    PORT
      LAYER M5 ;
        RECT  59.088 0 59.112 0.084 ;
    END
  END r_d[359]
  PIN r_d[35]
    DIRECTION OUTPUT ;
    USE SIGNAL ;
    PORT
      LAYER M5 ;
        RECT  64.848 0 64.872 0.084 ;
    END
  END r_d[35]
  PIN r_d[360]
    DIRECTION OUTPUT ;
    USE SIGNAL ;
    PORT
      LAYER M5 ;
        RECT  59.184 0 59.208 0.084 ;
    END
  END r_d[360]
  PIN r_d[361]
    DIRECTION OUTPUT ;
    USE SIGNAL ;
    PORT
      LAYER M5 ;
        RECT  59.28 0 59.304 0.084 ;
    END
  END r_d[361]
  PIN r_d[362]
    DIRECTION OUTPUT ;
    USE SIGNAL ;
    PORT
      LAYER M5 ;
        RECT  59.376 0 59.4 0.084 ;
    END
  END r_d[362]
  PIN r_d[363]
    DIRECTION OUTPUT ;
    USE SIGNAL ;
    PORT
      LAYER M5 ;
        RECT  59.472 0 59.496 0.084 ;
    END
  END r_d[363]
  PIN r_d[364]
    DIRECTION OUTPUT ;
    USE SIGNAL ;
    PORT
      LAYER M5 ;
        RECT  59.568 0 59.592 0.084 ;
    END
  END r_d[364]
  PIN r_d[365]
    DIRECTION OUTPUT ;
    USE SIGNAL ;
    PORT
      LAYER M5 ;
        RECT  59.664 0 59.688 0.084 ;
    END
  END r_d[365]
  PIN r_d[366]
    DIRECTION OUTPUT ;
    USE SIGNAL ;
    PORT
      LAYER M5 ;
        RECT  59.76 0 59.784 0.084 ;
    END
  END r_d[366]
  PIN r_d[367]
    DIRECTION OUTPUT ;
    USE SIGNAL ;
    PORT
      LAYER M5 ;
        RECT  59.856 0 59.88 0.084 ;
    END
  END r_d[367]
  PIN r_d[368]
    DIRECTION OUTPUT ;
    USE SIGNAL ;
    PORT
      LAYER M5 ;
        RECT  59.952 0 59.976 0.084 ;
    END
  END r_d[368]
  PIN r_d[369]
    DIRECTION OUTPUT ;
    USE SIGNAL ;
    PORT
      LAYER M5 ;
        RECT  60.048 0 60.072 0.084 ;
    END
  END r_d[369]
  PIN r_d[36]
    DIRECTION OUTPUT ;
    USE SIGNAL ;
    PORT
      LAYER M5 ;
        RECT  64.944 0 64.968 0.084 ;
    END
  END r_d[36]
  PIN r_d[370]
    DIRECTION OUTPUT ;
    USE SIGNAL ;
    PORT
      LAYER M5 ;
        RECT  60.144 0 60.168 0.084 ;
    END
  END r_d[370]
  PIN r_d[371]
    DIRECTION OUTPUT ;
    USE SIGNAL ;
    PORT
      LAYER M5 ;
        RECT  60.24 0 60.264 0.084 ;
    END
  END r_d[371]
  PIN r_d[372]
    DIRECTION OUTPUT ;
    USE SIGNAL ;
    PORT
      LAYER M5 ;
        RECT  60.336 0 60.36 0.084 ;
    END
  END r_d[372]
  PIN r_d[373]
    DIRECTION OUTPUT ;
    USE SIGNAL ;
    PORT
      LAYER M5 ;
        RECT  60.432 0 60.456 0.084 ;
    END
  END r_d[373]
  PIN r_d[374]
    DIRECTION OUTPUT ;
    USE SIGNAL ;
    PORT
      LAYER M5 ;
        RECT  60.528 0 60.552 0.084 ;
    END
  END r_d[374]
  PIN r_d[375]
    DIRECTION OUTPUT ;
    USE SIGNAL ;
    PORT
      LAYER M5 ;
        RECT  60.624 0 60.648 0.084 ;
    END
  END r_d[375]
  PIN r_d[376]
    DIRECTION OUTPUT ;
    USE SIGNAL ;
    PORT
      LAYER M5 ;
        RECT  60.72 0 60.744 0.084 ;
    END
  END r_d[376]
  PIN r_d[377]
    DIRECTION OUTPUT ;
    USE SIGNAL ;
    PORT
      LAYER M5 ;
        RECT  60.816 0 60.84 0.084 ;
    END
  END r_d[377]
  PIN r_d[378]
    DIRECTION OUTPUT ;
    USE SIGNAL ;
    PORT
      LAYER M5 ;
        RECT  60.912 0 60.936 0.084 ;
    END
  END r_d[378]
  PIN r_d[379]
    DIRECTION OUTPUT ;
    USE SIGNAL ;
    PORT
      LAYER M5 ;
        RECT  61.008 0 61.032 0.084 ;
    END
  END r_d[379]
  PIN r_d[37]
    DIRECTION OUTPUT ;
    USE SIGNAL ;
    PORT
      LAYER M5 ;
        RECT  65.04 0 65.064 0.084 ;
    END
  END r_d[37]
  PIN r_d[380]
    DIRECTION OUTPUT ;
    USE SIGNAL ;
    PORT
      LAYER M5 ;
        RECT  61.104 0 61.128 0.084 ;
    END
  END r_d[380]
  PIN r_d[381]
    DIRECTION OUTPUT ;
    USE SIGNAL ;
    PORT
      LAYER M5 ;
        RECT  61.2 0 61.224 0.084 ;
    END
  END r_d[381]
  PIN r_d[382]
    DIRECTION OUTPUT ;
    USE SIGNAL ;
    PORT
      LAYER M5 ;
        RECT  61.296 0 61.32 0.084 ;
    END
  END r_d[382]
  PIN r_d[383]
    DIRECTION OUTPUT ;
    USE SIGNAL ;
    PORT
      LAYER M5 ;
        RECT  19.92 0 19.944 0.084 ;
    END
  END r_d[383]
  PIN r_d[384]
    DIRECTION OUTPUT ;
    USE SIGNAL ;
    PORT
      LAYER M5 ;
        RECT  20.016 0 20.04 0.084 ;
    END
  END r_d[384]
  PIN r_d[385]
    DIRECTION OUTPUT ;
    USE SIGNAL ;
    PORT
      LAYER M5 ;
        RECT  20.112 0 20.136 0.084 ;
    END
  END r_d[385]
  PIN r_d[386]
    DIRECTION OUTPUT ;
    USE SIGNAL ;
    PORT
      LAYER M5 ;
        RECT  20.208 0 20.232 0.084 ;
    END
  END r_d[386]
  PIN r_d[387]
    DIRECTION OUTPUT ;
    USE SIGNAL ;
    PORT
      LAYER M5 ;
        RECT  20.304 0 20.328 0.084 ;
    END
  END r_d[387]
  PIN r_d[388]
    DIRECTION OUTPUT ;
    USE SIGNAL ;
    PORT
      LAYER M5 ;
        RECT  20.4 0 20.424 0.084 ;
    END
  END r_d[388]
  PIN r_d[389]
    DIRECTION OUTPUT ;
    USE SIGNAL ;
    PORT
      LAYER M5 ;
        RECT  20.496 0 20.52 0.084 ;
    END
  END r_d[389]
  PIN r_d[38]
    DIRECTION OUTPUT ;
    USE SIGNAL ;
    PORT
      LAYER M5 ;
        RECT  65.136 0 65.16 0.084 ;
    END
  END r_d[38]
  PIN r_d[390]
    DIRECTION OUTPUT ;
    USE SIGNAL ;
    PORT
      LAYER M5 ;
        RECT  20.592 0 20.616 0.084 ;
    END
  END r_d[390]
  PIN r_d[391]
    DIRECTION OUTPUT ;
    USE SIGNAL ;
    PORT
      LAYER M5 ;
        RECT  20.688 0 20.712 0.084 ;
    END
  END r_d[391]
  PIN r_d[392]
    DIRECTION OUTPUT ;
    USE SIGNAL ;
    PORT
      LAYER M5 ;
        RECT  20.784 0 20.808 0.084 ;
    END
  END r_d[392]
  PIN r_d[393]
    DIRECTION OUTPUT ;
    USE SIGNAL ;
    PORT
      LAYER M5 ;
        RECT  20.88 0 20.904 0.084 ;
    END
  END r_d[393]
  PIN r_d[394]
    DIRECTION OUTPUT ;
    USE SIGNAL ;
    PORT
      LAYER M5 ;
        RECT  20.976 0 21 0.084 ;
    END
  END r_d[394]
  PIN r_d[395]
    DIRECTION OUTPUT ;
    USE SIGNAL ;
    PORT
      LAYER M5 ;
        RECT  21.072 0 21.096 0.084 ;
    END
  END r_d[395]
  PIN r_d[396]
    DIRECTION OUTPUT ;
    USE SIGNAL ;
    PORT
      LAYER M5 ;
        RECT  21.168 0 21.192 0.084 ;
    END
  END r_d[396]
  PIN r_d[397]
    DIRECTION OUTPUT ;
    USE SIGNAL ;
    PORT
      LAYER M5 ;
        RECT  21.264 0 21.288 0.084 ;
    END
  END r_d[397]
  PIN r_d[398]
    DIRECTION OUTPUT ;
    USE SIGNAL ;
    PORT
      LAYER M5 ;
        RECT  21.36 0 21.384 0.084 ;
    END
  END r_d[398]
  PIN r_d[399]
    DIRECTION OUTPUT ;
    USE SIGNAL ;
    PORT
      LAYER M5 ;
        RECT  21.456 0 21.48 0.084 ;
    END
  END r_d[399]
  PIN r_d[39]
    DIRECTION OUTPUT ;
    USE SIGNAL ;
    PORT
      LAYER M5 ;
        RECT  65.232 0 65.256 0.084 ;
    END
  END r_d[39]
  PIN r_d[3]
    DIRECTION OUTPUT ;
    USE SIGNAL ;
    PORT
      LAYER M5 ;
        RECT  48.72 0 48.744 0.084 ;
    END
  END r_d[3]
  PIN r_d[400]
    DIRECTION OUTPUT ;
    USE SIGNAL ;
    PORT
      LAYER M5 ;
        RECT  21.552 0 21.576 0.084 ;
    END
  END r_d[400]
  PIN r_d[401]
    DIRECTION OUTPUT ;
    USE SIGNAL ;
    PORT
      LAYER M5 ;
        RECT  21.648 0 21.672 0.084 ;
    END
  END r_d[401]
  PIN r_d[402]
    DIRECTION OUTPUT ;
    USE SIGNAL ;
    PORT
      LAYER M5 ;
        RECT  21.744 0 21.768 0.084 ;
    END
  END r_d[402]
  PIN r_d[403]
    DIRECTION OUTPUT ;
    USE SIGNAL ;
    PORT
      LAYER M5 ;
        RECT  21.84 0 21.864 0.084 ;
    END
  END r_d[403]
  PIN r_d[404]
    DIRECTION OUTPUT ;
    USE SIGNAL ;
    PORT
      LAYER M5 ;
        RECT  21.936 0 21.96 0.084 ;
    END
  END r_d[404]
  PIN r_d[405]
    DIRECTION OUTPUT ;
    USE SIGNAL ;
    PORT
      LAYER M5 ;
        RECT  22.032 0 22.056 0.084 ;
    END
  END r_d[405]
  PIN r_d[406]
    DIRECTION OUTPUT ;
    USE SIGNAL ;
    PORT
      LAYER M5 ;
        RECT  22.128 0 22.152 0.084 ;
    END
  END r_d[406]
  PIN r_d[407]
    DIRECTION OUTPUT ;
    USE SIGNAL ;
    PORT
      LAYER M5 ;
        RECT  22.224 0 22.248 0.084 ;
    END
  END r_d[407]
  PIN r_d[408]
    DIRECTION OUTPUT ;
    USE SIGNAL ;
    PORT
      LAYER M5 ;
        RECT  22.32 0 22.344 0.084 ;
    END
  END r_d[408]
  PIN r_d[409]
    DIRECTION OUTPUT ;
    USE SIGNAL ;
    PORT
      LAYER M5 ;
        RECT  22.416 0 22.44 0.084 ;
    END
  END r_d[409]
  PIN r_d[40]
    DIRECTION OUTPUT ;
    USE SIGNAL ;
    PORT
      LAYER M5 ;
        RECT  65.328 0 65.352 0.084 ;
    END
  END r_d[40]
  PIN r_d[410]
    DIRECTION OUTPUT ;
    USE SIGNAL ;
    PORT
      LAYER M5 ;
        RECT  22.512 0 22.536 0.084 ;
    END
  END r_d[410]
  PIN r_d[411]
    DIRECTION OUTPUT ;
    USE SIGNAL ;
    PORT
      LAYER M5 ;
        RECT  22.608 0 22.632 0.084 ;
    END
  END r_d[411]
  PIN r_d[412]
    DIRECTION OUTPUT ;
    USE SIGNAL ;
    PORT
      LAYER M5 ;
        RECT  22.704 0 22.728 0.084 ;
    END
  END r_d[412]
  PIN r_d[413]
    DIRECTION OUTPUT ;
    USE SIGNAL ;
    PORT
      LAYER M5 ;
        RECT  22.8 0 22.824 0.084 ;
    END
  END r_d[413]
  PIN r_d[414]
    DIRECTION OUTPUT ;
    USE SIGNAL ;
    PORT
      LAYER M5 ;
        RECT  22.896 0 22.92 0.084 ;
    END
  END r_d[414]
  PIN r_d[415]
    DIRECTION OUTPUT ;
    USE SIGNAL ;
    PORT
      LAYER M5 ;
        RECT  22.992 0 23.016 0.084 ;
    END
  END r_d[415]
  PIN r_d[416]
    DIRECTION OUTPUT ;
    USE SIGNAL ;
    PORT
      LAYER M5 ;
        RECT  23.088 0 23.112 0.084 ;
    END
  END r_d[416]
  PIN r_d[417]
    DIRECTION OUTPUT ;
    USE SIGNAL ;
    PORT
      LAYER M5 ;
        RECT  23.184 0 23.208 0.084 ;
    END
  END r_d[417]
  PIN r_d[418]
    DIRECTION OUTPUT ;
    USE SIGNAL ;
    PORT
      LAYER M5 ;
        RECT  23.28 0 23.304 0.084 ;
    END
  END r_d[418]
  PIN r_d[419]
    DIRECTION OUTPUT ;
    USE SIGNAL ;
    PORT
      LAYER M5 ;
        RECT  23.376 0 23.4 0.084 ;
    END
  END r_d[419]
  PIN r_d[41]
    DIRECTION OUTPUT ;
    USE SIGNAL ;
    PORT
      LAYER M5 ;
        RECT  65.424 0 65.448 0.084 ;
    END
  END r_d[41]
  PIN r_d[420]
    DIRECTION OUTPUT ;
    USE SIGNAL ;
    PORT
      LAYER M5 ;
        RECT  23.472 0 23.496 0.084 ;
    END
  END r_d[420]
  PIN r_d[421]
    DIRECTION OUTPUT ;
    USE SIGNAL ;
    PORT
      LAYER M5 ;
        RECT  23.568 0 23.592 0.084 ;
    END
  END r_d[421]
  PIN r_d[422]
    DIRECTION OUTPUT ;
    USE SIGNAL ;
    PORT
      LAYER M5 ;
        RECT  23.664 0 23.688 0.084 ;
    END
  END r_d[422]
  PIN r_d[423]
    DIRECTION OUTPUT ;
    USE SIGNAL ;
    PORT
      LAYER M5 ;
        RECT  23.76 0 23.784 0.084 ;
    END
  END r_d[423]
  PIN r_d[424]
    DIRECTION OUTPUT ;
    USE SIGNAL ;
    PORT
      LAYER M5 ;
        RECT  23.856 0 23.88 0.084 ;
    END
  END r_d[424]
  PIN r_d[425]
    DIRECTION OUTPUT ;
    USE SIGNAL ;
    PORT
      LAYER M5 ;
        RECT  23.952 0 23.976 0.084 ;
    END
  END r_d[425]
  PIN r_d[426]
    DIRECTION OUTPUT ;
    USE SIGNAL ;
    PORT
      LAYER M5 ;
        RECT  24.048 0 24.072 0.084 ;
    END
  END r_d[426]
  PIN r_d[427]
    DIRECTION OUTPUT ;
    USE SIGNAL ;
    PORT
      LAYER M5 ;
        RECT  24.144 0 24.168 0.084 ;
    END
  END r_d[427]
  PIN r_d[428]
    DIRECTION OUTPUT ;
    USE SIGNAL ;
    PORT
      LAYER M5 ;
        RECT  24.24 0 24.264 0.084 ;
    END
  END r_d[428]
  PIN r_d[429]
    DIRECTION OUTPUT ;
    USE SIGNAL ;
    PORT
      LAYER M5 ;
        RECT  24.336 0 24.36 0.084 ;
    END
  END r_d[429]
  PIN r_d[42]
    DIRECTION OUTPUT ;
    USE SIGNAL ;
    PORT
      LAYER M5 ;
        RECT  65.52 0 65.544 0.084 ;
    END
  END r_d[42]
  PIN r_d[430]
    DIRECTION OUTPUT ;
    USE SIGNAL ;
    PORT
      LAYER M5 ;
        RECT  24.432 0 24.456 0.084 ;
    END
  END r_d[430]
  PIN r_d[431]
    DIRECTION OUTPUT ;
    USE SIGNAL ;
    PORT
      LAYER M5 ;
        RECT  24.528 0 24.552 0.084 ;
    END
  END r_d[431]
  PIN r_d[432]
    DIRECTION OUTPUT ;
    USE SIGNAL ;
    PORT
      LAYER M5 ;
        RECT  24.624 0 24.648 0.084 ;
    END
  END r_d[432]
  PIN r_d[433]
    DIRECTION OUTPUT ;
    USE SIGNAL ;
    PORT
      LAYER M5 ;
        RECT  24.72 0 24.744 0.084 ;
    END
  END r_d[433]
  PIN r_d[434]
    DIRECTION OUTPUT ;
    USE SIGNAL ;
    PORT
      LAYER M5 ;
        RECT  24.816 0 24.84 0.084 ;
    END
  END r_d[434]
  PIN r_d[435]
    DIRECTION OUTPUT ;
    USE SIGNAL ;
    PORT
      LAYER M5 ;
        RECT  24.912 0 24.936 0.084 ;
    END
  END r_d[435]
  PIN r_d[436]
    DIRECTION OUTPUT ;
    USE SIGNAL ;
    PORT
      LAYER M5 ;
        RECT  25.008 0 25.032 0.084 ;
    END
  END r_d[436]
  PIN r_d[437]
    DIRECTION OUTPUT ;
    USE SIGNAL ;
    PORT
      LAYER M5 ;
        RECT  25.104 0 25.128 0.084 ;
    END
  END r_d[437]
  PIN r_d[438]
    DIRECTION OUTPUT ;
    USE SIGNAL ;
    PORT
      LAYER M5 ;
        RECT  25.2 0 25.224 0.084 ;
    END
  END r_d[438]
  PIN r_d[439]
    DIRECTION OUTPUT ;
    USE SIGNAL ;
    PORT
      LAYER M5 ;
        RECT  25.296 0 25.32 0.084 ;
    END
  END r_d[439]
  PIN r_d[43]
    DIRECTION OUTPUT ;
    USE SIGNAL ;
    PORT
      LAYER M5 ;
        RECT  65.616 0 65.64 0.084 ;
    END
  END r_d[43]
  PIN r_d[440]
    DIRECTION OUTPUT ;
    USE SIGNAL ;
    PORT
      LAYER M5 ;
        RECT  25.392 0 25.416 0.084 ;
    END
  END r_d[440]
  PIN r_d[441]
    DIRECTION OUTPUT ;
    USE SIGNAL ;
    PORT
      LAYER M5 ;
        RECT  25.488 0 25.512 0.084 ;
    END
  END r_d[441]
  PIN r_d[442]
    DIRECTION OUTPUT ;
    USE SIGNAL ;
    PORT
      LAYER M5 ;
        RECT  25.584 0 25.608 0.084 ;
    END
  END r_d[442]
  PIN r_d[443]
    DIRECTION OUTPUT ;
    USE SIGNAL ;
    PORT
      LAYER M5 ;
        RECT  25.68 0 25.704 0.084 ;
    END
  END r_d[443]
  PIN r_d[444]
    DIRECTION OUTPUT ;
    USE SIGNAL ;
    PORT
      LAYER M5 ;
        RECT  25.776 0 25.8 0.084 ;
    END
  END r_d[444]
  PIN r_d[445]
    DIRECTION OUTPUT ;
    USE SIGNAL ;
    PORT
      LAYER M5 ;
        RECT  25.872 0 25.896 0.084 ;
    END
  END r_d[445]
  PIN r_d[446]
    DIRECTION OUTPUT ;
    USE SIGNAL ;
    PORT
      LAYER M5 ;
        RECT  25.968 0 25.992 0.084 ;
    END
  END r_d[446]
  PIN r_d[447]
    DIRECTION OUTPUT ;
    USE SIGNAL ;
    PORT
      LAYER M5 ;
        RECT  35.28 0 35.304 0.084 ;
    END
  END r_d[447]
  PIN r_d[448]
    DIRECTION OUTPUT ;
    USE SIGNAL ;
    PORT
      LAYER M5 ;
        RECT  35.376 0 35.4 0.084 ;
    END
  END r_d[448]
  PIN r_d[449]
    DIRECTION OUTPUT ;
    USE SIGNAL ;
    PORT
      LAYER M5 ;
        RECT  35.472 0 35.496 0.084 ;
    END
  END r_d[449]
  PIN r_d[44]
    DIRECTION OUTPUT ;
    USE SIGNAL ;
    PORT
      LAYER M5 ;
        RECT  65.712 0 65.736 0.084 ;
    END
  END r_d[44]
  PIN r_d[450]
    DIRECTION OUTPUT ;
    USE SIGNAL ;
    PORT
      LAYER M5 ;
        RECT  35.568 0 35.592 0.084 ;
    END
  END r_d[450]
  PIN r_d[451]
    DIRECTION OUTPUT ;
    USE SIGNAL ;
    PORT
      LAYER M5 ;
        RECT  35.664 0 35.688 0.084 ;
    END
  END r_d[451]
  PIN r_d[452]
    DIRECTION OUTPUT ;
    USE SIGNAL ;
    PORT
      LAYER M5 ;
        RECT  35.76 0 35.784 0.084 ;
    END
  END r_d[452]
  PIN r_d[453]
    DIRECTION OUTPUT ;
    USE SIGNAL ;
    PORT
      LAYER M5 ;
        RECT  35.856 0 35.88 0.084 ;
    END
  END r_d[453]
  PIN r_d[454]
    DIRECTION OUTPUT ;
    USE SIGNAL ;
    PORT
      LAYER M5 ;
        RECT  35.952 0 35.976 0.084 ;
    END
  END r_d[454]
  PIN r_d[455]
    DIRECTION OUTPUT ;
    USE SIGNAL ;
    PORT
      LAYER M5 ;
        RECT  36.048 0 36.072 0.084 ;
    END
  END r_d[455]
  PIN r_d[456]
    DIRECTION OUTPUT ;
    USE SIGNAL ;
    PORT
      LAYER M5 ;
        RECT  36.144 0 36.168 0.084 ;
    END
  END r_d[456]
  PIN r_d[457]
    DIRECTION OUTPUT ;
    USE SIGNAL ;
    PORT
      LAYER M5 ;
        RECT  36.24 0 36.264 0.084 ;
    END
  END r_d[457]
  PIN r_d[458]
    DIRECTION OUTPUT ;
    USE SIGNAL ;
    PORT
      LAYER M5 ;
        RECT  36.336 0 36.36 0.084 ;
    END
  END r_d[458]
  PIN r_d[459]
    DIRECTION OUTPUT ;
    USE SIGNAL ;
    PORT
      LAYER M5 ;
        RECT  36.432 0 36.456 0.084 ;
    END
  END r_d[459]
  PIN r_d[45]
    DIRECTION OUTPUT ;
    USE SIGNAL ;
    PORT
      LAYER M5 ;
        RECT  65.808 0 65.832 0.084 ;
    END
  END r_d[45]
  PIN r_d[460]
    DIRECTION OUTPUT ;
    USE SIGNAL ;
    PORT
      LAYER M5 ;
        RECT  36.528 0 36.552 0.084 ;
    END
  END r_d[460]
  PIN r_d[461]
    DIRECTION OUTPUT ;
    USE SIGNAL ;
    PORT
      LAYER M5 ;
        RECT  36.624 0 36.648 0.084 ;
    END
  END r_d[461]
  PIN r_d[462]
    DIRECTION OUTPUT ;
    USE SIGNAL ;
    PORT
      LAYER M5 ;
        RECT  36.72 0 36.744 0.084 ;
    END
  END r_d[462]
  PIN r_d[463]
    DIRECTION OUTPUT ;
    USE SIGNAL ;
    PORT
      LAYER M5 ;
        RECT  36.816 0 36.84 0.084 ;
    END
  END r_d[463]
  PIN r_d[464]
    DIRECTION OUTPUT ;
    USE SIGNAL ;
    PORT
      LAYER M5 ;
        RECT  36.912 0 36.936 0.084 ;
    END
  END r_d[464]
  PIN r_d[465]
    DIRECTION OUTPUT ;
    USE SIGNAL ;
    PORT
      LAYER M5 ;
        RECT  37.008 0 37.032 0.084 ;
    END
  END r_d[465]
  PIN r_d[466]
    DIRECTION OUTPUT ;
    USE SIGNAL ;
    PORT
      LAYER M5 ;
        RECT  37.104 0 37.128 0.084 ;
    END
  END r_d[466]
  PIN r_d[467]
    DIRECTION OUTPUT ;
    USE SIGNAL ;
    PORT
      LAYER M5 ;
        RECT  37.2 0 37.224 0.084 ;
    END
  END r_d[467]
  PIN r_d[468]
    DIRECTION OUTPUT ;
    USE SIGNAL ;
    PORT
      LAYER M5 ;
        RECT  37.296 0 37.32 0.084 ;
    END
  END r_d[468]
  PIN r_d[469]
    DIRECTION OUTPUT ;
    USE SIGNAL ;
    PORT
      LAYER M5 ;
        RECT  37.392 0 37.416 0.084 ;
    END
  END r_d[469]
  PIN r_d[46]
    DIRECTION OUTPUT ;
    USE SIGNAL ;
    PORT
      LAYER M5 ;
        RECT  65.904 0 65.928 0.084 ;
    END
  END r_d[46]
  PIN r_d[470]
    DIRECTION OUTPUT ;
    USE SIGNAL ;
    PORT
      LAYER M5 ;
        RECT  37.488 0 37.512 0.084 ;
    END
  END r_d[470]
  PIN r_d[471]
    DIRECTION OUTPUT ;
    USE SIGNAL ;
    PORT
      LAYER M5 ;
        RECT  37.584 0 37.608 0.084 ;
    END
  END r_d[471]
  PIN r_d[472]
    DIRECTION OUTPUT ;
    USE SIGNAL ;
    PORT
      LAYER M5 ;
        RECT  37.68 0 37.704 0.084 ;
    END
  END r_d[472]
  PIN r_d[473]
    DIRECTION OUTPUT ;
    USE SIGNAL ;
    PORT
      LAYER M5 ;
        RECT  37.776 0 37.8 0.084 ;
    END
  END r_d[473]
  PIN r_d[474]
    DIRECTION OUTPUT ;
    USE SIGNAL ;
    PORT
      LAYER M5 ;
        RECT  37.872 0 37.896 0.084 ;
    END
  END r_d[474]
  PIN r_d[475]
    DIRECTION OUTPUT ;
    USE SIGNAL ;
    PORT
      LAYER M5 ;
        RECT  37.968 0 37.992 0.084 ;
    END
  END r_d[475]
  PIN r_d[476]
    DIRECTION OUTPUT ;
    USE SIGNAL ;
    PORT
      LAYER M5 ;
        RECT  38.064 0 38.088 0.084 ;
    END
  END r_d[476]
  PIN r_d[477]
    DIRECTION OUTPUT ;
    USE SIGNAL ;
    PORT
      LAYER M5 ;
        RECT  38.16 0 38.184 0.084 ;
    END
  END r_d[477]
  PIN r_d[478]
    DIRECTION OUTPUT ;
    USE SIGNAL ;
    PORT
      LAYER M5 ;
        RECT  38.256 0 38.28 0.084 ;
    END
  END r_d[478]
  PIN r_d[479]
    DIRECTION OUTPUT ;
    USE SIGNAL ;
    PORT
      LAYER M5 ;
        RECT  32.208 0 32.232 0.084 ;
    END
  END r_d[479]
  PIN r_d[47]
    DIRECTION OUTPUT ;
    USE SIGNAL ;
    PORT
      LAYER M5 ;
        RECT  66 0 66.024 0.084 ;
    END
  END r_d[47]
  PIN r_d[480]
    DIRECTION OUTPUT ;
    USE SIGNAL ;
    PORT
      LAYER M5 ;
        RECT  32.304 0 32.328 0.084 ;
    END
  END r_d[480]
  PIN r_d[481]
    DIRECTION OUTPUT ;
    USE SIGNAL ;
    PORT
      LAYER M5 ;
        RECT  32.4 0 32.424 0.084 ;
    END
  END r_d[481]
  PIN r_d[482]
    DIRECTION OUTPUT ;
    USE SIGNAL ;
    PORT
      LAYER M5 ;
        RECT  32.496 0 32.52 0.084 ;
    END
  END r_d[482]
  PIN r_d[483]
    DIRECTION OUTPUT ;
    USE SIGNAL ;
    PORT
      LAYER M5 ;
        RECT  32.592 0 32.616 0.084 ;
    END
  END r_d[483]
  PIN r_d[484]
    DIRECTION OUTPUT ;
    USE SIGNAL ;
    PORT
      LAYER M5 ;
        RECT  32.688 0 32.712 0.084 ;
    END
  END r_d[484]
  PIN r_d[485]
    DIRECTION OUTPUT ;
    USE SIGNAL ;
    PORT
      LAYER M5 ;
        RECT  32.784 0 32.808 0.084 ;
    END
  END r_d[485]
  PIN r_d[486]
    DIRECTION OUTPUT ;
    USE SIGNAL ;
    PORT
      LAYER M5 ;
        RECT  32.88 0 32.904 0.084 ;
    END
  END r_d[486]
  PIN r_d[487]
    DIRECTION OUTPUT ;
    USE SIGNAL ;
    PORT
      LAYER M5 ;
        RECT  32.976 0 33 0.084 ;
    END
  END r_d[487]
  PIN r_d[488]
    DIRECTION OUTPUT ;
    USE SIGNAL ;
    PORT
      LAYER M5 ;
        RECT  33.072 0 33.096 0.084 ;
    END
  END r_d[488]
  PIN r_d[489]
    DIRECTION OUTPUT ;
    USE SIGNAL ;
    PORT
      LAYER M5 ;
        RECT  33.168 0 33.192 0.084 ;
    END
  END r_d[489]
  PIN r_d[48]
    DIRECTION OUTPUT ;
    USE SIGNAL ;
    PORT
      LAYER M5 ;
        RECT  66.096 0 66.12 0.084 ;
    END
  END r_d[48]
  PIN r_d[490]
    DIRECTION OUTPUT ;
    USE SIGNAL ;
    PORT
      LAYER M5 ;
        RECT  33.264 0 33.288 0.084 ;
    END
  END r_d[490]
  PIN r_d[491]
    DIRECTION OUTPUT ;
    USE SIGNAL ;
    PORT
      LAYER M5 ;
        RECT  33.36 0 33.384 0.084 ;
    END
  END r_d[491]
  PIN r_d[492]
    DIRECTION OUTPUT ;
    USE SIGNAL ;
    PORT
      LAYER M5 ;
        RECT  33.456 0 33.48 0.084 ;
    END
  END r_d[492]
  PIN r_d[493]
    DIRECTION OUTPUT ;
    USE SIGNAL ;
    PORT
      LAYER M5 ;
        RECT  33.552 0 33.576 0.084 ;
    END
  END r_d[493]
  PIN r_d[494]
    DIRECTION OUTPUT ;
    USE SIGNAL ;
    PORT
      LAYER M5 ;
        RECT  33.648 0 33.672 0.084 ;
    END
  END r_d[494]
  PIN r_d[495]
    DIRECTION OUTPUT ;
    USE SIGNAL ;
    PORT
      LAYER M5 ;
        RECT  33.744 0 33.768 0.084 ;
    END
  END r_d[495]
  PIN r_d[496]
    DIRECTION OUTPUT ;
    USE SIGNAL ;
    PORT
      LAYER M5 ;
        RECT  33.84 0 33.864 0.084 ;
    END
  END r_d[496]
  PIN r_d[497]
    DIRECTION OUTPUT ;
    USE SIGNAL ;
    PORT
      LAYER M5 ;
        RECT  33.936 0 33.96 0.084 ;
    END
  END r_d[497]
  PIN r_d[498]
    DIRECTION OUTPUT ;
    USE SIGNAL ;
    PORT
      LAYER M5 ;
        RECT  34.032 0 34.056 0.084 ;
    END
  END r_d[498]
  PIN r_d[499]
    DIRECTION OUTPUT ;
    USE SIGNAL ;
    PORT
      LAYER M5 ;
        RECT  34.128 0 34.152 0.084 ;
    END
  END r_d[499]
  PIN r_d[49]
    DIRECTION OUTPUT ;
    USE SIGNAL ;
    PORT
      LAYER M5 ;
        RECT  66.192 0 66.216 0.084 ;
    END
  END r_d[49]
  PIN r_d[4]
    DIRECTION OUTPUT ;
    USE SIGNAL ;
    PORT
      LAYER M5 ;
        RECT  48.816 0 48.84 0.084 ;
    END
  END r_d[4]
  PIN r_d[500]
    DIRECTION OUTPUT ;
    USE SIGNAL ;
    PORT
      LAYER M5 ;
        RECT  34.224 0 34.248 0.084 ;
    END
  END r_d[500]
  PIN r_d[501]
    DIRECTION OUTPUT ;
    USE SIGNAL ;
    PORT
      LAYER M5 ;
        RECT  34.32 0 34.344 0.084 ;
    END
  END r_d[501]
  PIN r_d[502]
    DIRECTION OUTPUT ;
    USE SIGNAL ;
    PORT
      LAYER M5 ;
        RECT  34.416 0 34.44 0.084 ;
    END
  END r_d[502]
  PIN r_d[503]
    DIRECTION OUTPUT ;
    USE SIGNAL ;
    PORT
      LAYER M5 ;
        RECT  34.512 0 34.536 0.084 ;
    END
  END r_d[503]
  PIN r_d[504]
    DIRECTION OUTPUT ;
    USE SIGNAL ;
    PORT
      LAYER M5 ;
        RECT  34.608 0 34.632 0.084 ;
    END
  END r_d[504]
  PIN r_d[505]
    DIRECTION OUTPUT ;
    USE SIGNAL ;
    PORT
      LAYER M5 ;
        RECT  34.704 0 34.728 0.084 ;
    END
  END r_d[505]
  PIN r_d[506]
    DIRECTION OUTPUT ;
    USE SIGNAL ;
    PORT
      LAYER M5 ;
        RECT  34.8 0 34.824 0.084 ;
    END
  END r_d[506]
  PIN r_d[507]
    DIRECTION OUTPUT ;
    USE SIGNAL ;
    PORT
      LAYER M5 ;
        RECT  34.896 0 34.92 0.084 ;
    END
  END r_d[507]
  PIN r_d[508]
    DIRECTION OUTPUT ;
    USE SIGNAL ;
    PORT
      LAYER M5 ;
        RECT  34.992 0 35.016 0.084 ;
    END
  END r_d[508]
  PIN r_d[509]
    DIRECTION OUTPUT ;
    USE SIGNAL ;
    PORT
      LAYER M5 ;
        RECT  35.088 0 35.112 0.084 ;
    END
  END r_d[509]
  PIN r_d[50]
    DIRECTION OUTPUT ;
    USE SIGNAL ;
    PORT
      LAYER M5 ;
        RECT  66.288 0 66.312 0.084 ;
    END
  END r_d[50]
  PIN r_d[510]
    DIRECTION OUTPUT ;
    USE SIGNAL ;
    PORT
      LAYER M5 ;
        RECT  35.184 0 35.208 0.084 ;
    END
  END r_d[510]
  PIN r_d[511]
    DIRECTION OUTPUT ;
    USE SIGNAL ;
    PORT
      LAYER M5 ;
        RECT  18 0 18.024 0.084 ;
    END
  END r_d[511]
  PIN r_d[512]
    DIRECTION OUTPUT ;
    USE SIGNAL ;
    PORT
      LAYER M5 ;
        RECT  18.096 0 18.12 0.084 ;
    END
  END r_d[512]
  PIN r_d[513]
    DIRECTION OUTPUT ;
    USE SIGNAL ;
    PORT
      LAYER M5 ;
        RECT  18.192 0 18.216 0.084 ;
    END
  END r_d[513]
  PIN r_d[514]
    DIRECTION OUTPUT ;
    USE SIGNAL ;
    PORT
      LAYER M5 ;
        RECT  18.288 0 18.312 0.084 ;
    END
  END r_d[514]
  PIN r_d[515]
    DIRECTION OUTPUT ;
    USE SIGNAL ;
    PORT
      LAYER M5 ;
        RECT  18.384 0 18.408 0.084 ;
    END
  END r_d[515]
  PIN r_d[516]
    DIRECTION OUTPUT ;
    USE SIGNAL ;
    PORT
      LAYER M5 ;
        RECT  18.48 0 18.504 0.084 ;
    END
  END r_d[516]
  PIN r_d[517]
    DIRECTION OUTPUT ;
    USE SIGNAL ;
    PORT
      LAYER M5 ;
        RECT  18.576 0 18.6 0.084 ;
    END
  END r_d[517]
  PIN r_d[518]
    DIRECTION OUTPUT ;
    USE SIGNAL ;
    PORT
      LAYER M5 ;
        RECT  18.672 0 18.696 0.084 ;
    END
  END r_d[518]
  PIN r_d[519]
    DIRECTION OUTPUT ;
    USE SIGNAL ;
    PORT
      LAYER M5 ;
        RECT  18.768 0 18.792 0.084 ;
    END
  END r_d[519]
  PIN r_d[51]
    DIRECTION OUTPUT ;
    USE SIGNAL ;
    PORT
      LAYER M5 ;
        RECT  66.384 0 66.408 0.084 ;
    END
  END r_d[51]
  PIN r_d[520]
    DIRECTION OUTPUT ;
    USE SIGNAL ;
    PORT
      LAYER M5 ;
        RECT  18.864 0 18.888 0.084 ;
    END
  END r_d[520]
  PIN r_d[521]
    DIRECTION OUTPUT ;
    USE SIGNAL ;
    PORT
      LAYER M5 ;
        RECT  18.96 0 18.984 0.084 ;
    END
  END r_d[521]
  PIN r_d[522]
    DIRECTION OUTPUT ;
    USE SIGNAL ;
    PORT
      LAYER M5 ;
        RECT  19.056 0 19.08 0.084 ;
    END
  END r_d[522]
  PIN r_d[523]
    DIRECTION OUTPUT ;
    USE SIGNAL ;
    PORT
      LAYER M5 ;
        RECT  19.152 0 19.176 0.084 ;
    END
  END r_d[523]
  PIN r_d[524]
    DIRECTION OUTPUT ;
    USE SIGNAL ;
    PORT
      LAYER M5 ;
        RECT  19.248 0 19.272 0.084 ;
    END
  END r_d[524]
  PIN r_d[525]
    DIRECTION OUTPUT ;
    USE SIGNAL ;
    PORT
      LAYER M5 ;
        RECT  19.344 0 19.368 0.084 ;
    END
  END r_d[525]
  PIN r_d[526]
    DIRECTION OUTPUT ;
    USE SIGNAL ;
    PORT
      LAYER M5 ;
        RECT  19.44 0 19.464 0.084 ;
    END
  END r_d[526]
  PIN r_d[527]
    DIRECTION OUTPUT ;
    USE SIGNAL ;
    PORT
      LAYER M5 ;
        RECT  19.536 0 19.56 0.084 ;
    END
  END r_d[527]
  PIN r_d[52]
    DIRECTION OUTPUT ;
    USE SIGNAL ;
    PORT
      LAYER M5 ;
        RECT  66.48 0 66.504 0.084 ;
    END
  END r_d[52]
  PIN r_d[53]
    DIRECTION OUTPUT ;
    USE SIGNAL ;
    PORT
      LAYER M5 ;
        RECT  66.576 0 66.6 0.084 ;
    END
  END r_d[53]
  PIN r_d[54]
    DIRECTION OUTPUT ;
    USE SIGNAL ;
    PORT
      LAYER M5 ;
        RECT  66.672 0 66.696 0.084 ;
    END
  END r_d[54]
  PIN r_d[55]
    DIRECTION OUTPUT ;
    USE SIGNAL ;
    PORT
      LAYER M5 ;
        RECT  66.768 0 66.792 0.084 ;
    END
  END r_d[55]
  PIN r_d[56]
    DIRECTION OUTPUT ;
    USE SIGNAL ;
    PORT
      LAYER M5 ;
        RECT  66.864 0 66.888 0.084 ;
    END
  END r_d[56]
  PIN r_d[57]
    DIRECTION OUTPUT ;
    USE SIGNAL ;
    PORT
      LAYER M5 ;
        RECT  66.96 0 66.984 0.084 ;
    END
  END r_d[57]
  PIN r_d[58]
    DIRECTION OUTPUT ;
    USE SIGNAL ;
    PORT
      LAYER M5 ;
        RECT  67.056 0 67.08 0.084 ;
    END
  END r_d[58]
  PIN r_d[59]
    DIRECTION OUTPUT ;
    USE SIGNAL ;
    PORT
      LAYER M5 ;
        RECT  67.152 0 67.176 0.084 ;
    END
  END r_d[59]
  PIN r_d[5]
    DIRECTION OUTPUT ;
    USE SIGNAL ;
    PORT
      LAYER M5 ;
        RECT  48.912 0 48.936 0.084 ;
    END
  END r_d[5]
  PIN r_d[60]
    DIRECTION OUTPUT ;
    USE SIGNAL ;
    PORT
      LAYER M5 ;
        RECT  67.248 0 67.272 0.084 ;
    END
  END r_d[60]
  PIN r_d[61]
    DIRECTION OUTPUT ;
    USE SIGNAL ;
    PORT
      LAYER M5 ;
        RECT  67.344 0 67.368 0.084 ;
    END
  END r_d[61]
  PIN r_d[62]
    DIRECTION OUTPUT ;
    USE SIGNAL ;
    PORT
      LAYER M5 ;
        RECT  67.44 0 67.464 0.084 ;
    END
  END r_d[62]
  PIN r_d[63]
    DIRECTION OUTPUT ;
    USE SIGNAL ;
    PORT
      LAYER M5 ;
        RECT  54.48 0 54.504 0.084 ;
    END
  END r_d[63]
  PIN r_d[64]
    DIRECTION OUTPUT ;
    USE SIGNAL ;
    PORT
      LAYER M5 ;
        RECT  54.576 0 54.6 0.084 ;
    END
  END r_d[64]
  PIN r_d[65]
    DIRECTION OUTPUT ;
    USE SIGNAL ;
    PORT
      LAYER M5 ;
        RECT  54.672 0 54.696 0.084 ;
    END
  END r_d[65]
  PIN r_d[66]
    DIRECTION OUTPUT ;
    USE SIGNAL ;
    PORT
      LAYER M5 ;
        RECT  54.768 0 54.792 0.084 ;
    END
  END r_d[66]
  PIN r_d[67]
    DIRECTION OUTPUT ;
    USE SIGNAL ;
    PORT
      LAYER M5 ;
        RECT  54.864 0 54.888 0.084 ;
    END
  END r_d[67]
  PIN r_d[68]
    DIRECTION OUTPUT ;
    USE SIGNAL ;
    PORT
      LAYER M5 ;
        RECT  54.96 0 54.984 0.084 ;
    END
  END r_d[68]
  PIN r_d[69]
    DIRECTION OUTPUT ;
    USE SIGNAL ;
    PORT
      LAYER M5 ;
        RECT  55.056 0 55.08 0.084 ;
    END
  END r_d[69]
  PIN r_d[6]
    DIRECTION OUTPUT ;
    USE SIGNAL ;
    PORT
      LAYER M5 ;
        RECT  49.008 0 49.032 0.084 ;
    END
  END r_d[6]
  PIN r_d[70]
    DIRECTION OUTPUT ;
    USE SIGNAL ;
    PORT
      LAYER M5 ;
        RECT  55.152 0 55.176 0.084 ;
    END
  END r_d[70]
  PIN r_d[71]
    DIRECTION OUTPUT ;
    USE SIGNAL ;
    PORT
      LAYER M5 ;
        RECT  55.248 0 55.272 0.084 ;
    END
  END r_d[71]
  PIN r_d[72]
    DIRECTION OUTPUT ;
    USE SIGNAL ;
    PORT
      LAYER M5 ;
        RECT  55.344 0 55.368 0.084 ;
    END
  END r_d[72]
  PIN r_d[73]
    DIRECTION OUTPUT ;
    USE SIGNAL ;
    PORT
      LAYER M5 ;
        RECT  55.44 0 55.464 0.084 ;
    END
  END r_d[73]
  PIN r_d[74]
    DIRECTION OUTPUT ;
    USE SIGNAL ;
    PORT
      LAYER M5 ;
        RECT  55.536 0 55.56 0.084 ;
    END
  END r_d[74]
  PIN r_d[75]
    DIRECTION OUTPUT ;
    USE SIGNAL ;
    PORT
      LAYER M5 ;
        RECT  55.632 0 55.656 0.084 ;
    END
  END r_d[75]
  PIN r_d[76]
    DIRECTION OUTPUT ;
    USE SIGNAL ;
    PORT
      LAYER M5 ;
        RECT  55.728 0 55.752 0.084 ;
    END
  END r_d[76]
  PIN r_d[77]
    DIRECTION OUTPUT ;
    USE SIGNAL ;
    PORT
      LAYER M5 ;
        RECT  55.824 0 55.848 0.084 ;
    END
  END r_d[77]
  PIN r_d[78]
    DIRECTION OUTPUT ;
    USE SIGNAL ;
    PORT
      LAYER M5 ;
        RECT  55.92 0 55.944 0.084 ;
    END
  END r_d[78]
  PIN r_d[79]
    DIRECTION OUTPUT ;
    USE SIGNAL ;
    PORT
      LAYER M5 ;
        RECT  56.016 0 56.04 0.084 ;
    END
  END r_d[79]
  PIN r_d[7]
    DIRECTION OUTPUT ;
    USE SIGNAL ;
    PORT
      LAYER M5 ;
        RECT  49.104 0 49.128 0.084 ;
    END
  END r_d[7]
  PIN r_d[80]
    DIRECTION OUTPUT ;
    USE SIGNAL ;
    PORT
      LAYER M5 ;
        RECT  56.112 0 56.136 0.084 ;
    END
  END r_d[80]
  PIN r_d[81]
    DIRECTION OUTPUT ;
    USE SIGNAL ;
    PORT
      LAYER M5 ;
        RECT  56.208 0 56.232 0.084 ;
    END
  END r_d[81]
  PIN r_d[82]
    DIRECTION OUTPUT ;
    USE SIGNAL ;
    PORT
      LAYER M5 ;
        RECT  56.304 0 56.328 0.084 ;
    END
  END r_d[82]
  PIN r_d[83]
    DIRECTION OUTPUT ;
    USE SIGNAL ;
    PORT
      LAYER M5 ;
        RECT  56.4 0 56.424 0.084 ;
    END
  END r_d[83]
  PIN r_d[84]
    DIRECTION OUTPUT ;
    USE SIGNAL ;
    PORT
      LAYER M5 ;
        RECT  56.496 0 56.52 0.084 ;
    END
  END r_d[84]
  PIN r_d[85]
    DIRECTION OUTPUT ;
    USE SIGNAL ;
    PORT
      LAYER M5 ;
        RECT  56.592 0 56.616 0.084 ;
    END
  END r_d[85]
  PIN r_d[86]
    DIRECTION OUTPUT ;
    USE SIGNAL ;
    PORT
      LAYER M5 ;
        RECT  56.688 0 56.712 0.084 ;
    END
  END r_d[86]
  PIN r_d[87]
    DIRECTION OUTPUT ;
    USE SIGNAL ;
    PORT
      LAYER M5 ;
        RECT  56.784 0 56.808 0.084 ;
    END
  END r_d[87]
  PIN r_d[88]
    DIRECTION OUTPUT ;
    USE SIGNAL ;
    PORT
      LAYER M5 ;
        RECT  56.88 0 56.904 0.084 ;
    END
  END r_d[88]
  PIN r_d[89]
    DIRECTION OUTPUT ;
    USE SIGNAL ;
    PORT
      LAYER M5 ;
        RECT  56.976 0 57 0.084 ;
    END
  END r_d[89]
  PIN r_d[8]
    DIRECTION OUTPUT ;
    USE SIGNAL ;
    PORT
      LAYER M5 ;
        RECT  49.2 0 49.224 0.084 ;
    END
  END r_d[8]
  PIN r_d[90]
    DIRECTION OUTPUT ;
    USE SIGNAL ;
    PORT
      LAYER M5 ;
        RECT  57.072 0 57.096 0.084 ;
    END
  END r_d[90]
  PIN r_d[91]
    DIRECTION OUTPUT ;
    USE SIGNAL ;
    PORT
      LAYER M5 ;
        RECT  57.168 0 57.192 0.084 ;
    END
  END r_d[91]
  PIN r_d[92]
    DIRECTION OUTPUT ;
    USE SIGNAL ;
    PORT
      LAYER M5 ;
        RECT  57.264 0 57.288 0.084 ;
    END
  END r_d[92]
  PIN r_d[93]
    DIRECTION OUTPUT ;
    USE SIGNAL ;
    PORT
      LAYER M5 ;
        RECT  57.36 0 57.384 0.084 ;
    END
  END r_d[93]
  PIN r_d[94]
    DIRECTION OUTPUT ;
    USE SIGNAL ;
    PORT
      LAYER M5 ;
        RECT  57.456 0 57.48 0.084 ;
    END
  END r_d[94]
  PIN r_d[95]
    DIRECTION OUTPUT ;
    USE SIGNAL ;
    PORT
      LAYER M5 ;
        RECT  45.264 0 45.288 0.084 ;
    END
  END r_d[95]
  PIN r_d[96]
    DIRECTION OUTPUT ;
    USE SIGNAL ;
    PORT
      LAYER M5 ;
        RECT  45.36 0 45.384 0.084 ;
    END
  END r_d[96]
  PIN r_d[97]
    DIRECTION OUTPUT ;
    USE SIGNAL ;
    PORT
      LAYER M5 ;
        RECT  45.456 0 45.48 0.084 ;
    END
  END r_d[97]
  PIN r_d[98]
    DIRECTION OUTPUT ;
    USE SIGNAL ;
    PORT
      LAYER M5 ;
        RECT  45.552 0 45.576 0.084 ;
    END
  END r_d[98]
  PIN r_d[99]
    DIRECTION OUTPUT ;
    USE SIGNAL ;
    PORT
      LAYER M5 ;
        RECT  45.648 0 45.672 0.084 ;
    END
  END r_d[99]
  PIN r_d[9]
    DIRECTION OUTPUT ;
    USE SIGNAL ;
    PORT
      LAYER M5 ;
        RECT  49.296 0 49.32 0.084 ;
    END
  END r_d[9]
  PIN r_v
    DIRECTION OUTPUT ;
    USE SIGNAL ;
    PORT
      LAYER M5 ;
        RECT  19.632 0 19.656 0.084 ;
    END
  END r_v
  PIN rst_n
    DIRECTION INPUT ;
    USE SIGNAL ;
    PORT
      LAYER M4 ;
        RECT  0 15.408 0.084 15.432 ;
    END
  END rst_n
  PIN VDD
    DIRECTION INOUT ;
    USE POWER ;
    PORT
      LAYER M5 ;
        RECT  83.592 2.151 83.712 25.929 ;
        RECT  78.192 2.151 78.312 25.929 ;
        RECT  72.792 2.151 72.912 25.929 ;
        RECT  67.392 2.151 67.512 25.929 ;
        RECT  61.992 2.151 62.112 25.929 ;
        RECT  56.592 2.151 56.712 25.929 ;
        RECT  51.192 2.151 51.312 25.929 ;
        RECT  45.792 2.151 45.912 25.929 ;
        RECT  40.392 2.151 40.512 25.929 ;
        RECT  34.992 2.151 35.112 25.929 ;
        RECT  29.592 2.151 29.712 25.929 ;
        RECT  24.192 2.151 24.312 25.929 ;
        RECT  18.792 2.151 18.912 25.929 ;
        RECT  13.392 2.151 13.512 25.929 ;
        RECT  7.992 2.151 8.112 25.929 ;
        RECT  2.592 2.151 2.712 25.929 ;
    END
  END VDD
  PIN VSS
    DIRECTION INOUT ;
    USE GROUND ;
    PORT
      LAYER M5 ;
        RECT  83.4 2.137 83.52 25.943 ;
        RECT  78 2.137 78.12 25.943 ;
        RECT  72.6 2.137 72.72 25.943 ;
        RECT  67.2 2.137 67.32 25.943 ;
        RECT  61.8 2.137 61.92 25.943 ;
        RECT  56.4 2.137 56.52 25.943 ;
        RECT  51 2.137 51.12 25.943 ;
        RECT  45.6 2.137 45.72 25.943 ;
        RECT  40.2 2.137 40.32 25.943 ;
        RECT  34.8 2.137 34.92 25.943 ;
        RECT  29.4 2.137 29.52 25.943 ;
        RECT  24 2.137 24.12 25.943 ;
        RECT  18.6 2.137 18.72 25.943 ;
        RECT  13.2 2.137 13.32 25.943 ;
        RECT  7.8 2.137 7.92 25.943 ;
        RECT  2.4 2.137 2.52 25.943 ;
    END
  END VSS
  # OT_OBS_CLOSED layer=M5 d_um=1.536 added=162
  OBS
    LAYER RVTN ;
     RECT  2.16 2.16 84.24 2.295 ;
     RECT  2.16 2.565 84.24 2.835 ;
     RECT  2.16 3.105 84.24 3.375 ;
     RECT  2.16 3.645 84.24 3.915 ;
     RECT  2.16 4.185 84.24 4.455 ;
     RECT  2.16 4.725 84.24 4.995 ;
     RECT  2.16 5.265 84.24 5.535 ;
     RECT  2.16 5.805 84.24 6.075 ;
     RECT  2.16 6.345 84.24 6.615 ;
     RECT  2.16 6.885 84.24 7.155 ;
     RECT  2.16 7.425 84.24 7.695 ;
     RECT  2.16 7.965 84.24 8.235 ;
     RECT  2.16 8.505 84.24 8.775 ;
     RECT  2.16 9.045 84.24 9.315 ;
     RECT  2.16 9.585 84.24 9.855 ;
     RECT  2.16 10.125 84.24 10.395 ;
     RECT  2.16 10.665 84.24 10.935 ;
     RECT  2.16 11.205 84.24 11.475 ;
     RECT  2.16 11.745 84.24 12.015 ;
     RECT  2.16 12.285 84.24 12.555 ;
     RECT  2.16 12.825 84.24 13.095 ;
     RECT  2.16 13.365 84.24 13.635 ;
     RECT  2.16 13.905 84.24 14.175 ;
     RECT  2.16 14.445 84.24 14.715 ;
     RECT  2.16 14.985 84.24 15.255 ;
     RECT  2.16 15.525 84.24 15.795 ;
     RECT  2.16 16.065 84.24 16.335 ;
     RECT  2.16 16.605 84.24 16.875 ;
     RECT  2.16 17.145 84.24 17.415 ;
     RECT  2.16 17.685 84.24 17.955 ;
     RECT  2.16 18.225 84.24 18.495 ;
     RECT  2.16 18.765 84.24 19.035 ;
     RECT  2.16 19.305 84.24 19.575 ;
     RECT  2.16 19.845 84.24 20.115 ;
     RECT  2.16 20.385 84.24 20.655 ;
     RECT  2.16 20.925 84.24 21.195 ;
     RECT  2.16 21.465 84.24 21.735 ;
     RECT  2.16 22.005 84.24 22.275 ;
     RECT  2.16 22.545 84.24 22.815 ;
     RECT  2.16 23.085 84.24 23.355 ;
     RECT  2.16 23.625 84.24 23.895 ;
     RECT  2.16 24.165 84.24 24.435 ;
     RECT  2.16 24.705 84.24 24.975 ;
     RECT  2.16 25.245 84.24 25.515 ;
     RECT  2.16 25.785 84.24 25.92 ;
    LAYER RVTP ;
     RECT  2.16 2.295 84.24 2.565 ;
     RECT  2.16 2.835 84.24 3.105 ;
     RECT  2.16 3.375 84.24 3.645 ;
     RECT  2.16 3.915 84.24 4.185 ;
     RECT  2.16 4.455 84.24 4.725 ;
     RECT  2.16 4.995 84.24 5.265 ;
     RECT  2.16 5.535 84.24 5.805 ;
     RECT  2.16 6.075 84.24 6.345 ;
     RECT  2.16 6.615 84.24 6.885 ;
     RECT  2.16 7.155 84.24 7.425 ;
     RECT  2.16 7.695 84.24 7.965 ;
     RECT  2.16 8.235 84.24 8.505 ;
     RECT  2.16 8.775 84.24 9.045 ;
     RECT  2.16 9.315 84.24 9.585 ;
     RECT  2.16 9.855 84.24 10.125 ;
     RECT  2.16 10.395 84.24 10.665 ;
     RECT  2.16 10.935 84.24 11.205 ;
     RECT  2.16 11.475 84.24 11.745 ;
     RECT  2.16 12.015 84.24 12.285 ;
     RECT  2.16 12.555 84.24 12.825 ;
     RECT  2.16 13.095 84.24 13.365 ;
     RECT  2.16 13.635 84.24 13.905 ;
     RECT  2.16 14.175 84.24 14.445 ;
     RECT  2.16 14.715 84.24 14.985 ;
     RECT  2.16 15.255 84.24 15.525 ;
     RECT  2.16 15.795 84.24 16.065 ;
     RECT  2.16 16.335 84.24 16.605 ;
     RECT  2.16 16.875 84.24 17.145 ;
     RECT  2.16 17.415 84.24 17.685 ;
     RECT  2.16 17.955 84.24 18.225 ;
     RECT  2.16 18.495 84.24 18.765 ;
     RECT  2.16 19.035 84.24 19.305 ;
     RECT  2.16 19.575 84.24 19.845 ;
     RECT  2.16 20.115 84.24 20.385 ;
     RECT  2.16 20.655 84.24 20.925 ;
     RECT  2.16 21.195 84.24 21.465 ;
     RECT  2.16 21.735 84.24 22.005 ;
     RECT  2.16 22.275 84.24 22.545 ;
     RECT  2.16 22.815 84.24 23.085 ;
     RECT  2.16 23.355 84.24 23.625 ;
     RECT  2.16 23.895 84.24 24.165 ;
     RECT  2.16 24.435 84.24 24.705 ;
     RECT  2.16 24.975 84.24 25.245 ;
     RECT  2.16 25.515 84.24 25.785 ;
    LAYER M1 ;
     RECT  2.16 2.151 84.24 25.929 ;
    LAYER M2 ;
     RECT  2.16 2.151 10.795 25.929 ;
     RECT  10.795 1.53 11.011 25.929 ;
     RECT  11.083 0.108 11.407 0.126 ;
     RECT  11.011 0.882 11.407 25.929 ;
     RECT  11.407 0.108 14.855 25.929 ;
     RECT  14.855 0.216 16.051 25.929 ;
     RECT  16.051 0.036 19.759 25.929 ;
     RECT  19.759 0.036 20.759 25.974 ;
     RECT  20.759 0.036 22.127 25.929 ;
     RECT  22.127 0.036 22.415 0.864 ;
     RECT  22.127 1.611 22.919 25.929 ;
     RECT  22.919 1.8 23.891 25.929 ;
     RECT  23.891 1.836 23.927 25.929 ;
     RECT  22.415 0.036 24.935 0.162 ;
     RECT  24.935 0.036 25.151 0.09 ;
     RECT  25.151 0.036 25.295 0.054 ;
     RECT  23.927 1.881 25.655 25.929 ;
     RECT  25.655 2.034 26.087 25.929 ;
     RECT  26.563 1.152 27.167 1.17 ;
     RECT  26.087 2.151 27.355 25.929 ;
     RECT  28.831 1.152 29.003 1.17 ;
     RECT  27.355 2.106 30.191 25.929 ;
     RECT  31.063 1.152 31.199 1.17 ;
     RECT  36.571 1.152 36.707 1.17 ;
     RECT  30.191 2.151 39.919 25.929 ;
     RECT  39.919 2.106 40.379 25.929 ;
     RECT  42.583 1.152 42.683 1.17 ;
     RECT  40.379 2.151 45.031 25.929 ;
     RECT  45.031 2.106 45.275 25.929 ;
     RECT  45.391 1.152 45.491 1.17 ;
     RECT  45.275 2.151 47.263 25.929 ;
     RECT  47.263 2.151 49.279 25.974 ;
     RECT  49.279 2.106 50.135 25.974 ;
     RECT  50.071 26.766 50.171 26.784 ;
     RECT  50.135 2.151 50.647 25.974 ;
     RECT  50.647 2.151 51.187 26.01 ;
     RECT  51.187 2.151 51.475 26.046 ;
     RECT  51.475 2.151 51.583 26.118 ;
     RECT  51.583 2.106 52.339 26.118 ;
     RECT  52.339 2.034 53.303 26.118 ;
     RECT  53.303 2.151 55.571 26.118 ;
     RECT  55.571 2.151 60.295 25.929 ;
     RECT  60.295 2.151 60.655 25.974 ;
     RECT  60.655 2.106 60.971 25.974 ;
     RECT  60.971 2.106 61.295 25.929 ;
     RECT  61.295 2.151 62.671 25.929 ;
     RECT  63.823 0.846 64.363 0.864 ;
     RECT  64.363 0.846 64.399 0.936 ;
     RECT  62.671 2.106 64.399 25.929 ;
     RECT  64.939 0.036 66.415 0.054 ;
     RECT  64.399 0.846 66.415 25.929 ;
     RECT  66.415 0.036 74.219 25.929 ;
     RECT  74.219 0.072 74.579 25.929 ;
     RECT  74.579 0.072 75.011 0.234 ;
     RECT  75.011 0.072 75.299 0.198 ;
     RECT  74.579 0.99 76.091 25.929 ;
     RECT  75.299 0.18 77.027 0.198 ;
     RECT  76.091 1.422 77.351 25.929 ;
     RECT  77.351 1.53 77.819 25.929 ;
     RECT  77.819 2.151 84.24 25.929 ;
    LAYER M3 ;
     RECT  16.056 0.031 16.074 0.067 ;
     RECT  25.272 0.031 25.29 0.067 ;
     RECT  66.816 0.043 66.834 0.067 ;
     RECT  25.128 0.067 25.29 0.091 ;
     RECT  64.944 0.031 64.962 0.091 ;
     RECT  66.6 0.067 66.834 0.091 ;
     RECT  70.344 0.043 70.362 0.091 ;
     RECT  14.868 0.043 14.886 0.103 ;
     RECT  66.6 0.091 66.906 0.103 ;
     RECT  74.196 0.031 74.214 0.103 ;
     RECT  75.276 0.067 75.294 0.103 ;
     RECT  16.056 0.067 16.542 0.139 ;
     RECT  17.712 0.091 17.73 0.139 ;
     RECT  34.452 0.091 35.19 0.139 ;
     RECT  36.54 0.091 36.558 0.139 ;
     RECT  37.332 0.091 37.854 0.139 ;
     RECT  64.944 0.091 65.682 0.139 ;
     RECT  66.42 0.103 66.906 0.139 ;
     RECT  73.116 0.091 73.134 0.139 ;
     RECT  23.904 0.091 25.29 0.173 ;
     RECT  23.904 0.173 24.93 0.176 ;
     RECT  12.492 0.139 12.51 0.187 ;
     RECT  14.832 0.103 14.886 0.187 ;
     RECT  15.84 0.139 17.73 0.187 ;
     RECT  29.844 0.091 29.862 0.187 ;
     RECT  31.068 0.091 32.634 0.187 ;
     RECT  70.128 0.091 70.434 0.187 ;
     RECT  72.504 0.139 73.134 0.187 ;
     RECT  74.196 0.103 75.294 0.187 ;
     RECT  15.732 0.187 18.27 0.211 ;
     RECT  19.008 0.091 19.422 0.211 ;
     RECT  29.844 0.187 32.634 0.221 ;
     RECT  34.452 0.139 35.262 0.221 ;
     RECT  44.244 0.091 44.262 0.221 ;
     RECT  64.944 0.139 66.906 0.221 ;
     RECT  36.54 0.139 37.854 0.235 ;
     RECT  64.944 0.221 66.762 0.235 ;
     RECT  72.504 0.187 75.294 0.235 ;
     RECT  27.684 0.091 27.702 0.269 ;
     RECT  54.144 0.091 54.162 0.283 ;
     RECT  70.128 0.187 70.542 0.283 ;
     RECT  72.468 0.235 75.294 0.283 ;
     RECT  52.272 0.091 52.506 0.317 ;
     RECT  72.36 0.283 75.294 0.331 ;
     RECT  63.828 0.235 66.762 0.365 ;
     RECT  14.832 0.187 14.958 0.427 ;
     RECT  27.072 0.475 27.63 0.523 ;
     RECT  30.456 0.221 32.634 0.523 ;
     RECT  35.136 0.221 35.262 0.557 ;
     RECT  11.088 0.103 11.106 0.571 ;
     RECT  40.752 0.091 40.77 0.571 ;
     RECT  42.588 0.091 42.93 0.571 ;
     RECT  47.736 0.091 47.754 0.571 ;
     RECT  50.652 0.091 50.67 0.571 ;
     RECT  53.424 0.283 54.162 0.571 ;
     RECT  56.592 0.523 56.61 0.571 ;
     RECT  71.892 0.331 75.294 0.571 ;
     RECT  14.22 0.427 14.958 0.599 ;
     RECT  12.492 0.187 12.87 0.643 ;
     RECT  23.904 0.176 24.786 0.667 ;
     RECT  45.072 0.571 45.414 0.701 ;
     RECT  15.732 0.211 19.422 0.715 ;
     RECT  69.552 0.283 70.542 0.763 ;
     RECT  71.424 0.571 75.294 0.763 ;
     RECT  12.492 0.643 12.978 0.859 ;
     RECT  13.932 0.811 13.95 0.859 ;
     RECT  20.34 0.091 21.078 0.859 ;
     RECT  21.816 0.091 22.914 0.859 ;
     RECT  63.828 0.365 64.494 0.869 ;
     RECT  11.088 0.571 11.43 0.877 ;
     RECT  14.724 0.599 14.958 0.877 ;
     RECT  15.732 0.715 19.53 0.877 ;
     RECT  64.368 0.869 64.494 0.941 ;
     RECT  77.004 0.175 77.022 0.955 ;
     RECT  65.664 0.365 66.762 0.977 ;
     RECT  67.824 0.955 67.842 1.003 ;
     RECT  68.724 0.091 68.742 1.003 ;
     RECT  26.028 0.523 27.63 1.099 ;
     RECT  28.98 0.571 28.998 1.147 ;
     RECT  36.216 0.235 38.286 1.147 ;
     RECT  45.396 0.701 45.414 1.147 ;
     RECT  52.704 0.571 54.162 1.147 ;
     RECT  42.588 0.571 43.074 1.175 ;
     RECT  45.396 1.147 45.486 1.175 ;
     RECT  52.704 1.147 54.954 1.195 ;
     RECT  11.016 0.877 11.43 1.336 ;
     RECT  12.492 0.859 13.95 1.336 ;
     RECT  76.824 0.955 77.022 1.417 ;
     RECT  69.552 0.763 75.294 1.435 ;
     RECT  76.068 0.985 76.086 1.435 ;
     RECT  65.664 0.977 66.15 1.481 ;
     RECT  69.552 1.435 76.086 1.483 ;
     RECT  76.824 1.417 77.346 1.483 ;
     RECT  11.016 1.336 13.95 1.525 ;
     RECT  69.552 1.483 77.346 1.525 ;
     RECT  46.548 0.091 46.566 1.627 ;
     RECT  40.752 0.571 41.058 1.675 ;
     RECT  51.516 0.091 51.534 1.675 ;
     RECT  25.632 1.099 27.63 1.723 ;
     RECT  28.512 1.147 29.106 1.723 ;
     RECT  30.456 0.523 32.922 1.723 ;
     RECT  35.136 0.557 35.19 1.723 ;
     RECT  39.024 1.099 39.042 1.723 ;
     RECT  40.032 1.675 41.058 1.723 ;
     RECT  42.66 1.175 43.074 1.723 ;
     RECT  45.468 1.175 45.486 1.723 ;
     RECT  46.512 1.627 46.566 1.723 ;
     RECT  47.34 0.571 48.006 1.723 ;
     RECT  49.644 1.675 49.662 1.723 ;
     RECT  50.652 0.571 50.778 1.723 ;
     RECT  51.516 1.675 51.894 1.723 ;
     RECT  52.704 1.195 55.242 1.723 ;
     RECT  56.124 0.571 56.61 1.723 ;
     RECT  57.528 1.675 57.546 1.723 ;
     RECT  58.644 1.675 58.662 1.723 ;
     RECT  61.668 0.091 61.686 1.723 ;
     RECT  64.404 0.941 64.494 1.723 ;
     RECT  67.824 1.003 68.742 1.723 ;
     RECT  39.024 1.723 41.778 1.771 ;
     RECT  60.804 1.723 61.686 1.771 ;
     RECT  62.748 0.139 62.766 1.771 ;
     RECT  63.936 1.723 64.494 1.771 ;
     RECT  65.664 1.481 65.934 1.771 ;
     RECT  10.8 1.525 13.95 1.795 ;
     RECT  14.724 0.877 19.53 1.795 ;
     RECT  67.14 1.723 68.742 1.867 ;
     RECT  69.552 1.525 77.814 1.867 ;
     RECT  10.8 1.795 19.53 1.876 ;
     RECT  20.34 0.859 22.914 1.876 ;
     RECT  23.868 0.667 24.786 1.915 ;
     RECT  25.632 1.723 29.106 1.915 ;
     RECT  10.8 1.876 22.914 1.993 ;
     RECT  23.868 1.915 29.106 1.993 ;
     RECT  45.468 1.723 45.594 2.011 ;
     RECT  46.512 1.723 57.546 2.011 ;
     RECT  42.66 1.723 44.55 2.101 ;
     RECT  45.468 2.011 57.546 2.101 ;
     RECT  63.936 1.771 65.934 2.101 ;
     RECT  67.14 1.867 77.814 2.101 ;
     RECT  10.8 1.993 29.106 2.143 ;
     RECT  30.132 1.723 34.254 2.143 ;
     RECT  35.136 1.723 35.334 2.143 ;
     RECT  67.068 2.101 77.814 2.143 ;
     RECT  36.18 1.147 38.286 2.191 ;
     RECT  39.024 1.771 41.886 2.191 ;
     RECT  42.66 2.101 57.546 2.191 ;
     RECT  58.572 1.723 58.662 2.191 ;
     RECT  59.904 0.091 59.922 2.191 ;
     RECT  60.66 1.771 62.766 2.191 ;
     RECT  63.756 2.101 65.934 2.191 ;
     RECT  10.8 2.143 35.334 2.219 ;
     RECT  42.66 2.191 58.662 2.227 ;
     RECT  10.836 2.219 35.334 2.263 ;
     RECT  36.18 2.191 41.886 2.263 ;
     RECT  42.66 2.227 59.13 2.263 ;
     RECT  59.904 2.191 62.766 2.263 ;
     RECT  63.72 2.191 65.934 2.263 ;
     RECT  67.068 2.143 78.105 2.263 ;
     RECT  10.836 2.263 41.886 2.335 ;
     RECT  42.66 2.263 78.105 2.335 ;
     RECT  2.415 2.143 2.505 2.413 ;
     RECT  7.815 2.143 7.905 2.413 ;
     RECT  10.836 2.335 78.105 2.413 ;
     RECT  83.415 2.143 83.505 2.413 ;
     RECT  10.836 2.413 78.297 2.759 ;
     RECT  10.872 2.759 78.297 2.903 ;
     RECT  10.872 2.903 77.166 3.101 ;
     RECT  11.304 3.101 77.166 3.443 ;
     RECT  11.556 3.443 77.166 3.479 ;
     RECT  11.556 3.479 76.986 3.713 ;
     RECT  76.68 3.713 76.986 3.911 ;
     RECT  11.556 3.713 75.87 4.289 ;
     RECT  11.988 4.289 75.87 4.487 ;
     RECT  76.68 3.911 76.77 4.559 ;
     RECT  11.988 4.487 75.834 5.369 ;
     RECT  11.988 5.369 74.79 5.531 ;
     RECT  14.328 5.531 74.79 5.909 ;
     RECT  76.716 4.559 76.77 6.035 ;
     RECT  11.988 5.531 13.497 6.107 ;
     RECT  14.724 5.909 74.394 6.305 ;
     RECT  11.988 6.107 12.006 6.377 ;
     RECT  75.816 5.369 75.834 6.719 ;
     RECT  14.724 6.305 74.178 7.231 ;
     RECT  14.724 7.231 74.646 7.259 ;
     RECT  76.716 6.035 76.734 7.259 ;
     RECT  15.228 7.259 74.646 7.349 ;
     RECT  15.228 7.349 74.178 8.069 ;
     RECT  15.228 8.069 73.854 8.843 ;
     RECT  73.836 8.843 73.854 9.149 ;
     RECT  15.228 8.843 72.897 9.211 ;
     RECT  15.012 9.211 72.897 9.391 ;
     RECT  14.328 9.391 72.897 9.895 ;
     RECT  14.292 9.895 72.897 11.399 ;
     RECT  11.88 12.091 11.898 12.209 ;
     RECT  14.328 11.399 71.442 13.019 ;
     RECT  2.415 2.413 2.697 15.403 ;
     RECT  3.528 12.217 3.546 15.449 ;
     RECT  2.304 15.403 2.697 15.565 ;
     RECT  2.304 15.565 3.33 15.719 ;
     RECT  2.304 15.719 2.697 15.755 ;
     RECT  14.328 13.019 71.226 15.965 ;
     RECT  47.628 15.965 71.226 15.989 ;
     RECT  47.628 15.989 70.83 16.529 ;
     RECT  72.18 11.399 72.897 16.799 ;
     RECT  14.328 15.965 46.818 16.951 ;
     RECT  47.628 16.529 70.722 16.951 ;
     RECT  71.784 16.951 71.802 17.069 ;
     RECT  14.328 16.951 70.722 18.769 ;
     RECT  14.328 18.769 70.758 18.959 ;
     RECT  14.328 18.959 70.542 19.337 ;
     RECT  14.328 19.337 70.146 19.499 ;
     RECT  14.4 19.499 70.146 20.579 ;
     RECT  70.128 20.579 70.146 21.389 ;
     RECT  14.4 20.579 69.246 22.199 ;
     RECT  14.4 22.199 68.418 22.739 ;
     RECT  69.228 22.199 69.246 23.009 ;
     RECT  69.084 23.161 69.174 23.279 ;
     RECT  69.084 23.279 69.102 23.315 ;
     RECT  14.4 22.739 68.31 23.549 ;
     RECT  14.4 23.549 68.202 23.585 ;
     RECT  14.4 23.585 68.094 24.089 ;
     RECT  14.4 24.089 67.497 24.205 ;
     RECT  13.215 6.107 13.497 25.555 ;
     RECT  14.22 24.205 67.497 25.555 ;
     RECT  2.415 15.755 2.697 25.667 ;
     RECT  7.815 2.413 8.097 25.667 ;
     RECT  13.215 25.555 67.497 25.667 ;
     RECT  72.615 16.799 72.897 25.667 ;
     RECT  78.015 2.903 78.297 25.667 ;
     RECT  83.415 2.413 83.697 25.667 ;
     RECT  14.112 25.667 67.305 25.745 ;
     RECT  28.8 25.745 67.305 25.817 ;
     RECT  14.112 25.745 28.026 25.853 ;
     RECT  14.112 25.853 16.398 25.901 ;
     RECT  17.136 25.853 21.042 25.901 ;
     RECT  21.96 25.853 28.026 25.901 ;
     RECT  28.908 25.817 67.305 25.901 ;
     RECT  2.415 25.667 2.505 25.937 ;
     RECT  7.815 25.667 7.905 25.937 ;
     RECT  13.215 25.667 13.305 25.937 ;
     RECT  45.288 25.901 67.305 25.937 ;
     RECT  72.615 25.667 72.705 25.937 ;
     RECT  78.015 25.667 78.105 25.937 ;
     RECT  83.415 25.667 83.505 25.937 ;
     RECT  15.3 25.901 15.966 25.949 ;
     RECT  18.36 25.901 19.926 25.949 ;
     RECT  20.736 25.901 20.934 25.949 ;
     RECT  21.96 25.901 23.058 25.949 ;
     RECT  36.864 25.901 37.602 25.949 ;
     RECT  38.484 25.901 38.754 25.949 ;
     RECT  18.36 25.949 19.782 25.979 ;
     RECT  20.736 25.949 20.754 25.979 ;
     RECT  17.244 25.901 17.622 25.997 ;
     RECT  18.36 25.979 19.35 25.997 ;
     RECT  25.884 25.901 28.026 25.997 ;
     RECT  36.864 25.949 36.954 25.997 ;
     RECT  23.976 25.901 24.93 26.045 ;
     RECT  30.78 25.901 35.334 26.045 ;
     RECT  18.36 25.997 19.278 26.093 ;
     RECT  30.78 26.045 35.082 26.093 ;
     RECT  40.14 25.901 44.442 26.093 ;
     RECT  18.36 26.093 18.594 26.141 ;
     RECT  23.976 26.045 24.894 26.141 ;
     RECT  25.884 25.997 25.902 26.141 ;
     RECT  40.14 26.093 40.158 26.141 ;
     RECT  22.104 25.949 23.058 26.189 ;
     RECT  30.78 26.093 34.794 26.189 ;
     RECT  41.076 26.093 44.442 26.189 ;
     RECT  45.288 25.937 66.69 26.189 ;
     RECT  15.804 25.949 15.822 26.237 ;
     RECT  17.244 25.997 17.262 26.237 ;
     RECT  18.36 26.141 18.378 26.237 ;
     RECT  22.104 26.189 22.95 26.237 ;
     RECT  24.336 26.141 24.894 26.237 ;
     RECT  26.64 25.997 27.27 26.237 ;
     RECT  28.008 25.997 28.026 26.237 ;
     RECT  29.304 25.901 29.754 26.237 ;
     RECT  30.78 26.189 34.722 26.237 ;
     RECT  38.484 25.949 38.502 26.237 ;
     RECT  41.076 26.189 44.334 26.237 ;
     RECT  45.288 26.189 45.99 26.237 ;
     RECT  47.268 26.189 54.09 26.237 ;
     RECT  55.872 26.189 66.51 26.237 ;
     RECT  47.268 26.237 51.858 26.285 ;
     RECT  60.66 26.237 61.038 26.285 ;
     RECT  30.78 26.237 34.182 26.717 ;
     RECT  22.392 26.237 22.77 26.765 ;
     RECT  14.148 25.901 14.166 26.813 ;
     RECT  22.752 26.765 22.77 26.813 ;
     RECT  24.372 26.237 24.39 26.813 ;
     RECT  29.34 26.237 29.358 26.813 ;
     RECT  31.464 26.717 34.182 26.813 ;
     RECT  47.268 26.285 50.166 26.813 ;
     RECT  50.976 26.285 51.858 26.813 ;
     RECT  52.632 26.237 52.65 26.813 ;
     RECT  53.568 26.237 53.586 26.813 ;
     RECT  31.464 26.813 34.146 26.861 ;
     RECT  47.268 26.813 49.554 26.861 ;
     RECT  32.4 26.861 34.146 26.909 ;
     RECT  56.376 26.237 56.394 27.293 ;
     RECT  47.268 26.861 48.186 27.341 ;
     RECT  31.464 26.861 31.482 27.389 ;
     RECT  32.4 26.909 33.714 27.389 ;
     RECT  36.864 25.997 36.882 27.389 ;
     RECT  47.268 27.341 48.078 27.389 ;
     RECT  49.536 26.861 49.554 27.389 ;
     RECT  50.976 26.813 51.714 27.389 ;
     RECT  32.4 27.389 33.066 27.437 ;
     RECT  47.268 27.389 47.286 27.437 ;
     RECT  33.048 27.437 33.066 27.485 ;
     RECT  39.996 27.835 40.014 27.965 ;
     RECT  41.508 26.237 41.526 27.965 ;
     RECT  45.288 26.237 45.306 27.965 ;
     RECT  51.516 27.389 51.534 27.965 ;
     RECT  62.388 26.237 62.406 27.965 ;
     RECT  46.548 27.931 46.566 28.061 ;
     RECT  48.06 27.389 48.078 28.061 ;
    LAYER M4 ;
     RECT  0.06 15.312 0.179 15.432 ;
     RECT  0.133 13.584 2.408 13.608 ;
     RECT  0.179 15.408 2.408 15.432 ;
     RECT  2.408 2.148 2.512 25.932 ;
     RECT  2.512 2.418 2.704 25.662 ;
     RECT  2.704 13.584 7.808 13.608 ;
     RECT  7.808 2.148 7.912 25.932 ;
     RECT  7.912 2.418 8.104 25.662 ;
     RECT  11.509 3.024 11.725 3.048 ;
     RECT  11.725 2.064 11.833 3.048 ;
     RECT  11.833 2.064 11.941 3.864 ;
     RECT  12.481 0.144 12.841 0.168 ;
     RECT  11.941 1.92 13.208 3.864 ;
     RECT  8.104 13.584 13.208 13.608 ;
     RECT  13.208 1.92 13.504 25.932 ;
     RECT  12.841 0.144 13.669 0.216 ;
     RECT  13.504 25.68 14.137 25.932 ;
     RECT  14.137 25.68 14.291 26.808 ;
     RECT  13.504 1.92 14.821 3.864 ;
     RECT  13.669 0.144 14.857 0.888 ;
     RECT  14.857 0.048 14.929 0.888 ;
     RECT  14.821 1.92 14.929 4.68 ;
     RECT  15.145 19.92 15.205 19.944 ;
     RECT  15.205 19.92 15.229 20.472 ;
     RECT  15.325 8.352 15.469 8.376 ;
     RECT  15.469 7.44 15.577 8.376 ;
     RECT  15.596 19.104 15.683 19.128 ;
     RECT  15.229 20.448 15.725 20.472 ;
     RECT  14.291 25.68 15.749 25.944 ;
     RECT  15.577 7.44 15.781 8.568 ;
     RECT  13.504 10.224 15.781 10.248 ;
     RECT  15.781 7.44 15.827 10.248 ;
     RECT  15.749 25.68 15.833 26.232 ;
     RECT  15.827 8.832 15.868 10.248 ;
     RECT  15.827 7.44 15.901 7.512 ;
     RECT  15.901 16.512 15.985 16.536 ;
     RECT  15.868 9.696 16.013 10.248 ;
     RECT  15.901 7.344 16.117 7.512 ;
     RECT  14.821 27.888 16.165 27.912 ;
     RECT  16.165 27.792 16.259 27.912 ;
     RECT  16.181 22.176 16.264 22.2 ;
     RECT  14.929 0.048 16.333 4.68 ;
     RECT  16.264 22.128 16.355 22.2 ;
     RECT  16.259 27.792 16.355 27.816 ;
     RECT  16.117 6.672 16.513 7.512 ;
     RECT  16.369 10.848 16.517 10.872 ;
     RECT  16.453 22.224 16.549 22.248 ;
     RECT  16.333 0.048 16.837 4.728 ;
     RECT  16.513 6.288 16.837 7.512 ;
     RECT  15.833 25.68 16.837 25.944 ;
     RECT  16.549 22.224 17.021 22.824 ;
     RECT  16.837 25.68 17.273 26.232 ;
     RECT  17.021 22.224 17.453 22.632 ;
     RECT  16.013 9.696 17.521 9.72 ;
     RECT  15.793 17.568 17.521 17.592 ;
     RECT  17.521 17.568 17.585 18.216 ;
     RECT  17.521 9.648 17.629 9.72 ;
     RECT  16.837 0.048 17.941 7.512 ;
     RECT  17.273 25.68 18.349 25.992 ;
     RECT  18.349 25.68 18.433 26.232 ;
     RECT  18.433 25.68 18.469 26.136 ;
     RECT  13.504 13.584 18.565 13.608 ;
     RECT  16.621 15.312 18.565 15.336 ;
     RECT  17.941 0.048 18.608 8.472 ;
     RECT  17.629 9.648 18.608 10.872 ;
     RECT  18.565 13.584 18.608 15.864 ;
     RECT  17.585 17.568 18.608 18.84 ;
     RECT  17.053 21.12 18.608 21.144 ;
     RECT  17.453 22.608 18.608 22.632 ;
     RECT  18.469 25.008 18.608 26.136 ;
     RECT  18.608 0.048 18.707 26.136 ;
     RECT  18.707 0.048 18.904 26.088 ;
     RECT  18.904 0.048 19.043 9 ;
     RECT  18.904 22.8 19.043 26.088 ;
     RECT  18.904 15.84 19.289 18.024 ;
     RECT  19.043 23.904 19.289 26.088 ;
     RECT  19.289 23.904 19.369 25.992 ;
     RECT  19.369 25.008 19.379 25.992 ;
     RECT  19.289 15.84 19.433 16.872 ;
     RECT  19.433 16.608 19.541 16.872 ;
     RECT  19.043 22.8 19.613 22.872 ;
     RECT  19.429 27.888 19.715 27.912 ;
     RECT  19.369 23.904 19.757 23.928 ;
     RECT  19.379 25.008 19.829 25.944 ;
     RECT  18.904 10.32 19.933 10.824 ;
     RECT  19.829 25.68 19.937 25.944 ;
     RECT  18.904 20.496 19.948 21.384 ;
     RECT  18.904 19.344 20.045 19.368 ;
     RECT  19.043 0.096 20.108 9 ;
     RECT  19.933 10.32 20.108 10.872 ;
     RECT  19.613 22.848 20.113 22.872 ;
     RECT  19.289 18 20.149 18.024 ;
     RECT  20.113 22.848 20.189 23.4 ;
     RECT  20.149 18 20.233 18.84 ;
     RECT  20.189 23.232 20.513 23.4 ;
     RECT  18.904 13.584 20.545 14.856 ;
     RECT  20.108 0.096 20.549 10.872 ;
     RECT  18.904 12.528 20.629 12.552 ;
     RECT  20.629 11.952 20.716 12.552 ;
     RECT  20.545 13.584 20.837 15.384 ;
     RECT  19.937 25.68 20.905 25.896 ;
     RECT  20.716 12.528 20.909 12.552 ;
     RECT  20.513 23.376 20.977 23.4 ;
     RECT  20.905 25.68 21.061 25.944 ;
     RECT  20.549 0.096 21.107 10.776 ;
     RECT  19.541 16.608 21.109 16.632 ;
     RECT  20.233 18 21.109 18.024 ;
     RECT  20.977 23.376 21.109 23.928 ;
     RECT  21.061 25.056 21.109 25.944 ;
     RECT  21.109 23.376 21.197 25.944 ;
     RECT  19.948 20.496 21.229 20.52 ;
     RECT  21.229 19.92 21.269 20.52 ;
     RECT  21.109 16.608 21.341 18.024 ;
     RECT  21.197 25.056 21.349 25.944 ;
     RECT  20.837 13.584 21.409 13.608 ;
     RECT  21.341 17.616 21.683 18.024 ;
     RECT  21.107 10.752 21.845 10.776 ;
     RECT  20.837 14.784 21.845 15.384 ;
     RECT  21.349 25.056 22.021 26.184 ;
     RECT  21.733 21.696 22.057 21.72 ;
     RECT  21.197 23.376 22.213 23.928 ;
     RECT  22.057 21.648 22.273 21.72 ;
     RECT  21.107 0.096 22.277 9.432 ;
     RECT  22.021 25.056 22.309 26.232 ;
     RECT  21.409 13.488 22.381 13.608 ;
     RECT  22.309 25.056 22.381 26.664 ;
     RECT  22.213 23.232 22.417 23.928 ;
     RECT  22.381 25.056 22.417 26.76 ;
     RECT  22.277 9.024 22.421 9.432 ;
     RECT  22.453 18.768 22.481 18.792 ;
     RECT  22.481 18.768 22.508 18.84 ;
     RECT  21.269 19.92 22.508 19.944 ;
     RECT  22.273 21.648 22.549 22.2 ;
     RECT  22.417 23.232 22.549 26.76 ;
     RECT  22.549 21.648 22.637 26.76 ;
     RECT  22.508 18.768 22.705 19.944 ;
     RECT  22.453 11.76 22.741 11.784 ;
     RECT  21.341 16.608 22.741 16.632 ;
     RECT  22.637 24.192 22.741 26.76 ;
     RECT  21.683 17.616 22.789 17.64 ;
     RECT  22.705 18.768 22.789 20.472 ;
     RECT  22.741 16.512 22.813 16.632 ;
     RECT  22.789 17.616 22.813 20.472 ;
     RECT  22.813 16.512 22.837 20.472 ;
     RECT  22.637 21.648 22.837 22.248 ;
     RECT  22.837 16.512 22.883 22.248 ;
     RECT  22.381 13.008 22.885 13.608 ;
     RECT  22.741 10.8 22.921 11.784 ;
     RECT  21.845 15.36 22.921 15.384 ;
     RECT  22.883 16.512 22.921 19.656 ;
     RECT  22.921 15.36 22.925 19.656 ;
     RECT  22.741 24.192 22.931 26.808 ;
     RECT  22.931 24.192 23.027 26.232 ;
     RECT  23.027 24.192 23.069 26.184 ;
     RECT  22.921 10.8 23.497 11.976 ;
     RECT  22.885 13.008 23.641 13.944 ;
     RECT  22.925 15.36 23.641 17.496 ;
     RECT  22.277 0.096 23.749 7.992 ;
     RECT  22.421 9.024 23.749 9.336 ;
     RECT  22.883 22.224 23.785 22.248 ;
     RECT  23.653 27.888 23.843 27.912 ;
     RECT  22.883 20.976 23.965 21.144 ;
     RECT  23.749 0.096 24.008 9.336 ;
     RECT  23.497 10.416 24.008 11.976 ;
     RECT  23.641 13.008 24.008 17.496 ;
     RECT  22.925 18.768 24.008 19.656 ;
     RECT  23.965 20.976 24.008 21.192 ;
     RECT  23.785 22.224 24.008 22.776 ;
     RECT  23.069 24.192 24.008 26.136 ;
     RECT  24.008 0.096 24.229 26.136 ;
     RECT  24.229 0.096 24.304 26.184 ;
     RECT  24.304 25.68 24.325 26.184 ;
     RECT  24.325 25.68 24.361 26.232 ;
     RECT  24.304 18.768 24.365 19.656 ;
     RECT  24.304 21.168 24.419 21.192 ;
     RECT  24.304 22.176 24.437 24.504 ;
     RECT  24.361 25.68 24.563 26.808 ;
     RECT  24.365 18.768 24.589 19.512 ;
     RECT  24.304 15.84 24.725 17.736 ;
     RECT  24.304 10.848 24.761 12.552 ;
     RECT  24.437 23.376 24.905 24.504 ;
     RECT  24.563 25.68 24.949 26.232 ;
     RECT  24.304 0.096 25.013 9.576 ;
     RECT  24.905 23.856 25.121 24.504 ;
     RECT  25.121 23.904 25.229 24.504 ;
     RECT  24.437 22.176 25.369 22.2 ;
     RECT  24.304 13.584 25.381 14.856 ;
     RECT  25.369 22.032 25.405 22.2 ;
     RECT  25.381 13.584 25.468 15.192 ;
     RECT  24.589 19.488 25.469 19.512 ;
     RECT  25.405 22.032 25.517 22.824 ;
     RECT  25.469 19.488 25.553 19.992 ;
     RECT  25.189 27.888 25.667 27.912 ;
     RECT  25.468 13.584 25.669 14.712 ;
     RECT  25.229 23.904 25.705 23.928 ;
     RECT  24.761 10.848 25.729 11.88 ;
     RECT  24.725 16.512 25.733 17.736 ;
     RECT  25.729 10.752 25.981 11.88 ;
     RECT  25.669 12.864 25.981 14.712 ;
     RECT  25.013 0.096 26.017 9.24 ;
     RECT  26.017 0.096 26.099 9.288 ;
     RECT  24.949 25.68 26.149 26.136 ;
     RECT  26.099 0.48 26.233 9.288 ;
     RECT  26.233 0.48 26.341 9.576 ;
     RECT  26.149 25.056 26.341 26.136 ;
     RECT  26.341 0.48 26.444 9.672 ;
     RECT  25.981 10.752 26.444 14.712 ;
     RECT  26.341 25.056 26.629 26.232 ;
     RECT  25.733 16.512 26.773 17.256 ;
     RECT  26.557 23.52 27.101 23.544 ;
     RECT  26.881 21.024 27.109 21.048 ;
     RECT  25.517 22.032 27.109 22.056 ;
     RECT  27.109 21.024 27.155 22.056 ;
     RECT  26.773 16.512 27.169 17.352 ;
     RECT  27.169 16.464 27.205 17.352 ;
     RECT  26.444 0.48 27.241 14.712 ;
     RECT  27.205 16.464 27.289 17.688 ;
     RECT  27.241 0.48 27.349 14.952 ;
     RECT  27.349 0.192 27.385 14.952 ;
     RECT  27.289 16.464 27.385 17.064 ;
     RECT  25.553 19.488 27.389 19.512 ;
     RECT  26.629 25.008 27.389 26.232 ;
     RECT  27.155 21.504 27.493 22.056 ;
     RECT  27.389 25.2 27.497 26.232 ;
     RECT  27.385 0.192 27.634 17.064 ;
     RECT  27.634 0.096 27.757 17.064 ;
     RECT  27.497 25.296 28.037 26.232 ;
     RECT  27.757 0.192 28.115 17.064 ;
     RECT  27.493 21.504 28.393 23.16 ;
     RECT  28.115 0.576 28.573 17.064 ;
     RECT  28.573 0.576 28.681 17.256 ;
     RECT  28.681 0.576 28.825 17.448 ;
     RECT  27.781 18.72 28.825 19.368 ;
     RECT  28.037 25.296 28.981 25.896 ;
     RECT  28.825 0.576 29.005 19.608 ;
     RECT  28.393 21.216 29.005 23.16 ;
     RECT  29.005 0.576 29.041 23.16 ;
     RECT  28.981 24.528 29.041 25.896 ;
     RECT  29.041 0.576 29.077 25.896 ;
     RECT  29.077 0.24 29.173 25.896 ;
     RECT  29.173 0.144 29.269 25.896 ;
     RECT  29.269 0.144 29.293 26.088 ;
     RECT  29.293 0.144 29.329 26.232 ;
     RECT  29.329 0.144 29.704 26.808 ;
     RECT  29.704 25.296 29.747 26.808 ;
     RECT  29.704 0.144 29.789 1.752 ;
     RECT  29.789 0.096 29.873 1.752 ;
     RECT  29.704 2.832 30.413 24.216 ;
     RECT  29.873 0.144 30.611 1.752 ;
     RECT  30.413 2.832 30.673 21.432 ;
     RECT  29.747 25.296 30.725 26.232 ;
     RECT  30.725 25.296 30.757 26.712 ;
     RECT  30.757 25.296 30.853 27.768 ;
     RECT  30.413 22.752 30.917 24.216 ;
     RECT  30.853 25.296 30.985 27.864 ;
     RECT  30.985 25.248 31.043 27.864 ;
     RECT  30.917 22.752 31.313 22.776 ;
     RECT  30.673 3.36 31.561 21.432 ;
     RECT  30.917 23.856 31.673 24.216 ;
     RECT  30.611 1.152 31.817 1.752 ;
     RECT  31.673 24.192 31.817 24.216 ;
     RECT  31.561 3.36 31.877 21.672 ;
     RECT  31.043 25.248 31.921 26.232 ;
     RECT  31.877 3.312 31.961 21.672 ;
     RECT  31.961 3.408 32.069 21.672 ;
     RECT  31.921 24.528 32.101 26.232 ;
     RECT  31.043 27.36 32.101 27.384 ;
     RECT  31.013 0.096 32.197 0.12 ;
     RECT  31.817 1.152 32.197 1.176 ;
     RECT  32.101 24.528 32.339 27.384 ;
     RECT  32.069 20.304 32.357 21.672 ;
     RECT  32.339 25.248 32.389 27.384 ;
     RECT  32.389 25.248 32.573 27.432 ;
     RECT  32.069 3.408 32.609 18.84 ;
     RECT  32.197 0.096 32.627 1.176 ;
     RECT  32.627 0.096 32.645 0.552 ;
     RECT  32.357 21.168 32.825 21.672 ;
     RECT  32.645 0.144 33.011 0.552 ;
     RECT  32.573 25.68 33.037 27.432 ;
     RECT  32.609 3.408 33.041 18.168 ;
     RECT  33.041 3.408 33.253 15.24 ;
     RECT  33.037 25.68 33.299 27.48 ;
     RECT  33.245 1.728 33.433 1.752 ;
     RECT  33.253 3.12 33.433 15.24 ;
     RECT  33.433 1.728 33.473 15.24 ;
     RECT  32.825 21.168 33.653 21.192 ;
     RECT  33.473 1.728 33.925 14.808 ;
     RECT  33.925 1.248 34.021 14.808 ;
     RECT  34.081 19.584 34.22 19.608 ;
     RECT  33.011 0.144 34.261 0.168 ;
     RECT  34.021 1.152 34.261 14.808 ;
     RECT  34.261 0.144 34.309 14.808 ;
     RECT  33.299 25.68 34.355 27.384 ;
     RECT  34.355 27.36 34.451 27.384 ;
     RECT  32.065 22.8 34.477 22.824 ;
     RECT  34.309 0.096 34.739 14.808 ;
     RECT  34.355 25.68 34.777 26.232 ;
     RECT  34.739 1.728 34.808 14.808 ;
     RECT  33.041 16.56 34.808 18.168 ;
     RECT  34.22 19.2 34.808 19.608 ;
     RECT  34.477 22.8 34.808 23.352 ;
     RECT  34.777 25.68 34.808 26.184 ;
     RECT  34.808 1.728 34.931 26.184 ;
     RECT  34.931 1.728 35.104 26.088 ;
     RECT  35.104 25.68 35.137 26.088 ;
     RECT  35.104 15.984 35.273 17.16 ;
     RECT  35.104 22.8 35.273 24.168 ;
     RECT  35.104 1.728 35.315 14.808 ;
     RECT  35.315 1.728 35.345 1.752 ;
     RECT  35.137 25.68 35.345 26.04 ;
     RECT  35.315 2.736 35.705 14.808 ;
     RECT  35.104 18.144 35.921 18.168 ;
     RECT  34.739 0.096 35.941 0.6 ;
     RECT  35.705 2.736 35.993 13.608 ;
     RECT  35.273 22.8 35.993 23.352 ;
     RECT  35.705 14.736 36.205 14.808 ;
     RECT  35.273 15.984 36.205 16.008 ;
     RECT  35.941 0.096 36.209 1.272 ;
     RECT  36.133 27.888 36.323 27.912 ;
     RECT  36.277 23.856 36.364 23.88 ;
     RECT  35.993 11.904 36.371 13.608 ;
     RECT  36.205 14.736 36.389 16.008 ;
     RECT  35.993 2.736 36.421 10.92 ;
     RECT  36.389 15.984 36.493 16.008 ;
     RECT  35.273 16.992 36.493 17.16 ;
     RECT  35.104 20.304 36.605 20.328 ;
     RECT  36.421 1.728 36.829 10.92 ;
     RECT  36.829 10.32 36.857 10.92 ;
     RECT  36.493 15.984 36.893 17.16 ;
     RECT  35.345 25.68 36.925 25.896 ;
     RECT  36.371 11.952 36.929 13.608 ;
     RECT  36.857 10.32 36.965 10.872 ;
     RECT  36.889 19.392 37.001 19.416 ;
     RECT  36.925 25.68 37.043 25.992 ;
     RECT  36.929 13.104 37.361 13.608 ;
     RECT  36.209 0.096 37.393 0.6 ;
     RECT  36.829 1.728 37.393 9.24 ;
     RECT  37.393 0.096 37.523 9.24 ;
     RECT  36.893 16.608 37.532 17.16 ;
     RECT  37.141 21.648 37.573 21.672 ;
     RECT  37.532 16.608 37.619 17.64 ;
     RECT  35.993 22.8 37.717 22.824 ;
     RECT  37.523 1.728 37.721 9.24 ;
     RECT  37.721 2.88 37.763 9.144 ;
     RECT  37.717 22.752 37.789 22.824 ;
     RECT  36.965 10.32 37.793 10.824 ;
     RECT  37.523 0.096 37.865 0.36 ;
     RECT  37.865 0.144 37.955 0.36 ;
     RECT  37.361 13.344 38.005 13.608 ;
     RECT  36.389 14.736 38.005 14.76 ;
     RECT  37.619 16.608 38.009 17.112 ;
     RECT  38.005 13.344 38.045 14.76 ;
     RECT  37.793 10.8 38.081 10.824 ;
     RECT  36.853 27.36 38.099 27.384 ;
     RECT  37.789 22.704 38.117 22.824 ;
     RECT  37.763 2.928 38.153 9.144 ;
     RECT  37.721 1.728 38.233 1.896 ;
     RECT  37.955 0.144 38.339 0.264 ;
     RECT  38.009 16.608 38.437 16.824 ;
     RECT  37.043 25.68 38.473 25.944 ;
     RECT  38.153 3.552 38.531 9.144 ;
     RECT  38.473 25.68 38.579 26.232 ;
     RECT  36.929 11.952 38.617 12.072 ;
     RECT  38.531 8.544 38.729 9.144 ;
     RECT  38.579 25.68 38.771 25.944 ;
     RECT  37.573 21.12 38.797 21.672 ;
     RECT  38.617 11.424 39.011 12.072 ;
     RECT  38.117 22.752 39.049 22.824 ;
     RECT  38.941 24.192 39.049 24.216 ;
     RECT  39.049 22.752 39.125 24.216 ;
     RECT  39.013 0.576 39.155 1.128 ;
     RECT  38.797 21.072 39.155 21.672 ;
     RECT  38.531 3.552 39.157 7.512 ;
     RECT  39.155 21.072 39.161 21.144 ;
     RECT  38.437 15.984 39.197 16.824 ;
     RECT  39.157 2.88 39.397 7.512 ;
     RECT  39.397 2.304 39.493 7.512 ;
     RECT  39.493 1.68 39.517 7.512 ;
     RECT  38.729 8.544 39.517 8.568 ;
     RECT  38.045 13.344 39.661 14.376 ;
     RECT  39.125 22.8 39.781 24.216 ;
     RECT  38.771 25.68 39.781 25.896 ;
     RECT  39.155 0.576 39.829 0.696 ;
     RECT  39.517 1.68 39.925 8.568 ;
     RECT  39.877 27.792 39.941 27.912 ;
     RECT  39.781 22.8 39.973 25.896 ;
     RECT  39.941 27.792 40.025 27.96 ;
     RECT  39.973 22.8 40.129 26.088 ;
     RECT  40.025 27.792 40.163 27.912 ;
     RECT  39.925 1.68 40.208 8.76 ;
     RECT  39.011 11.424 40.208 12.024 ;
     RECT  39.661 13.152 40.208 14.376 ;
     RECT  39.197 15.984 40.208 16.008 ;
     RECT  39.409 17.088 40.208 17.112 ;
     RECT  37.681 19.92 40.208 19.944 ;
     RECT  39.161 21.12 40.208 21.144 ;
     RECT  40.129 22.8 40.208 26.136 ;
     RECT  40.208 1.68 40.211 26.136 ;
     RECT  40.163 27.792 40.211 27.816 ;
     RECT  40.211 2.148 40.312 26.136 ;
     RECT  39.829 0.144 40.403 0.696 ;
     RECT  40.312 2.418 40.504 26.136 ;
     RECT  40.403 0.144 40.549 0.6 ;
     RECT  40.549 0.096 40.781 0.6 ;
     RECT  40.504 22.848 40.925 22.872 ;
     RECT  40.504 21.648 40.961 21.672 ;
     RECT  40.504 25.248 41.029 26.136 ;
     RECT  40.781 0.144 41.113 0.6 ;
     RECT  40.504 3.408 41.141 11.976 ;
     RECT  40.504 23.856 41.141 23.88 ;
     RECT  41.141 4.512 41.177 11.976 ;
     RECT  40.504 15.984 41.356 18.744 ;
     RECT  41.141 3.408 41.557 3.48 ;
     RECT  41.029 25.248 41.609 26.232 ;
     RECT  41.557 3.312 41.641 3.48 ;
     RECT  41.177 9.648 41.641 11.976 ;
     RECT  40.504 13.104 41.641 13.608 ;
     RECT  41.497 27.936 41.651 27.96 ;
     RECT  41.317 1.728 41.843 1.8 ;
     RECT  41.843 1.776 41.941 1.8 ;
     RECT  41.641 3.264 42.037 3.48 ;
     RECT  41.641 9.648 42.133 13.608 ;
     RECT  42.037 21.648 42.133 21.672 ;
     RECT  41.177 4.512 42.145 8.568 ;
     RECT  42.145 4.512 42.181 8.664 ;
     RECT  42.133 9.648 42.181 14.424 ;
     RECT  42.037 2.304 42.185 3.48 ;
     RECT  41.356 15.984 42.185 16.728 ;
     RECT  42.133 21.648 42.22 22.488 ;
     RECT  41.356 18.384 42.245 18.744 ;
     RECT  42.185 16.656 42.293 16.728 ;
     RECT  41.609 25.68 42.323 26.232 ;
     RECT  42.22 21.648 42.401 22.296 ;
     RECT  42.323 25.728 42.419 26.232 ;
     RECT  42.181 4.464 42.433 8.664 ;
     RECT  41.113 0.144 42.469 0.168 ;
     RECT  42.433 3.984 42.469 8.664 ;
     RECT  42.181 9.648 42.469 14.712 ;
     RECT  42.469 3.984 42.473 14.712 ;
     RECT  42.469 0.144 42.533 0.6 ;
     RECT  42.419 25.824 42.611 26.232 ;
     RECT  42.245 18.384 42.613 18.84 ;
     RECT  40.504 19.92 42.901 19.944 ;
     RECT  42.533 0.096 42.941 0.6 ;
     RECT  42.613 18.24 43.009 18.84 ;
     RECT  42.941 0.576 43.085 0.6 ;
     RECT  42.901 19.92 43.085 20.184 ;
     RECT  42.185 2.304 43.189 2.856 ;
     RECT  43.189 2.304 43.225 2.904 ;
     RECT  42.401 21.648 43.237 22.248 ;
     RECT  42.293 16.656 43.265 16.68 ;
     RECT  43.237 20.448 43.265 22.248 ;
     RECT  43.009 17.904 43.285 18.84 ;
     RECT  43.225 1.728 43.333 2.904 ;
     RECT  43.285 17.664 43.333 18.84 ;
     RECT  42.473 3.984 43.337 14.424 ;
     RECT  43.333 17.664 43.373 19.032 ;
     RECT  43.373 17.904 43.517 19.032 ;
     RECT  43.265 22.224 43.588 22.248 ;
     RECT  42.253 23.952 43.589 23.976 ;
     RECT  43.333 1.728 43.669 3 ;
     RECT  43.337 3.984 43.669 9.144 ;
     RECT  42.611 26.064 43.717 26.232 ;
     RECT  43.717 26.016 43.793 26.232 ;
     RECT  43.765 23.328 43.907 23.352 ;
     RECT  43.588 22.224 44.053 22.296 ;
     RECT  43.337 10.128 44.089 14.424 ;
     RECT  44.005 0.24 44.189 0.264 ;
     RECT  43.517 17.904 44.201 18.792 ;
     RECT  44.189 0.096 44.273 0.264 ;
     RECT  43.793 25.728 44.345 26.232 ;
     RECT  43.265 20.448 44.349 21.144 ;
     RECT  44.053 22.224 44.349 22.824 ;
     RECT  44.345 25.728 44.453 26.184 ;
     RECT  44.349 20.448 44.597 22.824 ;
     RECT  43.669 1.728 44.665 8.856 ;
     RECT  44.089 10.128 44.665 14.664 ;
     RECT  44.453 25.728 44.677 26.088 ;
     RECT  44.665 1.728 44.701 14.664 ;
     RECT  44.273 0.144 45.02 0.264 ;
     RECT  45.02 0.144 45.061 0.6 ;
     RECT  44.701 1.728 45.097 15.048 ;
     RECT  45.061 0.144 45.155 0.696 ;
     RECT  44.597 21.216 45.157 22.824 ;
     RECT  44.869 27.936 45.317 27.96 ;
     RECT  45.155 0.144 45.425 0.6 ;
     RECT  45.097 1.728 45.493 16.008 ;
     RECT  44.677 25.68 45.493 26.088 ;
     RECT  45.493 1.728 45.601 16.824 ;
     RECT  45.601 1.728 45.608 17.112 ;
     RECT  44.201 18.768 45.608 18.792 ;
     RECT  45.157 21.216 45.608 23.16 ;
     RECT  43.861 24.432 45.608 24.504 ;
     RECT  45.493 25.68 45.608 26.136 ;
     RECT  45.608 1.728 45.733 26.136 ;
     RECT  45.733 1.728 45.904 26.184 ;
     RECT  45.904 25.68 45.925 26.184 ;
     RECT  45.925 25.68 46.012 26.232 ;
     RECT  45.425 0.144 46.019 0.216 ;
     RECT  45.904 1.728 46.019 15.048 ;
     RECT  46.019 1.728 46.037 2.904 ;
     RECT  46.019 3.888 46.109 15.048 ;
     RECT  46.019 0.144 46.115 0.168 ;
     RECT  45.904 23.376 46.355 23.4 ;
     RECT  46.213 27.36 46.493 27.384 ;
     RECT  46.037 1.728 46.501 2.28 ;
     RECT  46.493 27.36 46.537 27.96 ;
     RECT  46.405 0.096 46.577 0.12 ;
     RECT  46.501 1.632 46.585 2.28 ;
     RECT  46.585 1.728 46.757 2.28 ;
     RECT  46.109 3.888 46.757 14.808 ;
     RECT  46.012 25.68 46.829 26.184 ;
     RECT  45.904 20.496 46.937 21.48 ;
     RECT  45.904 24.48 46.981 24.504 ;
     RECT  46.829 25.68 46.981 26.088 ;
     RECT  46.757 3.888 47.029 11.16 ;
     RECT  46.757 1.776 47.045 2.28 ;
     RECT  45.904 18.528 47.064 18.792 ;
     RECT  47.045 2.256 47.113 2.28 ;
     RECT  46.757 12.528 47.125 14.808 ;
     RECT  45.904 17.088 47.125 17.112 ;
     RECT  46.969 15.936 47.171 15.96 ;
     RECT  47.113 2.256 47.197 2.376 ;
     RECT  47.125 17.088 47.212 17.304 ;
     RECT  47.197 2.352 47.219 2.376 ;
     RECT  47.125 12.528 47.267 14.856 ;
     RECT  47.064 18.384 47.297 18.792 ;
     RECT  47.029 3.36 47.699 11.16 ;
     RECT  47.329 0.576 47.725 0.6 ;
     RECT  47.699 6.864 47.789 11.16 ;
     RECT  47.725 0.096 47.891 0.6 ;
     RECT  47.699 3.36 47.941 5.784 ;
     RECT  47.297 18.576 48.013 18.792 ;
     RECT  47.891 0.576 48.017 0.6 ;
     RECT  46.537 27.36 48.037 28.056 ;
     RECT  46.981 24.48 48.085 26.088 ;
     RECT  48.037 27.312 48.089 28.056 ;
     RECT  48.089 27.312 48.197 27.336 ;
     RECT  47.761 15.696 48.233 15.72 ;
     RECT  47.789 6.864 48.236 11.448 ;
     RECT  47.267 12.528 48.236 14.568 ;
     RECT  48.013 18.576 48.337 19.368 ;
     RECT  48.337 18.576 48.373 19.464 ;
     RECT  46.937 20.496 48.373 20.52 ;
     RECT  48.373 18.576 48.481 20.52 ;
     RECT  48.236 6.864 48.517 14.568 ;
     RECT  47.212 17.088 48.517 17.112 ;
     RECT  48.481 18.336 48.517 20.52 ;
     RECT  47.941 2.88 48.709 5.784 ;
     RECT  48.301 1.728 48.757 1.752 ;
     RECT  48.709 2.832 48.757 5.784 ;
     RECT  48.517 17.088 48.773 20.52 ;
     RECT  48.773 17.088 48.809 19.464 ;
     RECT  48.757 1.728 48.853 5.784 ;
     RECT  48.853 1.152 48.869 5.784 ;
     RECT  48.085 24.48 48.877 26.232 ;
     RECT  48.869 1.152 48.908 5.832 ;
     RECT  48.517 6.864 48.908 15.528 ;
     RECT  48.809 17.088 49.021 17.112 ;
     RECT  48.908 1.152 49.025 15.528 ;
     RECT  49.021 16.992 49.061 17.112 ;
     RECT  48.809 18.336 49.349 19.464 ;
     RECT  48.877 24.48 49.525 26.856 ;
     RECT  49.525 24.48 49.619 27.384 ;
     RECT  49.349 18.576 49.813 19.464 ;
     RECT  48.773 20.496 49.813 20.52 ;
     RECT  49.025 1.152 50.005 1.752 ;
     RECT  49.025 2.832 50.005 15.528 ;
     RECT  50.005 1.152 50.033 15.528 ;
     RECT  49.813 18.576 50.129 20.52 ;
     RECT  50.129 18.576 50.425 21.144 ;
     RECT  49.061 16.992 50.497 17.016 ;
     RECT  50.425 18.144 50.497 21.144 ;
     RECT  50.033 2.016 50.629 15.528 ;
     RECT  50.497 16.992 50.629 21.144 ;
     RECT  50.597 0.096 50.705 0.12 ;
     RECT  49.619 24.48 50.773 26.808 ;
     RECT  50.773 24.336 50.869 26.808 ;
     RECT  50.869 22.752 50.965 26.808 ;
     RECT  50.629 2.016 51.008 21.144 ;
     RECT  50.965 22.752 51.008 27.384 ;
     RECT  50.705 0.096 51.205 0.792 ;
     RECT  51.008 2.016 51.205 27.384 ;
     RECT  51.205 0.096 51.304 27.384 ;
     RECT  51.304 20.064 51.365 21.768 ;
     RECT  51.304 24.912 51.397 27.384 ;
     RECT  51.365 21.744 51.401 21.768 ;
     RECT  51.304 18.096 51.545 18.84 ;
     RECT  51.397 24.912 51.545 27.96 ;
     RECT  51.304 2.784 51.761 17.064 ;
     RECT  51.545 24.912 51.923 27.384 ;
     RECT  51.761 2.784 52.204 16.968 ;
     RECT  51.545 18.096 52.265 18.168 ;
     RECT  52.204 3.312 52.373 16.968 ;
     RECT  51.365 20.064 52.405 20.52 ;
     RECT  52.297 21.792 52.441 21.816 ;
     RECT  52.441 21.648 52.453 21.816 ;
     RECT  51.304 0.096 52.517 1.752 ;
     RECT  52.517 0.192 52.547 1.752 ;
     RECT  52.547 0.288 52.733 1.752 ;
     RECT  52.453 21.552 52.765 21.816 ;
     RECT  52.405 19.344 52.877 20.52 ;
     RECT  52.765 21.552 52.913 22.104 ;
     RECT  52.373 3.312 52.985 16.296 ;
     RECT  52.733 1.44 53.017 1.752 ;
     RECT  51.304 23.28 53.029 23.304 ;
     RECT  52.877 19.344 53.075 20.088 ;
     RECT  53.017 1.44 53.201 2.232 ;
     RECT  52.265 18.096 53.201 18.12 ;
     RECT  52.733 0.288 53.453 0.312 ;
     RECT  52.913 21.792 53.557 22.104 ;
     RECT  53.029 23.28 53.557 23.4 ;
     RECT  53.557 21.792 53.561 23.4 ;
     RECT  53.561 21.792 53.597 23.304 ;
     RECT  51.923 24.912 53.651 26.808 ;
     RECT  52.985 3.312 53.705 15.72 ;
     RECT  53.201 1.728 53.845 2.232 ;
     RECT  53.705 3.312 53.845 10.728 ;
     RECT  53.705 11.808 53.849 15.72 ;
     RECT  53.075 19.344 54.029 19.368 ;
     RECT  53.485 16.8 54.169 16.824 ;
     RECT  54.085 0.096 54.173 0.12 ;
     RECT  54.169 16.656 54.389 16.824 ;
     RECT  53.597 21.792 54.524 22.776 ;
     RECT  54.524 21.12 54.611 22.776 ;
     RECT  53.845 1.728 54.673 10.728 ;
     RECT  53.849 11.808 54.673 15.192 ;
     RECT  54.611 21.216 54.7 22.776 ;
     RECT  54.673 1.728 54.713 15.192 ;
     RECT  54.389 16.752 54.713 16.824 ;
     RECT  54.7 21.216 54.713 21.24 ;
     RECT  54.713 1.728 54.737 1.752 ;
     RECT  54.737 1.152 55.009 1.752 ;
     RECT  55.009 1.2 55.253 1.752 ;
     RECT  54.713 16.752 55.253 16.776 ;
     RECT  54.713 7.344 55.321 15.192 ;
     RECT  54.133 18.96 55.484 18.984 ;
     RECT  55.484 18.576 55.525 18.984 ;
     RECT  54.713 2.784 55.717 6.312 ;
     RECT  55.321 7.344 55.717 15.432 ;
     RECT  55.753 17.04 55.813 17.064 ;
     RECT  55.525 18.576 55.813 19.368 ;
     RECT  54.7 22.752 55.861 22.776 ;
     RECT  55.237 0.096 56.005 0.12 ;
     RECT  56.005 0.096 56.153 0.6 ;
     RECT  55.253 1.728 56.408 1.752 ;
     RECT  55.717 2.784 56.408 15.432 ;
     RECT  55.813 17.04 56.408 19.368 ;
     RECT  55.933 20.544 56.408 20.568 ;
     RECT  55.861 22.32 56.408 22.776 ;
     RECT  55.933 23.856 56.408 23.88 ;
     RECT  53.651 24.912 56.408 26.232 ;
     RECT  56.365 27.264 56.531 27.288 ;
     RECT  56.153 0.096 56.627 0.552 ;
     RECT  56.408 1.728 56.704 26.232 ;
     RECT  56.704 23.856 56.765 23.88 ;
     RECT  56.627 0.096 56.867 0.168 ;
     RECT  56.704 21.792 56.867 22.824 ;
     RECT  56.581 27.888 56.867 27.912 ;
     RECT  56.704 19.152 56.981 20.664 ;
     RECT  56.981 20.016 57.017 20.664 ;
     RECT  56.867 22.08 57.017 22.824 ;
     RECT  57.017 22.32 57.148 22.824 ;
     RECT  57.148 22.32 57.161 22.728 ;
     RECT  57.017 20.64 57.299 20.664 ;
     RECT  56.704 9.024 57.341 17.544 ;
     RECT  57.161 22.704 57.36 22.728 ;
     RECT  57.341 9.024 57.395 17.064 ;
     RECT  56.704 1.728 57.445 7.992 ;
     RECT  57.445 1.68 57.521 7.992 ;
     RECT  57.395 9.024 57.539 15.384 ;
     RECT  57.521 1.68 57.557 1.704 ;
     RECT  56.867 0.096 57.923 0.12 ;
     RECT  57.539 14.016 58.163 15.384 ;
     RECT  58.163 14.496 58.205 14.52 ;
     RECT  56.704 24.912 58.241 26.232 ;
     RECT  57.521 2.88 58.489 7.992 ;
     RECT  57.539 9.024 58.489 12.264 ;
     RECT  58.501 1.728 58.549 1.752 ;
     RECT  58.489 2.88 58.561 12.264 ;
     RECT  58.549 1.728 58.589 1.848 ;
     RECT  58.561 2.832 58.669 12.264 ;
     RECT  58.589 1.68 58.673 1.848 ;
     RECT  58.669 2.832 58.693 13.032 ;
     RECT  58.693 2.832 58.753 13.32 ;
     RECT  58.753 2.832 58.835 12.264 ;
     RECT  57.395 16.8 58.949 17.064 ;
     RECT  58.949 16.8 58.957 17.16 ;
     RECT  58.837 0.144 59.027 0.168 ;
     RECT  58.835 2.832 59.101 11.688 ;
     RECT  59.101 2.256 59.141 11.688 ;
     RECT  59.141 2.256 59.185 2.328 ;
     RECT  59.141 3.408 59.267 11.688 ;
     RECT  59.18 15.312 59.267 15.336 ;
     RECT  58.957 16.512 59.269 17.16 ;
     RECT  58.525 21.648 59.269 21.672 ;
     RECT  58.345 23.376 59.269 23.4 ;
     RECT  59.269 21.648 59.315 23.4 ;
     RECT  59.267 3.408 59.321 11.592 ;
     RECT  59.315 22.176 59.356 23.304 ;
     RECT  59.321 3.408 59.357 11.544 ;
     RECT  59.269 16.512 59.489 17.64 ;
     RECT  58.345 19.2 59.555 19.224 ;
     RECT  59.357 3.696 59.573 11.544 ;
     RECT  59.489 16.512 59.573 18.216 ;
     RECT  59.845 0.096 59.933 0.12 ;
     RECT  59.281 24.528 59.941 24.552 ;
     RECT  58.241 25.68 59.941 26.232 ;
     RECT  59.356 23.28 60.149 23.304 ;
     RECT  59.185 2.304 60.253 2.328 ;
     RECT  59.573 4.176 60.365 11.544 ;
     RECT  60.253 2.256 60.389 2.328 ;
     RECT  60.389 2.256 60.517 2.376 ;
     RECT  59.356 22.176 60.517 22.2 ;
     RECT  60.289 19.344 60.572 19.368 ;
     RECT  60.517 22.176 60.577 22.248 ;
     RECT  59.941 24.528 60.605 26.232 ;
     RECT  60.572 19.344 60.613 19.752 ;
     RECT  60.613 18.96 60.659 19.752 ;
     RECT  60.365 4.176 60.709 11.448 ;
     RECT  60.517 1.728 60.721 2.376 ;
     RECT  60.721 1.728 60.805 2.472 ;
     RECT  60.709 3.744 60.805 11.448 ;
     RECT  60.757 20.112 60.956 20.136 ;
     RECT  60.721 14.784 60.981 14.808 ;
     RECT  58.753 13.296 61.073 13.32 ;
     RECT  60.605 24.528 61.084 26.28 ;
     RECT  60.577 22.176 61.189 22.776 ;
     RECT  61.189 22.176 61.285 23.4 ;
     RECT  61.084 24.528 61.285 26.232 ;
     RECT  61.477 0.144 61.621 0.168 ;
     RECT  61.621 0.144 61.657 0.216 ;
     RECT  59.573 16.512 61.669 17.64 ;
     RECT  61.657 0.096 61.741 0.216 ;
     RECT  60.805 1.728 61.765 11.448 ;
     RECT  61.073 12.528 61.765 13.32 ;
     RECT  61.765 1.728 61.808 13.416 ;
     RECT  60.981 14.784 61.808 15.336 ;
     RECT  61.669 16.368 61.808 17.64 ;
     RECT  60.659 18.96 61.808 18.984 ;
     RECT  60.956 20.112 61.808 21 ;
     RECT  61.285 22.176 61.808 26.232 ;
     RECT  61.741 0.144 61.811 0.216 ;
     RECT  61.808 1.728 62.104 26.232 ;
     RECT  62.104 1.728 62.243 6.936 ;
     RECT  62.333 27.936 62.417 27.96 ;
     RECT  62.243 1.728 62.533 6.84 ;
     RECT  62.104 18.816 62.669 20.136 ;
     RECT  62.104 23.376 62.705 26.232 ;
     RECT  62.104 13.104 62.741 13.128 ;
     RECT  62.104 15.168 62.777 16.92 ;
     RECT  62.705 23.376 62.885 23.928 ;
     RECT  61.811 0.144 62.917 0.168 ;
     RECT  62.669 20.112 62.957 20.136 ;
     RECT  62.104 7.968 63.109 10.296 ;
     RECT  62.885 23.376 63.157 23.448 ;
     RECT  62.917 27.888 63.203 27.912 ;
     RECT  62.104 21.552 63.205 22.104 ;
     RECT  63.157 23.136 63.205 23.448 ;
     RECT  63.109 7.968 63.251 10.44 ;
     RECT  62.777 15.168 63.253 16.392 ;
     RECT  63.253 15.168 63.277 15.384 ;
     RECT  62.533 3.408 63.281 6.84 ;
     RECT  63.251 7.968 63.289 10.344 ;
     RECT  62.533 1.728 63.397 2.328 ;
     RECT  63.281 6.768 63.413 6.84 ;
     RECT  63.289 7.968 63.413 10.296 ;
     RECT  62.917 0.096 63.493 0.168 ;
     RECT  63.397 1.44 63.493 2.328 ;
     RECT  63.413 6.768 63.497 10.296 ;
     RECT  63.421 11.376 63.505 11.4 ;
     RECT  63.205 21.552 63.605 23.448 ;
     RECT  63.497 7.872 63.677 10.296 ;
     RECT  63.281 3.408 63.685 5.352 ;
     RECT  62.705 25.056 63.713 26.232 ;
     RECT  63.497 6.768 63.731 6.888 ;
     RECT  63.605 22.08 63.749 23.448 ;
     RECT  63.677 9.024 63.821 10.296 ;
     RECT  63.277 14.832 63.829 15.384 ;
     RECT  63.749 22.08 63.865 22.824 ;
     RECT  63.865 22.08 63.878 22.68 ;
     RECT  63.253 16.368 64.177 16.392 ;
     RECT  63.997 13.056 64.217 13.08 ;
     RECT  63.829 14.832 64.249 14.952 ;
     RECT  63.685 3.312 64.316 5.352 ;
     RECT  63.731 6.768 64.316 6.84 ;
     RECT  64.165 27.888 64.355 27.912 ;
     RECT  63.493 0.096 64.357 2.328 ;
     RECT  64.316 3.312 64.357 6.84 ;
     RECT  63.821 9.552 64.361 10.296 ;
     RECT  64.285 20.496 64.369 20.52 ;
     RECT  63.709 11.424 64.501 12.024 ;
     RECT  62.669 18.816 64.501 18.984 ;
     RECT  64.177 16.368 64.547 17.112 ;
     RECT  64.501 18.24 64.549 18.984 ;
     RECT  63.878 22.08 64.645 22.632 ;
     RECT  63.677 7.872 64.717 7.992 ;
     RECT  64.361 9.552 64.757 10.056 ;
     RECT  64.717 7.872 64.801 8.568 ;
     RECT  64.249 13.968 64.861 14.952 ;
     RECT  64.801 7.872 64.865 7.896 ;
     RECT  64.861 13.968 64.969 15.048 ;
     RECT  64.501 11.424 65.029 12.504 ;
     RECT  64.549 18.24 65.029 19.368 ;
     RECT  64.645 21.648 65.029 22.632 ;
     RECT  65.029 21.408 65.041 22.632 ;
     RECT  64.357 0.096 65.077 6.84 ;
     RECT  65.029 18.24 65.081 19.464 ;
     RECT  65.081 18.816 65.116 19.464 ;
     RECT  65.077 0.096 65.221 6.888 ;
     RECT  65.029 11.28 65.221 12.504 ;
     RECT  64.969 13.968 65.221 15.912 ;
     RECT  64.757 9.984 65.267 10.056 ;
     RECT  65.267 10.032 65.549 10.056 ;
     RECT  64.547 17.088 65.612 17.112 ;
     RECT  65.041 21.408 65.621 23.352 ;
     RECT  65.612 17.088 65.693 17.64 ;
     RECT  65.693 17.616 65.699 17.64 ;
     RECT  65.317 20.16 65.701 20.184 ;
     RECT  65.621 21.408 65.701 22.248 ;
     RECT  65.221 11.28 65.725 15.912 ;
     RECT  65.725 10.8 65.729 15.912 ;
     RECT  63.713 25.68 65.729 26.232 ;
     RECT  65.221 0.096 65.765 7.8 ;
     RECT  65.729 10.8 65.873 13.992 ;
     RECT  65.729 15.216 66.053 15.912 ;
     RECT  65.873 13.968 66.089 13.992 ;
     RECT  65.701 20.16 66.197 22.248 ;
     RECT  65.729 26.064 66.521 26.232 ;
     RECT  66.521 26.064 66.701 26.184 ;
     RECT  65.765 0.096 66.805 7.656 ;
     RECT  65.873 10.8 67.093 12.888 ;
     RECT  66.053 15.216 67.093 15.768 ;
     RECT  66.805 0.048 67.208 7.656 ;
     RECT  65.185 8.976 67.208 9 ;
     RECT  67.093 10.176 67.208 12.888 ;
     RECT  67.093 14.832 67.208 15.864 ;
     RECT  65.116 18.816 67.208 18.984 ;
     RECT  66.197 20.736 67.208 22.248 ;
     RECT  65.621 23.328 67.208 23.352 ;
     RECT  67.208 0.048 67.312 25.932 ;
     RECT  67.312 0.048 67.504 25.662 ;
     RECT  67.504 16.944 67.601 21.672 ;
     RECT  67.504 8.976 67.645 10.296 ;
     RECT  67.601 18.144 67.667 21.672 ;
     RECT  67.667 20.304 67.673 21.672 ;
     RECT  67.673 20.544 67.708 21.672 ;
     RECT  67.645 8.976 67.709 10.2 ;
     RECT  67.504 11.424 67.817 11.976 ;
     RECT  67.708 20.592 67.853 21.672 ;
     RECT  67.504 14.736 67.859 15.864 ;
     RECT  67.853 20.592 67.889 20.616 ;
     RECT  67.504 0.048 67.997 7.944 ;
     RECT  67.859 14.736 68.033 14.76 ;
     RECT  67.709 8.976 68.141 9.624 ;
     RECT  67.504 23.328 68.141 23.352 ;
     RECT  68.141 8.976 68.339 9 ;
     RECT  67.504 13.104 68.387 13.128 ;
     RECT  67.601 16.944 68.387 17.112 ;
     RECT  67.817 11.952 68.429 11.976 ;
     RECT  67.667 18.144 68.627 18.984 ;
     RECT  67.859 15.84 68.897 15.864 ;
     RECT  68.387 16.944 69.617 16.968 ;
     RECT  68.627 18.96 69.617 18.984 ;
     RECT  67.997 0.048 69.833 7.416 ;
     RECT  69.833 0.048 70.406 7.08 ;
     RECT  70.406 0.096 70.841 7.08 ;
     RECT  70.841 0.096 71.229 6.84 ;
     RECT  71.229 0.096 72.608 6.264 ;
     RECT  72.608 0.096 72.712 25.932 ;
     RECT  72.712 0.096 72.904 25.662 ;
     RECT  72.904 0.096 73.145 4.776 ;
     RECT  73.145 0.192 73.505 4.776 ;
     RECT  73.505 0.192 73.685 3.336 ;
     RECT  73.685 0.816 74.045 3.336 ;
     RECT  74.045 0.96 74.153 3.336 ;
     RECT  73.505 4.704 74.585 4.776 ;
     RECT  74.585 4.752 74.657 4.776 ;
     RECT  74.153 0.96 76.421 2.856 ;
     RECT  76.421 0.96 76.853 1.032 ;
     RECT  76.853 1.008 76.997 1.032 ;
     RECT  76.421 2.064 77.285 2.856 ;
     RECT  77.285 2.148 78.008 2.856 ;
     RECT  78.008 2.148 78.112 25.932 ;
     RECT  78.112 2.418 78.304 25.662 ;
     RECT  83.408 2.148 83.512 25.932 ;
     RECT  83.512 2.418 83.704 25.662 ;
    LAYER M5 ;
     RECT  18 0.016 70.536 0.179 ;
     RECT  18.096 0.179 70.536 0.227 ;
     RECT  18.192 0.227 70.536 0.371 ;
     RECT  18.192 0.371 70.44 1.187 ;
     RECT  18.48 1.187 70.44 1.427 ;
     RECT  18.48 1.427 63.48 1.523 ;
     RECT  18.48 1.523 22.056 1.715 ;
     RECT  18.48 1.715 20.904 1.763 ;
     RECT  64.656 1.427 70.44 1.811 ;
     RECT  2.4 2.137 2.52 2.151 ;
     RECT  7.8 2.137 7.92 2.151 ;
     RECT  13.2 2.137 13.32 2.151 ;
     RECT  72.6 2.137 72.72 2.151 ;
     RECT  78 2.137 78.12 2.151 ;
     RECT  83.4 2.137 83.52 2.151 ;
     RECT  21.936 1.715 22.056 2.243 ;
     RECT  23.088 1.523 63.48 2.339 ;
     RECT  64.752 1.811 70.44 2.629 ;
     RECT  64.752 2.629 70.872 2.819 ;
     RECT  69.456 2.819 70.872 2.867 ;
     RECT  18.6 1.763 20.904 3.013 ;
     RECT  17.808 3.013 20.904 3.155 ;
     RECT  23.472 2.339 63.48 3.301 ;
     RECT  21.936 2.243 21.96 3.397 ;
     RECT  72.6 2.151 72.912 3.397 ;
     RECT  69.456 2.867 70.68 3.491 ;
     RECT  23.184 3.301 63.72 3.829 ;
     RECT  64.752 2.819 68.328 3.829 ;
     RECT  72.336 3.397 72.912 4.115 ;
     RECT  69.696 3.491 70.68 4.355 ;
     RECT  21.888 3.397 21.96 4.501 ;
     RECT  23.184 3.829 68.328 4.501 ;
     RECT  72.48 4.115 72.912 4.835 ;
     RECT  21.888 4.501 68.328 4.931 ;
     RECT  17.088 4.501 17.112 5.459 ;
     RECT  21.936 4.931 68.328 6.181 ;
     RECT  18.6 3.155 20.904 6.757 ;
     RECT  21.936 6.181 68.952 6.757 ;
     RECT  18.6 6.757 68.952 6.851 ;
     RECT  71.136 5.173 71.16 6.851 ;
     RECT  18.6 6.851 18.912 7.285 ;
     RECT  20.256 6.851 68.328 7.475 ;
     RECT  20.256 7.475 66.168 7.667 ;
     RECT  20.256 7.667 66.072 7.909 ;
     RECT  20.16 7.909 66.072 8.003 ;
     RECT  20.16 8.003 21.96 8.579 ;
     RECT  23.76 8.003 66.072 8.579 ;
     RECT  49.824 8.579 63.24 8.627 ;
     RECT  67.2 7.475 68.328 9.011 ;
     RECT  24 8.579 48.456 9.155 ;
     RECT  49.968 8.627 63.24 9.203 ;
     RECT  24 9.155 37.704 9.251 ;
     RECT  17.952 7.285 18.912 9.683 ;
     RECT  24 9.251 36.792 9.731 ;
     RECT  42.72 9.155 48.456 9.731 ;
     RECT  49.968 9.203 59.736 9.731 ;
     RECT  20.16 8.579 21.24 9.779 ;
     RECT  58.512 9.731 59.736 9.779 ;
     RECT  67.2 9.011 67.608 10.165 ;
     RECT  15.792 8.341 15.816 10.259 ;
     RECT  24 9.731 36.744 10.307 ;
     RECT  38.976 9.155 41.736 10.307 ;
     RECT  64.32 8.579 66.072 10.307 ;
     RECT  67.104 10.165 67.608 10.307 ;
     RECT  21.072 9.779 21.24 10.355 ;
     RECT  24 10.307 35.4 10.355 ;
     RECT  43.152 9.731 48.456 10.595 ;
     RECT  36.384 10.307 36.744 10.883 ;
     RECT  58.608 9.779 59.736 10.883 ;
     RECT  64.368 10.307 66.072 10.883 ;
     RECT  38.976 10.307 41.304 10.931 ;
     RECT  50.112 9.731 57.48 11.029 ;
     RECT  24 10.355 35.112 11.219 ;
     RECT  43.152 10.595 47.832 11.269 ;
     RECT  60.864 9.203 63.24 11.365 ;
     RECT  64.368 10.883 65.832 11.365 ;
     RECT  42.624 11.269 47.832 11.459 ;
     RECT  58.8 10.883 59.736 11.459 ;
     RECT  60.864 11.365 65.832 11.459 ;
     RECT  44.304 11.459 45.912 11.555 ;
     RECT  58.8 11.459 59.256 11.699 ;
     RECT  36.72 10.883 36.744 11.893 ;
     RECT  21.216 10.355 21.24 11.941 ;
     RECT  24 11.219 26.328 11.941 ;
     RECT  67.104 10.307 67.512 11.941 ;
     RECT  36.336 11.893 36.744 11.987 ;
     RECT  38.976 10.931 40.512 12.035 ;
     RECT  50.064 11.029 57.48 12.035 ;
     RECT  38.976 12.035 39 12.083 ;
     RECT  50.064 12.035 51.312 12.131 ;
     RECT  27.36 11.219 35.112 12.227 ;
     RECT  61.104 11.459 65.832 12.515 ;
     RECT  20.64 11.941 21.24 12.563 ;
     RECT  27.36 12.227 33.528 12.563 ;
     RECT  61.104 12.515 64.392 12.563 ;
     RECT  65.568 12.515 65.832 12.563 ;
     RECT  28.992 12.563 33.528 12.659 ;
     RECT  52.8 12.035 55.224 12.659 ;
     RECT  48.288 11.845 48.312 12.757 ;
     RECT  27.36 12.563 27.384 12.803 ;
     RECT  28.992 12.659 32.616 12.803 ;
     RECT  48.288 12.757 48.744 12.803 ;
     RECT  23.088 11.941 26.328 12.899 ;
     RECT  56.4 12.035 57.48 12.901 ;
     RECT  58.8 11.699 59.016 12.997 ;
     RECT  47.136 11.459 47.16 13.045 ;
     RECT  23.088 12.899 25.176 13.139 ;
     RECT  36.336 11.987 36.36 13.139 ;
     RECT  52.8 12.659 55.176 13.139 ;
     RECT  67.104 11.941 68.376 13.139 ;
     RECT  50.112 12.131 51.312 13.187 ;
     RECT  54.816 13.139 55.176 13.235 ;
     RECT  34.56 12.227 35.112 13.283 ;
     RECT  56.4 12.901 57.528 13.331 ;
     RECT  21.216 12.563 21.24 13.477 ;
     RECT  40.2 12.035 40.512 13.477 ;
     RECT  48.72 12.803 48.744 13.523 ;
     RECT  65.568 12.563 65.592 13.571 ;
     RECT  55.152 13.235 55.176 13.715 ;
     RECT  28.992 12.803 31.368 13.813 ;
     RECT  28.608 13.813 31.368 13.957 ;
     RECT  32.592 12.803 32.616 13.957 ;
     RECT  58.704 12.997 59.016 14.005 ;
     RECT  24 13.139 25.176 14.197 ;
     RECT  26.208 12.899 26.328 14.197 ;
     RECT  28.608 13.957 32.616 14.245 ;
     RECT  52.8 13.139 53.448 14.245 ;
     RECT  24 14.197 26.328 14.291 ;
     RECT  44.496 11.555 45.912 14.291 ;
     RECT  52.8 14.245 53.592 14.291 ;
     RECT  39.456 13.477 40.512 14.387 ;
     RECT  42.624 11.459 43.32 14.389 ;
     RECT  25.392 14.291 26.328 14.531 ;
     RECT  27.648 14.245 32.616 14.627 ;
     RECT  34.704 13.283 35.112 14.773 ;
     RECT  49.824 13.477 49.848 14.773 ;
     RECT  50.832 13.187 51.312 14.773 ;
     RECT  61.8 12.563 64.392 14.773 ;
     RECT  47.136 13.045 47.256 14.867 ;
     RECT  61.008 14.773 64.392 14.963 ;
     RECT  25.392 14.531 25.416 15.203 ;
     RECT  67.104 13.139 67.512 15.205 ;
     RECT  58.128 14.005 59.016 15.301 ;
     RECT  0.144 13.573 0.168 15.347 ;
     RECT  61.008 14.963 63.816 15.347 ;
     RECT  56.4 13.331 57 15.349 ;
     RECT  58.128 15.301 59.256 15.349 ;
     RECT  56.4 15.349 59.256 15.395 ;
     RECT  66.528 15.205 67.512 15.397 ;
     RECT  27.648 14.627 31.8 15.443 ;
     RECT  53.328 14.291 53.592 15.491 ;
     RECT  27.648 15.443 27.672 15.683 ;
     RECT  66.528 15.397 67.848 15.875 ;
     RECT  47.232 14.867 47.256 15.925 ;
     RECT  42.144 14.389 43.32 16.019 ;
     RECT  45.12 14.291 45.912 16.019 ;
     RECT  61.8 15.347 63.816 16.019 ;
     RECT  28.992 15.443 31.8 16.259 ;
     RECT  49.824 14.773 51.312 16.259 ;
     RECT  61.8 16.019 62.112 16.357 ;
     RECT  63.456 16.019 63.816 16.403 ;
     RECT  40.2 14.387 40.512 16.501 ;
     RECT  51 16.259 51.312 16.501 ;
     RECT  63.792 16.403 63.816 16.501 ;
     RECT  22.752 16.501 22.776 16.597 ;
     RECT  22.512 16.597 22.776 16.643 ;
     RECT  38.736 15.973 38.76 16.835 ;
     RECT  45.504 16.019 45.912 16.835 ;
     RECT  53.568 15.491 53.592 16.835 ;
     RECT  66.528 15.875 67.512 16.933 ;
     RECT  28.992 16.259 31.512 17.029 ;
     RECT  56.4 15.395 57.384 17.029 ;
     RECT  58.992 15.395 59.256 17.029 ;
     RECT  55.824 17.029 57.384 17.075 ;
     RECT  20.16 14.725 20.184 17.077 ;
     RECT  21.216 13.477 21.48 17.077 ;
     RECT  28.944 17.029 31.512 17.171 ;
     RECT  34.704 14.773 35.832 17.171 ;
     RECT  58.992 17.029 59.304 17.171 ;
     RECT  15.936 16.501 15.96 17.603 ;
     RECT  20.16 17.077 21.48 17.605 ;
     RECT  22.512 16.643 22.536 17.605 ;
     RECT  31.296 17.171 31.512 17.605 ;
     RECT  66.528 16.933 68.376 17.605 ;
     RECT  59.28 17.171 59.304 17.651 ;
     RECT  27.216 16.549 27.24 17.699 ;
     RECT  42.624 16.019 43.32 17.699 ;
     RECT  20.16 17.605 22.536 18.035 ;
     RECT  28.944 17.171 30.216 18.035 ;
     RECT  34.704 17.171 35.784 18.133 ;
     RECT  65.664 17.605 68.376 18.133 ;
     RECT  34.272 18.133 35.784 18.179 ;
     RECT  51 16.501 52.104 18.179 ;
     RECT  18.6 9.683 18.912 18.181 ;
     RECT  42.624 17.699 42.648 18.275 ;
     RECT  63.792 16.501 64.536 18.275 ;
     RECT  65.664 18.133 68.616 18.275 ;
     RECT  49.824 16.259 49.848 18.277 ;
     RECT  51 18.179 51.312 18.277 ;
     RECT  21.648 18.035 22.536 18.325 ;
     RECT  40.2 16.501 41.304 18.419 ;
     RECT  47.136 15.925 47.256 18.515 ;
     RECT  49.824 18.277 51.312 18.515 ;
     RECT  55.824 17.075 56.712 18.565 ;
     RECT  21.648 18.325 22.824 18.707 ;
     RECT  24 14.291 24.408 18.757 ;
     RECT  17.616 18.181 18.912 18.851 ;
     RECT  20.16 18.035 20.184 18.851 ;
     RECT  31.296 17.605 31.896 18.851 ;
     RECT  42.288 18.373 42.312 18.851 ;
     RECT  61.68 16.357 62.112 18.949 ;
     RECT  65.664 18.275 67.512 18.949 ;
     RECT  65.04 18.949 67.512 18.995 ;
     RECT  68.592 18.275 68.616 18.995 ;
     RECT  34.272 18.179 35.112 19.235 ;
     RECT  59.52 18.181 59.544 19.235 ;
     RECT  18.6 18.851 18.912 19.333 ;
     RECT  63.792 18.275 63.816 19.333 ;
     RECT  65.04 18.995 65.064 19.333 ;
     RECT  55.536 18.565 56.712 19.379 ;
     RECT  24 18.757 24.552 19.477 ;
     RECT  24 19.477 25.512 19.523 ;
     RECT  60.624 18.949 60.648 19.763 ;
     RECT  31.344 18.851 31.896 19.811 ;
     RECT  66.528 18.995 67.512 19.861 ;
     RECT  15.648 19.093 15.672 19.909 ;
     RECT  21.648 18.707 22.584 19.955 ;
     RECT  25.488 19.523 25.512 20.003 ;
     RECT  49.824 18.515 49.848 20.003 ;
     RECT  52.464 19.333 52.488 20.053 ;
     RECT  61.68 18.949 62.664 20.147 ;
     RECT  63.792 19.333 65.064 20.149 ;
     RECT  31.344 19.811 31.368 20.339 ;
     RECT  48.528 17.077 48.552 20.339 ;
     RECT  22.56 19.955 22.584 20.437 ;
     RECT  18.6 19.333 19.32 20.485 ;
     RECT  45.6 16.835 45.912 20.485 ;
     RECT  47.136 18.515 47.16 20.485 ;
     RECT  51 18.515 51.312 20.485 ;
     RECT  52.464 20.053 53.064 20.531 ;
     RECT  28.992 18.035 30.216 20.579 ;
     RECT  56.304 19.379 56.712 20.579 ;
     RECT  56.4 20.579 56.712 20.629 ;
     RECT  63.792 20.149 65.352 20.725 ;
     RECT  66.528 19.861 67.656 20.725 ;
     RECT  61.68 20.147 62.112 20.965 ;
     RECT  44.016 20.437 44.04 21.109 ;
     RECT  37.584 17.605 37.608 21.155 ;
     RECT  50.16 20.485 51.312 21.155 ;
     RECT  63.792 20.725 67.656 21.155 ;
     RECT  24 19.523 24.408 21.203 ;
     RECT  63.792 21.155 67.512 21.203 ;
     RECT  54.576 21.109 54.6 21.251 ;
     RECT  18.6 20.485 19.896 21.395 ;
     RECT  43.248 21.109 44.04 21.445 ;
     RECT  45.6 20.485 47.16 21.491 ;
     RECT  27.12 21.013 27.144 21.539 ;
     RECT  53.04 20.531 53.064 21.541 ;
     RECT  61.008 20.965 62.112 21.541 ;
     RECT  22.56 20.437 22.872 21.637 ;
     RECT  45.6 21.491 45.912 21.781 ;
     RECT  61.008 21.541 62.76 22.021 ;
     RECT  63.792 21.203 66.12 22.021 ;
     RECT  15.168 19.909 15.672 22.117 ;
     RECT  15.168 22.117 16.344 22.213 ;
     RECT  22.224 21.637 22.872 22.213 ;
     RECT  24 21.203 24.312 22.213 ;
     RECT  43.248 21.445 44.424 22.213 ;
     RECT  45.504 21.781 45.912 22.213 ;
     RECT  61.008 22.021 66.12 22.213 ;
     RECT  42.144 21.637 42.168 22.499 ;
     RECT  15.168 22.213 16.488 22.597 ;
     RECT  56.4 20.629 57.288 22.739 ;
     RECT  26.784 22.021 26.808 22.741 ;
     RECT  51 21.155 51.312 22.741 ;
     RECT  54.624 22.117 54.648 22.787 ;
     RECT  28.992 20.579 29.712 22.885 ;
     RECT  39.12 21.061 39.144 22.979 ;
     RECT  26.784 22.741 27.528 23.125 ;
     RECT  22.224 22.213 24.312 23.269 ;
     RECT  52.464 21.541 53.064 23.315 ;
     RECT  22.224 23.269 24.408 23.365 ;
     RECT  43.152 22.213 45.912 23.365 ;
     RECT  47.136 21.491 47.16 23.365 ;
     RECT  52.56 23.315 53.064 23.411 ;
     RECT  59.28 21.637 59.304 23.411 ;
     RECT  26.784 23.125 27.912 23.555 ;
     RECT  28.992 22.885 30.12 23.747 ;
     RECT  22.224 23.365 24.84 23.845 ;
     RECT  40.2 18.419 40.512 23.845 ;
     RECT  18.6 21.395 19.32 23.893 ;
     RECT  22.224 23.845 25.032 23.893 ;
     RECT  50.88 22.741 51.312 24.325 ;
     RECT  40.032 23.845 40.776 24.373 ;
     RECT  28.992 23.747 29.712 24.563 ;
     RECT  50.784 24.325 51.312 24.611 ;
     RECT  60.528 22.213 66.12 24.709 ;
     RECT  39.984 24.373 40.776 24.757 ;
     RECT  18.6 23.893 19.704 24.997 ;
     RECT  27.504 23.555 27.912 24.997 ;
     RECT  21.12 23.893 21.144 25.045 ;
     RECT  22.224 23.893 25.656 25.045 ;
     RECT  26.64 24.997 27.912 25.045 ;
     RECT  60.24 24.709 66.12 25.045 ;
     RECT  21.072 25.045 27.912 25.285 ;
     RECT  21.072 25.285 28.008 25.525 ;
     RECT  29.28 24.563 29.712 25.525 ;
     RECT  32.304 24.517 32.328 25.573 ;
     RECT  13.2 2.151 13.512 25.669 ;
     RECT  15.168 22.597 17.064 25.669 ;
     RECT  18.48 24.997 19.704 25.669 ;
     RECT  21.072 25.525 29.712 25.669 ;
     RECT  32.016 25.573 32.328 25.669 ;
     RECT  34.8 19.235 35.112 25.669 ;
     RECT  36.288 23.845 36.312 25.669 ;
     RECT  39.792 24.757 40.776 25.669 ;
     RECT  43.152 23.365 47.16 25.669 ;
     RECT  50.832 24.611 51.312 25.669 ;
     RECT  52.56 23.411 52.872 25.669 ;
     RECT  54.768 25.093 54.792 25.669 ;
     RECT  56.4 22.739 57.096 25.669 ;
     RECT  59.952 25.045 66.12 25.669 ;
     RECT  13.2 25.669 40.872 25.717 ;
     RECT  42.288 25.669 47.16 25.717 ;
     RECT  13.2 25.717 47.16 25.813 ;
     RECT  48.24 25.669 57.576 25.813 ;
     RECT  2.4 2.151 2.712 25.929 ;
     RECT  7.8 2.151 8.112 25.929 ;
     RECT  67.2 21.203 67.512 25.929 ;
     RECT  72.6 4.835 72.912 25.929 ;
     RECT  78 2.151 78.312 25.929 ;
     RECT  83.4 2.151 83.712 25.929 ;
     RECT  2.4 25.929 2.52 25.943 ;
     RECT  7.8 25.929 7.92 25.943 ;
     RECT  13.2 25.813 57.576 25.943 ;
     RECT  67.2 25.929 67.32 25.943 ;
     RECT  72.6 25.929 72.72 25.943 ;
     RECT  78 25.929 78.12 25.943 ;
     RECT  83.4 25.929 83.52 25.943 ;
     RECT  14.064 25.943 57.576 26.053 ;
     RECT  58.608 25.669 66.12 26.053 ;
     RECT  14.064 26.053 66.408 28.048 ;
     RECT  63.48 1.427 64.656 1.811 ;
     RECT  22.056 1.523 23.088 2.243 ;
     RECT  20.904 1.715 21.936 3.397 ;
     RECT  18.48 1.763 18.6 3.013 ;
     RECT  63.48 1.811 64.752 3.301 ;
     RECT  21.96 2.243 23.088 2.339 ;
     RECT  21.96 2.339 23.472 3.301 ;
     RECT  68.328 2.819 69.456 3.491 ;
     RECT  17.808 3.155 18.6 4.501 ;
     RECT  21.96 3.301 23.184 4.501 ;
     RECT  63.72 3.301 64.752 3.829 ;
     RECT  20.904 3.397 21.888 4.931 ;
     RECT  68.328 3.491 69.696 4.355 ;
     RECT  72.336 4.115 72.48 4.835 ;
     RECT  17.112 4.501 18.6 5.459 ;
     RECT  72.336 4.835 72.6 5.173 ;
     RECT  20.904 4.931 21.936 6.757 ;
     RECT  71.16 5.173 72.6 6.851 ;
     RECT  18.912 6.851 20.256 7.909 ;
     RECT  66.168 7.475 67.2 7.667 ;
     RECT  66.072 7.667 67.2 10.165 ;
     RECT  18.912 7.909 20.16 9.779 ;
     RECT  48.456 8.579 49.824 8.627 ;
     RECT  63.24 8.579 64.32 10.307 ;
     RECT  48.456 8.627 49.968 9.731 ;
     RECT  37.704 9.155 38.976 9.251 ;
     RECT  41.736 9.155 42.72 9.731 ;
     RECT  59.736 9.203 60.864 11.459 ;
     RECT  41.736 9.731 43.152 10.307 ;
     RECT  50.064 9.731 50.112 11.029 ;
     RECT  57.48 9.731 58.512 9.779 ;
     RECT  57.48 9.779 58.608 10.883 ;
     RECT  66.072 10.165 67.104 10.883 ;
     RECT  35.4 10.307 36.384 10.355 ;
     RECT  41.304 10.307 43.152 10.931 ;
     RECT  63.24 10.307 64.368 11.365 ;
     RECT  35.112 10.355 36.384 10.883 ;
     RECT  47.832 10.595 48.312 11.459 ;
     RECT  35.112 10.883 36.72 11.893 ;
     RECT  57.48 10.883 58.8 12.901 ;
     RECT  65.832 10.883 67.104 12.563 ;
     RECT  42.624 10.931 43.152 11.269 ;
     RECT  26.328 11.219 27.36 12.803 ;
     RECT  43.32 11.459 44.304 11.555 ;
     RECT  45.912 11.459 47.136 14.867 ;
     RECT  47.16 11.459 48.312 11.845 ;
     RECT  43.32 11.555 44.496 14.291 ;
     RECT  47.16 11.845 48.288 12.803 ;
     RECT  35.112 11.893 36.336 13.139 ;
     RECT  39 12.035 40.2 12.083 ;
     RECT  51.312 12.035 52.8 14.291 ;
     RECT  55.224 12.035 56.4 12.659 ;
     RECT  39.456 12.083 40.2 13.477 ;
     RECT  50.064 12.131 50.112 12.757 ;
     RECT  33.528 12.227 34.56 12.659 ;
     RECT  64.392 12.515 65.568 13.571 ;
     RECT  27.384 12.563 28.992 12.803 ;
     RECT  65.592 12.563 67.104 13.571 ;
     RECT  55.176 12.659 56.4 13.715 ;
     RECT  48.744 12.757 50.112 13.187 ;
     RECT  26.328 12.803 28.992 13.813 ;
     RECT  31.368 12.803 32.592 13.957 ;
     RECT  47.16 12.803 48.72 13.045 ;
     RECT  25.176 12.899 26.208 14.197 ;
     RECT  57.528 12.901 58.8 12.997 ;
     RECT  57.528 12.997 58.704 13.331 ;
     RECT  47.256 13.045 48.72 13.523 ;
     RECT  53.448 13.139 54.816 13.235 ;
     RECT  48.744 13.187 50.832 13.477 ;
     RECT  53.448 13.235 53.592 14.245 ;
     RECT  57 13.331 58.704 14.005 ;
     RECT  48.744 13.477 49.824 13.523 ;
     RECT  49.848 13.477 50.832 14.773 ;
     RECT  26.328 13.813 28.608 14.245 ;
     RECT  57 14.005 58.128 15.349 ;
     RECT  26.328 14.245 27.648 14.531 ;
     RECT  24.408 14.291 25.392 15.203 ;
     RECT  18.912 14.725 20.16 18.851 ;
     RECT  20.184 14.725 21.216 17.077 ;
     RECT  45.912 14.867 47.232 15.925 ;
     RECT  61.68 15.347 61.8 16.357 ;
     RECT  27.672 15.443 28.992 15.683 ;
     RECT  53.328 15.491 53.568 16.501 ;
     RECT  28.944 15.683 28.992 17.029 ;
     RECT  67.512 15.875 67.848 16.933 ;
     RECT  45.912 15.925 47.136 20.485 ;
     RECT  38.76 15.973 40.2 16.835 ;
     RECT  42.144 16.019 42.624 16.501 ;
     RECT  62.112 16.019 63.456 16.403 ;
     RECT  31.512 16.259 31.8 17.605 ;
     RECT  49.848 16.259 51 18.277 ;
     RECT  21.48 16.501 22.752 16.597 ;
     RECT  22.776 16.501 24 16.643 ;
     RECT  41.304 16.501 42.624 18.275 ;
     RECT  52.104 16.501 53.568 16.835 ;
     RECT  21.48 16.597 22.512 17.605 ;
     RECT  22.536 16.643 24 18.325 ;
     RECT  47.256 17.077 48.528 18.515 ;
     RECT  48.552 17.077 49.824 20.003 ;
     RECT  30.216 17.171 31.296 18.851 ;
     RECT  64.536 17.605 65.664 18.275 ;
     RECT  20.184 18.035 21.648 18.851 ;
     RECT  51.312 18.179 52.104 19.333 ;
     RECT  41.304 18.275 42.312 18.373 ;
     RECT  63.816 18.275 65.664 18.949 ;
     RECT  67.512 18.275 68.592 18.995 ;
     RECT  22.824 18.325 24 18.707 ;
     RECT  41.304 18.373 42.288 18.419 ;
     RECT  47.16 18.515 48.528 20.339 ;
     RECT  49.848 18.515 51 20.003 ;
     RECT  22.584 18.707 24 20.437 ;
     RECT  18.912 18.851 19.32 19.333 ;
     RECT  30.216 18.851 31.344 20.339 ;
     RECT  59.544 18.949 60.624 19.235 ;
     RECT  60.648 18.949 61.68 19.763 ;
     RECT  62.664 18.949 63.792 20.147 ;
     RECT  63.816 18.949 65.04 19.333 ;
     RECT  65.064 18.995 66.528 20.149 ;
     RECT  67.512 18.995 67.656 19.861 ;
     RECT  51.312 19.333 52.464 20.531 ;
     RECT  24.408 19.523 25.488 20.003 ;
     RECT  61.008 19.763 61.68 20.965 ;
     RECT  50.16 20.003 51 20.485 ;
     RECT  62.112 20.147 63.792 21.541 ;
     RECT  65.352 20.149 66.528 20.725 ;
     RECT  22.872 20.437 24 22.213 ;
     RECT  51.312 20.531 53.04 21.541 ;
     RECT  37.608 21.061 39.12 21.155 ;
     RECT  39.144 21.061 40.2 22.979 ;
     RECT  53.064 21.109 54.576 21.251 ;
     RECT  66.12 21.203 67.2 25.943 ;
     RECT  44.424 21.445 45.6 21.781 ;
     RECT  45.912 21.491 47.136 23.365 ;
     RECT  27.12 21.539 27.144 22.021 ;
     RECT  51.312 21.541 52.464 23.315 ;
     RECT  62.76 21.541 63.792 22.021 ;
     RECT  42.168 21.637 43.248 22.213 ;
     RECT  44.424 21.781 45.504 22.213 ;
     RECT  26.808 22.021 27.144 22.741 ;
     RECT  42.168 22.213 43.152 22.499 ;
     RECT  59.304 22.213 60.528 23.411 ;
     RECT  27.528 22.741 28.992 23.125 ;
     RECT  39.984 22.979 40.2 23.845 ;
     RECT  27.912 23.125 28.992 24.563 ;
     RECT  51.312 23.315 52.56 25.669 ;
     RECT  60.24 23.411 60.528 24.709 ;
     RECT  26.784 23.555 27.504 23.893 ;
     RECT  35.112 23.845 36.288 25.669 ;
     RECT  39.984 23.845 40.032 24.373 ;
     RECT  19.704 23.893 21.12 25.045 ;
     RECT  21.144 23.893 22.224 25.045 ;
     RECT  25.656 23.893 27.504 24.997 ;
     RECT  27.912 24.563 29.28 25.285 ;
     RECT  50.784 24.611 50.832 25.669 ;
     RECT  17.064 24.997 18.48 25.669 ;
     RECT  25.656 24.997 26.64 25.045 ;
     RECT  19.704 25.045 21.072 25.669 ;
     RECT  28.008 25.285 29.28 25.525 ;
     RECT  40.872 25.669 42.288 25.717 ;
     RECT  47.16 25.669 48.24 25.813 ;
     RECT  57.576 25.669 58.608 26.053 ;
     RECT  66.12 25.943 66.408 26.053 ;
  END
END ot_qkvd_ke_ro
END LIBRARY
